VERSION 5.8 ;
BUSBITCHARS "[]" ;
DIVIDERCHAR "/" ;
UNITS
    DATABASE MICRONS 1000 ;
END UNITS

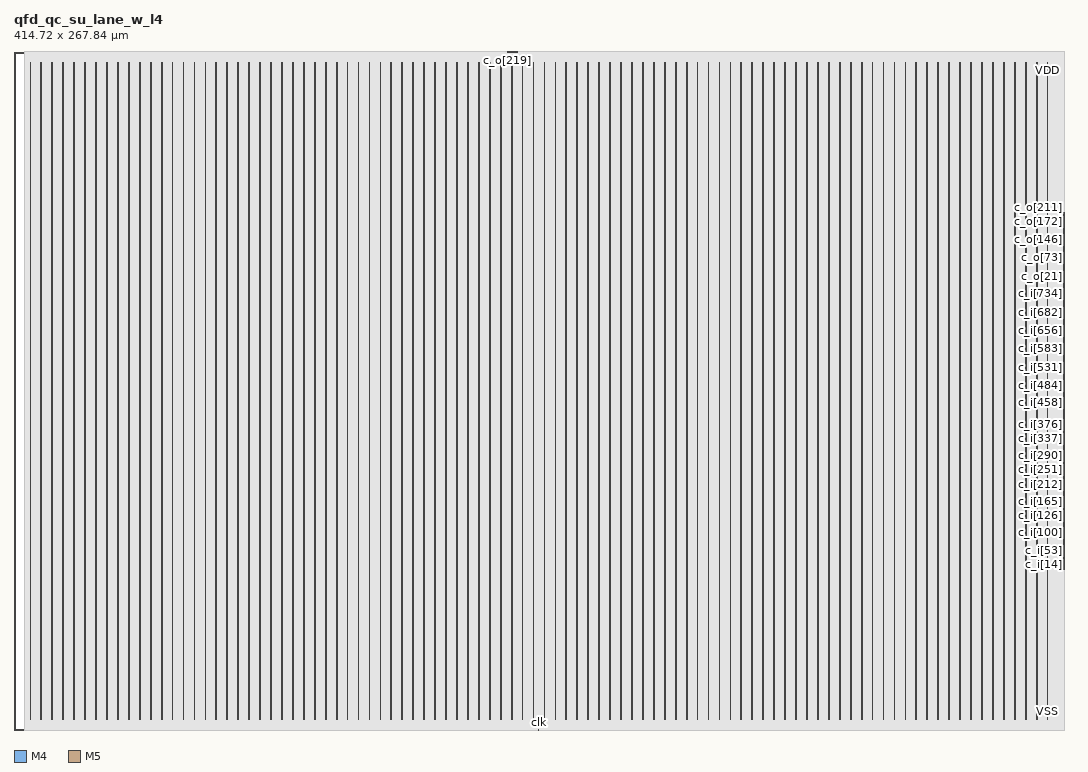
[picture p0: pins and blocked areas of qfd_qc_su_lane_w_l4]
MACRO qfd_qc_su_lane_w_l4
  FOREIGN qfd_qc_su_lane_w_l4 0 0 ;
  CLASS BLOCK ;
  SIZE 414.72 BY 267.84 ;
  PIN c_i[0]
    DIRECTION INPUT ;
    USE SIGNAL ;
    PORT
      LAYER M4 ;
        RECT  414.636 63.408 414.72 63.432 ;
    END
  END c_i[0]
  PIN c_i[100]
    DIRECTION INPUT ;
    USE SIGNAL ;
    PORT
      LAYER M4 ;
        RECT  414.636 77.808 414.72 77.832 ;
    END
  END c_i[100]
  PIN c_i[101]
    DIRECTION INPUT ;
    USE SIGNAL ;
    PORT
      LAYER M4 ;
        RECT  414.636 77.952 414.72 77.976 ;
    END
  END c_i[101]
  PIN c_i[102]
    DIRECTION INPUT ;
    USE SIGNAL ;
    PORT
      LAYER M4 ;
        RECT  414.636 78.096 414.72 78.12 ;
    END
  END c_i[102]
  PIN c_i[103]
    DIRECTION INPUT ;
    USE SIGNAL ;
    PORT
      LAYER M4 ;
        RECT  414.636 78.24 414.72 78.264 ;
    END
  END c_i[103]
  PIN c_i[104]
    DIRECTION INPUT ;
    USE SIGNAL ;
    PORT
      LAYER M4 ;
        RECT  414.636 78.384 414.72 78.408 ;
    END
  END c_i[104]
  PIN c_i[105]
    DIRECTION INPUT ;
    USE SIGNAL ;
    PORT
      LAYER M4 ;
        RECT  414.636 78.528 414.72 78.552 ;
    END
  END c_i[105]
  PIN c_i[106]
    DIRECTION INPUT ;
    USE SIGNAL ;
    PORT
      LAYER M4 ;
        RECT  414.636 78.672 414.72 78.696 ;
    END
  END c_i[106]
  PIN c_i[107]
    DIRECTION INPUT ;
    USE SIGNAL ;
    PORT
      LAYER M4 ;
        RECT  414.636 78.816 414.72 78.84 ;
    END
  END c_i[107]
  PIN c_i[108]
    DIRECTION INPUT ;
    USE SIGNAL ;
    PORT
      LAYER M4 ;
        RECT  414.636 78.96 414.72 78.984 ;
    END
  END c_i[108]
  PIN c_i[109]
    DIRECTION INPUT ;
    USE SIGNAL ;
    PORT
      LAYER M4 ;
        RECT  414.636 79.104 414.72 79.128 ;
    END
  END c_i[109]
  PIN c_i[10]
    DIRECTION INPUT ;
    USE SIGNAL ;
    PORT
      LAYER M4 ;
        RECT  414.636 64.848 414.72 64.872 ;
    END
  END c_i[10]
  PIN c_i[110]
    DIRECTION INPUT ;
    USE SIGNAL ;
    PORT
      LAYER M4 ;
        RECT  414.636 79.248 414.72 79.272 ;
    END
  END c_i[110]
  PIN c_i[111]
    DIRECTION INPUT ;
    USE SIGNAL ;
    PORT
      LAYER M4 ;
        RECT  414.636 79.392 414.72 79.416 ;
    END
  END c_i[111]
  PIN c_i[112]
    DIRECTION INPUT ;
    USE SIGNAL ;
    PORT
      LAYER M4 ;
        RECT  414.636 79.536 414.72 79.56 ;
    END
  END c_i[112]
  PIN c_i[113]
    DIRECTION INPUT ;
    USE SIGNAL ;
    PORT
      LAYER M4 ;
        RECT  414.636 79.68 414.72 79.704 ;
    END
  END c_i[113]
  PIN c_i[114]
    DIRECTION INPUT ;
    USE SIGNAL ;
    PORT
      LAYER M4 ;
        RECT  414.636 79.824 414.72 79.848 ;
    END
  END c_i[114]
  PIN c_i[115]
    DIRECTION INPUT ;
    USE SIGNAL ;
    PORT
      LAYER M4 ;
        RECT  414.636 79.968 414.72 79.992 ;
    END
  END c_i[115]
  PIN c_i[116]
    DIRECTION INPUT ;
    USE SIGNAL ;
    PORT
      LAYER M4 ;
        RECT  414.636 80.112 414.72 80.136 ;
    END
  END c_i[116]
  PIN c_i[117]
    DIRECTION INPUT ;
    USE SIGNAL ;
    PORT
      LAYER M4 ;
        RECT  414.636 80.256 414.72 80.28 ;
    END
  END c_i[117]
  PIN c_i[118]
    DIRECTION INPUT ;
    USE SIGNAL ;
    PORT
      LAYER M4 ;
        RECT  414.636 80.4 414.72 80.424 ;
    END
  END c_i[118]
  PIN c_i[119]
    DIRECTION INPUT ;
    USE SIGNAL ;
    PORT
      LAYER M4 ;
        RECT  414.636 80.544 414.72 80.568 ;
    END
  END c_i[119]
  PIN c_i[11]
    DIRECTION INPUT ;
    USE SIGNAL ;
    PORT
      LAYER M4 ;
        RECT  414.636 64.992 414.72 65.016 ;
    END
  END c_i[11]
  PIN c_i[120]
    DIRECTION INPUT ;
    USE SIGNAL ;
    PORT
      LAYER M4 ;
        RECT  414.636 80.688 414.72 80.712 ;
    END
  END c_i[120]
  PIN c_i[121]
    DIRECTION INPUT ;
    USE SIGNAL ;
    PORT
      LAYER M4 ;
        RECT  414.636 80.832 414.72 80.856 ;
    END
  END c_i[121]
  PIN c_i[122]
    DIRECTION INPUT ;
    USE SIGNAL ;
    PORT
      LAYER M4 ;
        RECT  414.636 80.976 414.72 81 ;
    END
  END c_i[122]
  PIN c_i[123]
    DIRECTION INPUT ;
    USE SIGNAL ;
    PORT
      LAYER M4 ;
        RECT  414.636 81.12 414.72 81.144 ;
    END
  END c_i[123]
  PIN c_i[124]
    DIRECTION INPUT ;
    USE SIGNAL ;
    PORT
      LAYER M4 ;
        RECT  414.636 81.264 414.72 81.288 ;
    END
  END c_i[124]
  PIN c_i[125]
    DIRECTION INPUT ;
    USE SIGNAL ;
    PORT
      LAYER M4 ;
        RECT  414.636 81.408 414.72 81.432 ;
    END
  END c_i[125]
  PIN c_i[126]
    DIRECTION INPUT ;
    USE SIGNAL ;
    PORT
      LAYER M4 ;
        RECT  414.636 81.552 414.72 81.576 ;
    END
  END c_i[126]
  PIN c_i[127]
    DIRECTION INPUT ;
    USE SIGNAL ;
    PORT
      LAYER M4 ;
        RECT  414.636 81.696 414.72 81.72 ;
    END
  END c_i[127]
  PIN c_i[128]
    DIRECTION INPUT ;
    USE SIGNAL ;
    PORT
      LAYER M4 ;
        RECT  414.636 81.84 414.72 81.864 ;
    END
  END c_i[128]
  PIN c_i[129]
    DIRECTION INPUT ;
    USE SIGNAL ;
    PORT
      LAYER M4 ;
        RECT  414.636 81.984 414.72 82.008 ;
    END
  END c_i[129]
  PIN c_i[12]
    DIRECTION INPUT ;
    USE SIGNAL ;
    PORT
      LAYER M4 ;
        RECT  414.636 65.136 414.72 65.16 ;
    END
  END c_i[12]
  PIN c_i[130]
    DIRECTION INPUT ;
    USE SIGNAL ;
    PORT
      LAYER M4 ;
        RECT  414.636 82.128 414.72 82.152 ;
    END
  END c_i[130]
  PIN c_i[131]
    DIRECTION INPUT ;
    USE SIGNAL ;
    PORT
      LAYER M4 ;
        RECT  414.636 82.272 414.72 82.296 ;
    END
  END c_i[131]
  PIN c_i[132]
    DIRECTION INPUT ;
    USE SIGNAL ;
    PORT
      LAYER M4 ;
        RECT  414.636 82.416 414.72 82.44 ;
    END
  END c_i[132]
  PIN c_i[133]
    DIRECTION INPUT ;
    USE SIGNAL ;
    PORT
      LAYER M4 ;
        RECT  414.636 82.56 414.72 82.584 ;
    END
  END c_i[133]
  PIN c_i[134]
    DIRECTION INPUT ;
    USE SIGNAL ;
    PORT
      LAYER M4 ;
        RECT  414.636 82.704 414.72 82.728 ;
    END
  END c_i[134]
  PIN c_i[135]
    DIRECTION INPUT ;
    USE SIGNAL ;
    PORT
      LAYER M4 ;
        RECT  414.636 82.848 414.72 82.872 ;
    END
  END c_i[135]
  PIN c_i[136]
    DIRECTION INPUT ;
    USE SIGNAL ;
    PORT
      LAYER M4 ;
        RECT  414.636 82.992 414.72 83.016 ;
    END
  END c_i[136]
  PIN c_i[137]
    DIRECTION INPUT ;
    USE SIGNAL ;
    PORT
      LAYER M4 ;
        RECT  414.636 83.136 414.72 83.16 ;
    END
  END c_i[137]
  PIN c_i[138]
    DIRECTION INPUT ;
    USE SIGNAL ;
    PORT
      LAYER M4 ;
        RECT  414.636 83.28 414.72 83.304 ;
    END
  END c_i[138]
  PIN c_i[139]
    DIRECTION INPUT ;
    USE SIGNAL ;
    PORT
      LAYER M4 ;
        RECT  414.636 83.424 414.72 83.448 ;
    END
  END c_i[139]
  PIN c_i[13]
    DIRECTION INPUT ;
    USE SIGNAL ;
    PORT
      LAYER M4 ;
        RECT  414.636 65.28 414.72 65.304 ;
    END
  END c_i[13]
  PIN c_i[140]
    DIRECTION INPUT ;
    USE SIGNAL ;
    PORT
      LAYER M4 ;
        RECT  414.636 83.568 414.72 83.592 ;
    END
  END c_i[140]
  PIN c_i[141]
    DIRECTION INPUT ;
    USE SIGNAL ;
    PORT
      LAYER M4 ;
        RECT  414.636 83.712 414.72 83.736 ;
    END
  END c_i[141]
  PIN c_i[142]
    DIRECTION INPUT ;
    USE SIGNAL ;
    PORT
      LAYER M4 ;
        RECT  414.636 83.856 414.72 83.88 ;
    END
  END c_i[142]
  PIN c_i[143]
    DIRECTION INPUT ;
    USE SIGNAL ;
    PORT
      LAYER M4 ;
        RECT  414.636 84 414.72 84.024 ;
    END
  END c_i[143]
  PIN c_i[144]
    DIRECTION INPUT ;
    USE SIGNAL ;
    PORT
      LAYER M4 ;
        RECT  414.636 84.144 414.72 84.168 ;
    END
  END c_i[144]
  PIN c_i[145]
    DIRECTION INPUT ;
    USE SIGNAL ;
    PORT
      LAYER M4 ;
        RECT  414.636 84.288 414.72 84.312 ;
    END
  END c_i[145]
  PIN c_i[146]
    DIRECTION INPUT ;
    USE SIGNAL ;
    PORT
      LAYER M4 ;
        RECT  414.636 84.432 414.72 84.456 ;
    END
  END c_i[146]
  PIN c_i[147]
    DIRECTION INPUT ;
    USE SIGNAL ;
    PORT
      LAYER M4 ;
        RECT  414.636 84.576 414.72 84.6 ;
    END
  END c_i[147]
  PIN c_i[148]
    DIRECTION INPUT ;
    USE SIGNAL ;
    PORT
      LAYER M4 ;
        RECT  414.636 84.72 414.72 84.744 ;
    END
  END c_i[148]
  PIN c_i[149]
    DIRECTION INPUT ;
    USE SIGNAL ;
    PORT
      LAYER M4 ;
        RECT  414.636 84.864 414.72 84.888 ;
    END
  END c_i[149]
  PIN c_i[14]
    DIRECTION INPUT ;
    USE SIGNAL ;
    PORT
      LAYER M4 ;
        RECT  414.636 65.424 414.72 65.448 ;
    END
  END c_i[14]
  PIN c_i[150]
    DIRECTION INPUT ;
    USE SIGNAL ;
    PORT
      LAYER M4 ;
        RECT  414.636 85.008 414.72 85.032 ;
    END
  END c_i[150]
  PIN c_i[151]
    DIRECTION INPUT ;
    USE SIGNAL ;
    PORT
      LAYER M4 ;
        RECT  414.636 85.152 414.72 85.176 ;
    END
  END c_i[151]
  PIN c_i[152]
    DIRECTION INPUT ;
    USE SIGNAL ;
    PORT
      LAYER M4 ;
        RECT  414.636 85.296 414.72 85.32 ;
    END
  END c_i[152]
  PIN c_i[153]
    DIRECTION INPUT ;
    USE SIGNAL ;
    PORT
      LAYER M4 ;
        RECT  414.636 85.44 414.72 85.464 ;
    END
  END c_i[153]
  PIN c_i[154]
    DIRECTION INPUT ;
    USE SIGNAL ;
    PORT
      LAYER M4 ;
        RECT  414.636 85.584 414.72 85.608 ;
    END
  END c_i[154]
  PIN c_i[155]
    DIRECTION INPUT ;
    USE SIGNAL ;
    PORT
      LAYER M4 ;
        RECT  414.636 85.728 414.72 85.752 ;
    END
  END c_i[155]
  PIN c_i[156]
    DIRECTION INPUT ;
    USE SIGNAL ;
    PORT
      LAYER M4 ;
        RECT  414.636 85.872 414.72 85.896 ;
    END
  END c_i[156]
  PIN c_i[157]
    DIRECTION INPUT ;
    USE SIGNAL ;
    PORT
      LAYER M4 ;
        RECT  414.636 86.016 414.72 86.04 ;
    END
  END c_i[157]
  PIN c_i[158]
    DIRECTION INPUT ;
    USE SIGNAL ;
    PORT
      LAYER M4 ;
        RECT  414.636 86.16 414.72 86.184 ;
    END
  END c_i[158]
  PIN c_i[159]
    DIRECTION INPUT ;
    USE SIGNAL ;
    PORT
      LAYER M4 ;
        RECT  414.636 86.304 414.72 86.328 ;
    END
  END c_i[159]
  PIN c_i[15]
    DIRECTION INPUT ;
    USE SIGNAL ;
    PORT
      LAYER M4 ;
        RECT  414.636 65.568 414.72 65.592 ;
    END
  END c_i[15]
  PIN c_i[160]
    DIRECTION INPUT ;
    USE SIGNAL ;
    PORT
      LAYER M4 ;
        RECT  414.636 86.448 414.72 86.472 ;
    END
  END c_i[160]
  PIN c_i[161]
    DIRECTION INPUT ;
    USE SIGNAL ;
    PORT
      LAYER M4 ;
        RECT  414.636 86.592 414.72 86.616 ;
    END
  END c_i[161]
  PIN c_i[162]
    DIRECTION INPUT ;
    USE SIGNAL ;
    PORT
      LAYER M4 ;
        RECT  414.636 86.736 414.72 86.76 ;
    END
  END c_i[162]
  PIN c_i[163]
    DIRECTION INPUT ;
    USE SIGNAL ;
    PORT
      LAYER M4 ;
        RECT  414.636 86.88 414.72 86.904 ;
    END
  END c_i[163]
  PIN c_i[164]
    DIRECTION INPUT ;
    USE SIGNAL ;
    PORT
      LAYER M4 ;
        RECT  414.636 87.024 414.72 87.048 ;
    END
  END c_i[164]
  PIN c_i[165]
    DIRECTION INPUT ;
    USE SIGNAL ;
    PORT
      LAYER M4 ;
        RECT  414.636 87.168 414.72 87.192 ;
    END
  END c_i[165]
  PIN c_i[166]
    DIRECTION INPUT ;
    USE SIGNAL ;
    PORT
      LAYER M4 ;
        RECT  414.636 87.312 414.72 87.336 ;
    END
  END c_i[166]
  PIN c_i[167]
    DIRECTION INPUT ;
    USE SIGNAL ;
    PORT
      LAYER M4 ;
        RECT  414.636 87.456 414.72 87.48 ;
    END
  END c_i[167]
  PIN c_i[168]
    DIRECTION INPUT ;
    USE SIGNAL ;
    PORT
      LAYER M4 ;
        RECT  414.636 87.6 414.72 87.624 ;
    END
  END c_i[168]
  PIN c_i[169]
    DIRECTION INPUT ;
    USE SIGNAL ;
    PORT
      LAYER M4 ;
        RECT  414.636 87.744 414.72 87.768 ;
    END
  END c_i[169]
  PIN c_i[16]
    DIRECTION INPUT ;
    USE SIGNAL ;
    PORT
      LAYER M4 ;
        RECT  414.636 65.712 414.72 65.736 ;
    END
  END c_i[16]
  PIN c_i[170]
    DIRECTION INPUT ;
    USE SIGNAL ;
    PORT
      LAYER M4 ;
        RECT  414.636 87.888 414.72 87.912 ;
    END
  END c_i[170]
  PIN c_i[171]
    DIRECTION INPUT ;
    USE SIGNAL ;
    PORT
      LAYER M4 ;
        RECT  414.636 88.032 414.72 88.056 ;
    END
  END c_i[171]
  PIN c_i[172]
    DIRECTION INPUT ;
    USE SIGNAL ;
    PORT
      LAYER M4 ;
        RECT  414.636 88.176 414.72 88.2 ;
    END
  END c_i[172]
  PIN c_i[173]
    DIRECTION INPUT ;
    USE SIGNAL ;
    PORT
      LAYER M4 ;
        RECT  414.636 88.32 414.72 88.344 ;
    END
  END c_i[173]
  PIN c_i[174]
    DIRECTION INPUT ;
    USE SIGNAL ;
    PORT
      LAYER M4 ;
        RECT  414.636 88.464 414.72 88.488 ;
    END
  END c_i[174]
  PIN c_i[175]
    DIRECTION INPUT ;
    USE SIGNAL ;
    PORT
      LAYER M4 ;
        RECT  414.636 88.608 414.72 88.632 ;
    END
  END c_i[175]
  PIN c_i[176]
    DIRECTION INPUT ;
    USE SIGNAL ;
    PORT
      LAYER M4 ;
        RECT  414.636 88.752 414.72 88.776 ;
    END
  END c_i[176]
  PIN c_i[177]
    DIRECTION INPUT ;
    USE SIGNAL ;
    PORT
      LAYER M4 ;
        RECT  414.636 88.896 414.72 88.92 ;
    END
  END c_i[177]
  PIN c_i[178]
    DIRECTION INPUT ;
    USE SIGNAL ;
    PORT
      LAYER M4 ;
        RECT  414.636 89.04 414.72 89.064 ;
    END
  END c_i[178]
  PIN c_i[179]
    DIRECTION INPUT ;
    USE SIGNAL ;
    PORT
      LAYER M4 ;
        RECT  414.636 89.184 414.72 89.208 ;
    END
  END c_i[179]
  PIN c_i[17]
    DIRECTION INPUT ;
    USE SIGNAL ;
    PORT
      LAYER M4 ;
        RECT  414.636 65.856 414.72 65.88 ;
    END
  END c_i[17]
  PIN c_i[180]
    DIRECTION INPUT ;
    USE SIGNAL ;
    PORT
      LAYER M4 ;
        RECT  414.636 89.328 414.72 89.352 ;
    END
  END c_i[180]
  PIN c_i[181]
    DIRECTION INPUT ;
    USE SIGNAL ;
    PORT
      LAYER M4 ;
        RECT  414.636 89.472 414.72 89.496 ;
    END
  END c_i[181]
  PIN c_i[182]
    DIRECTION INPUT ;
    USE SIGNAL ;
    PORT
      LAYER M4 ;
        RECT  414.636 89.616 414.72 89.64 ;
    END
  END c_i[182]
  PIN c_i[183]
    DIRECTION INPUT ;
    USE SIGNAL ;
    PORT
      LAYER M4 ;
        RECT  414.636 89.76 414.72 89.784 ;
    END
  END c_i[183]
  PIN c_i[184]
    DIRECTION INPUT ;
    USE SIGNAL ;
    PORT
      LAYER M4 ;
        RECT  414.636 89.904 414.72 89.928 ;
    END
  END c_i[184]
  PIN c_i[185]
    DIRECTION INPUT ;
    USE SIGNAL ;
    PORT
      LAYER M4 ;
        RECT  414.636 90.048 414.72 90.072 ;
    END
  END c_i[185]
  PIN c_i[186]
    DIRECTION INPUT ;
    USE SIGNAL ;
    PORT
      LAYER M4 ;
        RECT  414.636 90.192 414.72 90.216 ;
    END
  END c_i[186]
  PIN c_i[187]
    DIRECTION INPUT ;
    USE SIGNAL ;
    PORT
      LAYER M4 ;
        RECT  414.636 90.336 414.72 90.36 ;
    END
  END c_i[187]
  PIN c_i[188]
    DIRECTION INPUT ;
    USE SIGNAL ;
    PORT
      LAYER M4 ;
        RECT  414.636 90.48 414.72 90.504 ;
    END
  END c_i[188]
  PIN c_i[189]
    DIRECTION INPUT ;
    USE SIGNAL ;
    PORT
      LAYER M4 ;
        RECT  414.636 90.624 414.72 90.648 ;
    END
  END c_i[189]
  PIN c_i[18]
    DIRECTION INPUT ;
    USE SIGNAL ;
    PORT
      LAYER M4 ;
        RECT  414.636 66 414.72 66.024 ;
    END
  END c_i[18]
  PIN c_i[190]
    DIRECTION INPUT ;
    USE SIGNAL ;
    PORT
      LAYER M4 ;
        RECT  414.636 90.768 414.72 90.792 ;
    END
  END c_i[190]
  PIN c_i[191]
    DIRECTION INPUT ;
    USE SIGNAL ;
    PORT
      LAYER M4 ;
        RECT  414.636 90.912 414.72 90.936 ;
    END
  END c_i[191]
  PIN c_i[192]
    DIRECTION INPUT ;
    USE SIGNAL ;
    PORT
      LAYER M4 ;
        RECT  414.636 91.056 414.72 91.08 ;
    END
  END c_i[192]
  PIN c_i[193]
    DIRECTION INPUT ;
    USE SIGNAL ;
    PORT
      LAYER M4 ;
        RECT  414.636 91.2 414.72 91.224 ;
    END
  END c_i[193]
  PIN c_i[194]
    DIRECTION INPUT ;
    USE SIGNAL ;
    PORT
      LAYER M4 ;
        RECT  414.636 91.344 414.72 91.368 ;
    END
  END c_i[194]
  PIN c_i[195]
    DIRECTION INPUT ;
    USE SIGNAL ;
    PORT
      LAYER M4 ;
        RECT  414.636 91.488 414.72 91.512 ;
    END
  END c_i[195]
  PIN c_i[196]
    DIRECTION INPUT ;
    USE SIGNAL ;
    PORT
      LAYER M4 ;
        RECT  414.636 91.632 414.72 91.656 ;
    END
  END c_i[196]
  PIN c_i[197]
    DIRECTION INPUT ;
    USE SIGNAL ;
    PORT
      LAYER M4 ;
        RECT  414.636 91.776 414.72 91.8 ;
    END
  END c_i[197]
  PIN c_i[198]
    DIRECTION INPUT ;
    USE SIGNAL ;
    PORT
      LAYER M4 ;
        RECT  414.636 91.92 414.72 91.944 ;
    END
  END c_i[198]
  PIN c_i[199]
    DIRECTION INPUT ;
    USE SIGNAL ;
    PORT
      LAYER M4 ;
        RECT  414.636 92.064 414.72 92.088 ;
    END
  END c_i[199]
  PIN c_i[19]
    DIRECTION INPUT ;
    USE SIGNAL ;
    PORT
      LAYER M4 ;
        RECT  414.636 66.144 414.72 66.168 ;
    END
  END c_i[19]
  PIN c_i[1]
    DIRECTION INPUT ;
    USE SIGNAL ;
    PORT
      LAYER M4 ;
        RECT  414.636 63.552 414.72 63.576 ;
    END
  END c_i[1]
  PIN c_i[200]
    DIRECTION INPUT ;
    USE SIGNAL ;
    PORT
      LAYER M4 ;
        RECT  414.636 92.208 414.72 92.232 ;
    END
  END c_i[200]
  PIN c_i[201]
    DIRECTION INPUT ;
    USE SIGNAL ;
    PORT
      LAYER M4 ;
        RECT  414.636 92.352 414.72 92.376 ;
    END
  END c_i[201]
  PIN c_i[202]
    DIRECTION INPUT ;
    USE SIGNAL ;
    PORT
      LAYER M4 ;
        RECT  414.636 92.496 414.72 92.52 ;
    END
  END c_i[202]
  PIN c_i[203]
    DIRECTION INPUT ;
    USE SIGNAL ;
    PORT
      LAYER M4 ;
        RECT  414.636 92.64 414.72 92.664 ;
    END
  END c_i[203]
  PIN c_i[204]
    DIRECTION INPUT ;
    USE SIGNAL ;
    PORT
      LAYER M4 ;
        RECT  414.636 92.784 414.72 92.808 ;
    END
  END c_i[204]
  PIN c_i[205]
    DIRECTION INPUT ;
    USE SIGNAL ;
    PORT
      LAYER M4 ;
        RECT  414.636 92.928 414.72 92.952 ;
    END
  END c_i[205]
  PIN c_i[206]
    DIRECTION INPUT ;
    USE SIGNAL ;
    PORT
      LAYER M4 ;
        RECT  414.636 93.072 414.72 93.096 ;
    END
  END c_i[206]
  PIN c_i[207]
    DIRECTION INPUT ;
    USE SIGNAL ;
    PORT
      LAYER M4 ;
        RECT  414.636 93.216 414.72 93.24 ;
    END
  END c_i[207]
  PIN c_i[208]
    DIRECTION INPUT ;
    USE SIGNAL ;
    PORT
      LAYER M4 ;
        RECT  414.636 93.36 414.72 93.384 ;
    END
  END c_i[208]
  PIN c_i[209]
    DIRECTION INPUT ;
    USE SIGNAL ;
    PORT
      LAYER M4 ;
        RECT  414.636 93.504 414.72 93.528 ;
    END
  END c_i[209]
  PIN c_i[20]
    DIRECTION INPUT ;
    USE SIGNAL ;
    PORT
      LAYER M4 ;
        RECT  414.636 66.288 414.72 66.312 ;
    END
  END c_i[20]
  PIN c_i[210]
    DIRECTION INPUT ;
    USE SIGNAL ;
    PORT
      LAYER M4 ;
        RECT  414.636 93.648 414.72 93.672 ;
    END
  END c_i[210]
  PIN c_i[211]
    DIRECTION INPUT ;
    USE SIGNAL ;
    PORT
      LAYER M4 ;
        RECT  414.636 93.792 414.72 93.816 ;
    END
  END c_i[211]
  PIN c_i[212]
    DIRECTION INPUT ;
    USE SIGNAL ;
    PORT
      LAYER M4 ;
        RECT  414.636 93.936 414.72 93.96 ;
    END
  END c_i[212]
  PIN c_i[213]
    DIRECTION INPUT ;
    USE SIGNAL ;
    PORT
      LAYER M4 ;
        RECT  414.636 94.08 414.72 94.104 ;
    END
  END c_i[213]
  PIN c_i[214]
    DIRECTION INPUT ;
    USE SIGNAL ;
    PORT
      LAYER M4 ;
        RECT  414.636 94.224 414.72 94.248 ;
    END
  END c_i[214]
  PIN c_i[215]
    DIRECTION INPUT ;
    USE SIGNAL ;
    PORT
      LAYER M4 ;
        RECT  414.636 94.368 414.72 94.392 ;
    END
  END c_i[215]
  PIN c_i[216]
    DIRECTION INPUT ;
    USE SIGNAL ;
    PORT
      LAYER M4 ;
        RECT  414.636 94.512 414.72 94.536 ;
    END
  END c_i[216]
  PIN c_i[217]
    DIRECTION INPUT ;
    USE SIGNAL ;
    PORT
      LAYER M4 ;
        RECT  414.636 94.656 414.72 94.68 ;
    END
  END c_i[217]
  PIN c_i[218]
    DIRECTION INPUT ;
    USE SIGNAL ;
    PORT
      LAYER M4 ;
        RECT  414.636 94.8 414.72 94.824 ;
    END
  END c_i[218]
  PIN c_i[219]
    DIRECTION INPUT ;
    USE SIGNAL ;
    PORT
      LAYER M4 ;
        RECT  414.636 94.944 414.72 94.968 ;
    END
  END c_i[219]
  PIN c_i[21]
    DIRECTION INPUT ;
    USE SIGNAL ;
    PORT
      LAYER M4 ;
        RECT  414.636 66.432 414.72 66.456 ;
    END
  END c_i[21]
  PIN c_i[220]
    DIRECTION INPUT ;
    USE SIGNAL ;
    PORT
      LAYER M4 ;
        RECT  414.636 95.088 414.72 95.112 ;
    END
  END c_i[220]
  PIN c_i[221]
    DIRECTION INPUT ;
    USE SIGNAL ;
    PORT
      LAYER M4 ;
        RECT  414.636 95.232 414.72 95.256 ;
    END
  END c_i[221]
  PIN c_i[222]
    DIRECTION INPUT ;
    USE SIGNAL ;
    PORT
      LAYER M4 ;
        RECT  414.636 95.376 414.72 95.4 ;
    END
  END c_i[222]
  PIN c_i[223]
    DIRECTION INPUT ;
    USE SIGNAL ;
    PORT
      LAYER M4 ;
        RECT  414.636 95.52 414.72 95.544 ;
    END
  END c_i[223]
  PIN c_i[224]
    DIRECTION INPUT ;
    USE SIGNAL ;
    PORT
      LAYER M4 ;
        RECT  414.636 95.664 414.72 95.688 ;
    END
  END c_i[224]
  PIN c_i[225]
    DIRECTION INPUT ;
    USE SIGNAL ;
    PORT
      LAYER M4 ;
        RECT  414.636 95.808 414.72 95.832 ;
    END
  END c_i[225]
  PIN c_i[226]
    DIRECTION INPUT ;
    USE SIGNAL ;
    PORT
      LAYER M4 ;
        RECT  414.636 95.952 414.72 95.976 ;
    END
  END c_i[226]
  PIN c_i[227]
    DIRECTION INPUT ;
    USE SIGNAL ;
    PORT
      LAYER M4 ;
        RECT  414.636 96.096 414.72 96.12 ;
    END
  END c_i[227]
  PIN c_i[228]
    DIRECTION INPUT ;
    USE SIGNAL ;
    PORT
      LAYER M4 ;
        RECT  414.636 96.24 414.72 96.264 ;
    END
  END c_i[228]
  PIN c_i[229]
    DIRECTION INPUT ;
    USE SIGNAL ;
    PORT
      LAYER M4 ;
        RECT  414.636 96.384 414.72 96.408 ;
    END
  END c_i[229]
  PIN c_i[22]
    DIRECTION INPUT ;
    USE SIGNAL ;
    PORT
      LAYER M4 ;
        RECT  414.636 66.576 414.72 66.6 ;
    END
  END c_i[22]
  PIN c_i[230]
    DIRECTION INPUT ;
    USE SIGNAL ;
    PORT
      LAYER M4 ;
        RECT  414.636 96.528 414.72 96.552 ;
    END
  END c_i[230]
  PIN c_i[231]
    DIRECTION INPUT ;
    USE SIGNAL ;
    PORT
      LAYER M4 ;
        RECT  414.636 96.672 414.72 96.696 ;
    END
  END c_i[231]
  PIN c_i[232]
    DIRECTION INPUT ;
    USE SIGNAL ;
    PORT
      LAYER M4 ;
        RECT  414.636 96.816 414.72 96.84 ;
    END
  END c_i[232]
  PIN c_i[233]
    DIRECTION INPUT ;
    USE SIGNAL ;
    PORT
      LAYER M4 ;
        RECT  414.636 96.96 414.72 96.984 ;
    END
  END c_i[233]
  PIN c_i[234]
    DIRECTION INPUT ;
    USE SIGNAL ;
    PORT
      LAYER M4 ;
        RECT  414.636 97.104 414.72 97.128 ;
    END
  END c_i[234]
  PIN c_i[235]
    DIRECTION INPUT ;
    USE SIGNAL ;
    PORT
      LAYER M4 ;
        RECT  414.636 97.248 414.72 97.272 ;
    END
  END c_i[235]
  PIN c_i[236]
    DIRECTION INPUT ;
    USE SIGNAL ;
    PORT
      LAYER M4 ;
        RECT  414.636 97.392 414.72 97.416 ;
    END
  END c_i[236]
  PIN c_i[237]
    DIRECTION INPUT ;
    USE SIGNAL ;
    PORT
      LAYER M4 ;
        RECT  414.636 97.536 414.72 97.56 ;
    END
  END c_i[237]
  PIN c_i[238]
    DIRECTION INPUT ;
    USE SIGNAL ;
    PORT
      LAYER M4 ;
        RECT  414.636 97.68 414.72 97.704 ;
    END
  END c_i[238]
  PIN c_i[239]
    DIRECTION INPUT ;
    USE SIGNAL ;
    PORT
      LAYER M4 ;
        RECT  414.636 97.824 414.72 97.848 ;
    END
  END c_i[239]
  PIN c_i[23]
    DIRECTION INPUT ;
    USE SIGNAL ;
    PORT
      LAYER M4 ;
        RECT  414.636 66.72 414.72 66.744 ;
    END
  END c_i[23]
  PIN c_i[240]
    DIRECTION INPUT ;
    USE SIGNAL ;
    PORT
      LAYER M4 ;
        RECT  414.636 97.968 414.72 97.992 ;
    END
  END c_i[240]
  PIN c_i[241]
    DIRECTION INPUT ;
    USE SIGNAL ;
    PORT
      LAYER M4 ;
        RECT  414.636 98.112 414.72 98.136 ;
    END
  END c_i[241]
  PIN c_i[242]
    DIRECTION INPUT ;
    USE SIGNAL ;
    PORT
      LAYER M4 ;
        RECT  414.636 98.256 414.72 98.28 ;
    END
  END c_i[242]
  PIN c_i[243]
    DIRECTION INPUT ;
    USE SIGNAL ;
    PORT
      LAYER M4 ;
        RECT  414.636 98.4 414.72 98.424 ;
    END
  END c_i[243]
  PIN c_i[244]
    DIRECTION INPUT ;
    USE SIGNAL ;
    PORT
      LAYER M4 ;
        RECT  414.636 98.544 414.72 98.568 ;
    END
  END c_i[244]
  PIN c_i[245]
    DIRECTION INPUT ;
    USE SIGNAL ;
    PORT
      LAYER M4 ;
        RECT  414.636 98.688 414.72 98.712 ;
    END
  END c_i[245]
  PIN c_i[246]
    DIRECTION INPUT ;
    USE SIGNAL ;
    PORT
      LAYER M4 ;
        RECT  414.636 98.832 414.72 98.856 ;
    END
  END c_i[246]
  PIN c_i[247]
    DIRECTION INPUT ;
    USE SIGNAL ;
    PORT
      LAYER M4 ;
        RECT  414.636 98.976 414.72 99 ;
    END
  END c_i[247]
  PIN c_i[248]
    DIRECTION INPUT ;
    USE SIGNAL ;
    PORT
      LAYER M4 ;
        RECT  414.636 99.12 414.72 99.144 ;
    END
  END c_i[248]
  PIN c_i[249]
    DIRECTION INPUT ;
    USE SIGNAL ;
    PORT
      LAYER M4 ;
        RECT  414.636 99.264 414.72 99.288 ;
    END
  END c_i[249]
  PIN c_i[24]
    DIRECTION INPUT ;
    USE SIGNAL ;
    PORT
      LAYER M4 ;
        RECT  414.636 66.864 414.72 66.888 ;
    END
  END c_i[24]
  PIN c_i[250]
    DIRECTION INPUT ;
    USE SIGNAL ;
    PORT
      LAYER M4 ;
        RECT  414.636 99.408 414.72 99.432 ;
    END
  END c_i[250]
  PIN c_i[251]
    DIRECTION INPUT ;
    USE SIGNAL ;
    PORT
      LAYER M4 ;
        RECT  414.636 99.552 414.72 99.576 ;
    END
  END c_i[251]
  PIN c_i[252]
    DIRECTION INPUT ;
    USE SIGNAL ;
    PORT
      LAYER M4 ;
        RECT  414.636 99.696 414.72 99.72 ;
    END
  END c_i[252]
  PIN c_i[253]
    DIRECTION INPUT ;
    USE SIGNAL ;
    PORT
      LAYER M4 ;
        RECT  414.636 99.84 414.72 99.864 ;
    END
  END c_i[253]
  PIN c_i[254]
    DIRECTION INPUT ;
    USE SIGNAL ;
    PORT
      LAYER M4 ;
        RECT  414.636 99.984 414.72 100.008 ;
    END
  END c_i[254]
  PIN c_i[255]
    DIRECTION INPUT ;
    USE SIGNAL ;
    PORT
      LAYER M4 ;
        RECT  414.636 100.128 414.72 100.152 ;
    END
  END c_i[255]
  PIN c_i[256]
    DIRECTION INPUT ;
    USE SIGNAL ;
    PORT
      LAYER M4 ;
        RECT  414.636 100.272 414.72 100.296 ;
    END
  END c_i[256]
  PIN c_i[257]
    DIRECTION INPUT ;
    USE SIGNAL ;
    PORT
      LAYER M4 ;
        RECT  414.636 100.416 414.72 100.44 ;
    END
  END c_i[257]
  PIN c_i[258]
    DIRECTION INPUT ;
    USE SIGNAL ;
    PORT
      LAYER M4 ;
        RECT  414.636 100.56 414.72 100.584 ;
    END
  END c_i[258]
  PIN c_i[259]
    DIRECTION INPUT ;
    USE SIGNAL ;
    PORT
      LAYER M4 ;
        RECT  414.636 100.704 414.72 100.728 ;
    END
  END c_i[259]
  PIN c_i[25]
    DIRECTION INPUT ;
    USE SIGNAL ;
    PORT
      LAYER M4 ;
        RECT  414.636 67.008 414.72 67.032 ;
    END
  END c_i[25]
  PIN c_i[260]
    DIRECTION INPUT ;
    USE SIGNAL ;
    PORT
      LAYER M4 ;
        RECT  414.636 100.848 414.72 100.872 ;
    END
  END c_i[260]
  PIN c_i[261]
    DIRECTION INPUT ;
    USE SIGNAL ;
    PORT
      LAYER M4 ;
        RECT  414.636 100.992 414.72 101.016 ;
    END
  END c_i[261]
  PIN c_i[262]
    DIRECTION INPUT ;
    USE SIGNAL ;
    PORT
      LAYER M4 ;
        RECT  414.636 101.136 414.72 101.16 ;
    END
  END c_i[262]
  PIN c_i[263]
    DIRECTION INPUT ;
    USE SIGNAL ;
    PORT
      LAYER M4 ;
        RECT  414.636 101.28 414.72 101.304 ;
    END
  END c_i[263]
  PIN c_i[264]
    DIRECTION INPUT ;
    USE SIGNAL ;
    PORT
      LAYER M4 ;
        RECT  414.636 101.424 414.72 101.448 ;
    END
  END c_i[264]
  PIN c_i[265]
    DIRECTION INPUT ;
    USE SIGNAL ;
    PORT
      LAYER M4 ;
        RECT  414.636 101.568 414.72 101.592 ;
    END
  END c_i[265]
  PIN c_i[266]
    DIRECTION INPUT ;
    USE SIGNAL ;
    PORT
      LAYER M4 ;
        RECT  414.636 101.712 414.72 101.736 ;
    END
  END c_i[266]
  PIN c_i[267]
    DIRECTION INPUT ;
    USE SIGNAL ;
    PORT
      LAYER M4 ;
        RECT  414.636 101.856 414.72 101.88 ;
    END
  END c_i[267]
  PIN c_i[268]
    DIRECTION INPUT ;
    USE SIGNAL ;
    PORT
      LAYER M4 ;
        RECT  414.636 102 414.72 102.024 ;
    END
  END c_i[268]
  PIN c_i[269]
    DIRECTION INPUT ;
    USE SIGNAL ;
    PORT
      LAYER M4 ;
        RECT  414.636 102.144 414.72 102.168 ;
    END
  END c_i[269]
  PIN c_i[26]
    DIRECTION INPUT ;
    USE SIGNAL ;
    PORT
      LAYER M4 ;
        RECT  414.636 67.152 414.72 67.176 ;
    END
  END c_i[26]
  PIN c_i[270]
    DIRECTION INPUT ;
    USE SIGNAL ;
    PORT
      LAYER M4 ;
        RECT  414.636 102.288 414.72 102.312 ;
    END
  END c_i[270]
  PIN c_i[271]
    DIRECTION INPUT ;
    USE SIGNAL ;
    PORT
      LAYER M4 ;
        RECT  414.636 102.432 414.72 102.456 ;
    END
  END c_i[271]
  PIN c_i[272]
    DIRECTION INPUT ;
    USE SIGNAL ;
    PORT
      LAYER M4 ;
        RECT  414.636 102.576 414.72 102.6 ;
    END
  END c_i[272]
  PIN c_i[273]
    DIRECTION INPUT ;
    USE SIGNAL ;
    PORT
      LAYER M4 ;
        RECT  414.636 102.72 414.72 102.744 ;
    END
  END c_i[273]
  PIN c_i[274]
    DIRECTION INPUT ;
    USE SIGNAL ;
    PORT
      LAYER M4 ;
        RECT  414.636 102.864 414.72 102.888 ;
    END
  END c_i[274]
  PIN c_i[275]
    DIRECTION INPUT ;
    USE SIGNAL ;
    PORT
      LAYER M4 ;
        RECT  414.636 103.008 414.72 103.032 ;
    END
  END c_i[275]
  PIN c_i[276]
    DIRECTION INPUT ;
    USE SIGNAL ;
    PORT
      LAYER M4 ;
        RECT  414.636 103.152 414.72 103.176 ;
    END
  END c_i[276]
  PIN c_i[277]
    DIRECTION INPUT ;
    USE SIGNAL ;
    PORT
      LAYER M4 ;
        RECT  414.636 103.296 414.72 103.32 ;
    END
  END c_i[277]
  PIN c_i[278]
    DIRECTION INPUT ;
    USE SIGNAL ;
    PORT
      LAYER M4 ;
        RECT  414.636 103.44 414.72 103.464 ;
    END
  END c_i[278]
  PIN c_i[279]
    DIRECTION INPUT ;
    USE SIGNAL ;
    PORT
      LAYER M4 ;
        RECT  414.636 103.584 414.72 103.608 ;
    END
  END c_i[279]
  PIN c_i[27]
    DIRECTION INPUT ;
    USE SIGNAL ;
    PORT
      LAYER M4 ;
        RECT  414.636 67.296 414.72 67.32 ;
    END
  END c_i[27]
  PIN c_i[280]
    DIRECTION INPUT ;
    USE SIGNAL ;
    PORT
      LAYER M4 ;
        RECT  414.636 103.728 414.72 103.752 ;
    END
  END c_i[280]
  PIN c_i[281]
    DIRECTION INPUT ;
    USE SIGNAL ;
    PORT
      LAYER M4 ;
        RECT  414.636 103.872 414.72 103.896 ;
    END
  END c_i[281]
  PIN c_i[282]
    DIRECTION INPUT ;
    USE SIGNAL ;
    PORT
      LAYER M4 ;
        RECT  414.636 104.016 414.72 104.04 ;
    END
  END c_i[282]
  PIN c_i[283]
    DIRECTION INPUT ;
    USE SIGNAL ;
    PORT
      LAYER M4 ;
        RECT  414.636 104.16 414.72 104.184 ;
    END
  END c_i[283]
  PIN c_i[284]
    DIRECTION INPUT ;
    USE SIGNAL ;
    PORT
      LAYER M4 ;
        RECT  414.636 104.304 414.72 104.328 ;
    END
  END c_i[284]
  PIN c_i[285]
    DIRECTION INPUT ;
    USE SIGNAL ;
    PORT
      LAYER M4 ;
        RECT  414.636 104.448 414.72 104.472 ;
    END
  END c_i[285]
  PIN c_i[286]
    DIRECTION INPUT ;
    USE SIGNAL ;
    PORT
      LAYER M4 ;
        RECT  414.636 104.592 414.72 104.616 ;
    END
  END c_i[286]
  PIN c_i[287]
    DIRECTION INPUT ;
    USE SIGNAL ;
    PORT
      LAYER M4 ;
        RECT  414.636 104.736 414.72 104.76 ;
    END
  END c_i[287]
  PIN c_i[288]
    DIRECTION INPUT ;
    USE SIGNAL ;
    PORT
      LAYER M4 ;
        RECT  414.636 104.88 414.72 104.904 ;
    END
  END c_i[288]
  PIN c_i[289]
    DIRECTION INPUT ;
    USE SIGNAL ;
    PORT
      LAYER M4 ;
        RECT  414.636 105.024 414.72 105.048 ;
    END
  END c_i[289]
  PIN c_i[28]
    DIRECTION INPUT ;
    USE SIGNAL ;
    PORT
      LAYER M4 ;
        RECT  414.636 67.44 414.72 67.464 ;
    END
  END c_i[28]
  PIN c_i[290]
    DIRECTION INPUT ;
    USE SIGNAL ;
    PORT
      LAYER M4 ;
        RECT  414.636 105.168 414.72 105.192 ;
    END
  END c_i[290]
  PIN c_i[291]
    DIRECTION INPUT ;
    USE SIGNAL ;
    PORT
      LAYER M4 ;
        RECT  414.636 105.312 414.72 105.336 ;
    END
  END c_i[291]
  PIN c_i[292]
    DIRECTION INPUT ;
    USE SIGNAL ;
    PORT
      LAYER M4 ;
        RECT  414.636 105.456 414.72 105.48 ;
    END
  END c_i[292]
  PIN c_i[293]
    DIRECTION INPUT ;
    USE SIGNAL ;
    PORT
      LAYER M4 ;
        RECT  414.636 105.6 414.72 105.624 ;
    END
  END c_i[293]
  PIN c_i[294]
    DIRECTION INPUT ;
    USE SIGNAL ;
    PORT
      LAYER M4 ;
        RECT  414.636 105.744 414.72 105.768 ;
    END
  END c_i[294]
  PIN c_i[295]
    DIRECTION INPUT ;
    USE SIGNAL ;
    PORT
      LAYER M4 ;
        RECT  414.636 105.888 414.72 105.912 ;
    END
  END c_i[295]
  PIN c_i[296]
    DIRECTION INPUT ;
    USE SIGNAL ;
    PORT
      LAYER M4 ;
        RECT  414.636 106.032 414.72 106.056 ;
    END
  END c_i[296]
  PIN c_i[297]
    DIRECTION INPUT ;
    USE SIGNAL ;
    PORT
      LAYER M4 ;
        RECT  414.636 106.176 414.72 106.2 ;
    END
  END c_i[297]
  PIN c_i[298]
    DIRECTION INPUT ;
    USE SIGNAL ;
    PORT
      LAYER M4 ;
        RECT  414.636 106.32 414.72 106.344 ;
    END
  END c_i[298]
  PIN c_i[299]
    DIRECTION INPUT ;
    USE SIGNAL ;
    PORT
      LAYER M4 ;
        RECT  414.636 106.464 414.72 106.488 ;
    END
  END c_i[299]
  PIN c_i[29]
    DIRECTION INPUT ;
    USE SIGNAL ;
    PORT
      LAYER M4 ;
        RECT  414.636 67.584 414.72 67.608 ;
    END
  END c_i[29]
  PIN c_i[2]
    DIRECTION INPUT ;
    USE SIGNAL ;
    PORT
      LAYER M4 ;
        RECT  414.636 63.696 414.72 63.72 ;
    END
  END c_i[2]
  PIN c_i[300]
    DIRECTION INPUT ;
    USE SIGNAL ;
    PORT
      LAYER M4 ;
        RECT  414.636 106.608 414.72 106.632 ;
    END
  END c_i[300]
  PIN c_i[301]
    DIRECTION INPUT ;
    USE SIGNAL ;
    PORT
      LAYER M4 ;
        RECT  414.636 106.752 414.72 106.776 ;
    END
  END c_i[301]
  PIN c_i[302]
    DIRECTION INPUT ;
    USE SIGNAL ;
    PORT
      LAYER M4 ;
        RECT  414.636 106.896 414.72 106.92 ;
    END
  END c_i[302]
  PIN c_i[303]
    DIRECTION INPUT ;
    USE SIGNAL ;
    PORT
      LAYER M4 ;
        RECT  414.636 107.04 414.72 107.064 ;
    END
  END c_i[303]
  PIN c_i[304]
    DIRECTION INPUT ;
    USE SIGNAL ;
    PORT
      LAYER M4 ;
        RECT  414.636 107.184 414.72 107.208 ;
    END
  END c_i[304]
  PIN c_i[305]
    DIRECTION INPUT ;
    USE SIGNAL ;
    PORT
      LAYER M4 ;
        RECT  414.636 107.328 414.72 107.352 ;
    END
  END c_i[305]
  PIN c_i[306]
    DIRECTION INPUT ;
    USE SIGNAL ;
    PORT
      LAYER M4 ;
        RECT  414.636 107.472 414.72 107.496 ;
    END
  END c_i[306]
  PIN c_i[307]
    DIRECTION INPUT ;
    USE SIGNAL ;
    PORT
      LAYER M4 ;
        RECT  414.636 107.616 414.72 107.64 ;
    END
  END c_i[307]
  PIN c_i[308]
    DIRECTION INPUT ;
    USE SIGNAL ;
    PORT
      LAYER M4 ;
        RECT  414.636 107.76 414.72 107.784 ;
    END
  END c_i[308]
  PIN c_i[309]
    DIRECTION INPUT ;
    USE SIGNAL ;
    PORT
      LAYER M4 ;
        RECT  414.636 107.904 414.72 107.928 ;
    END
  END c_i[309]
  PIN c_i[30]
    DIRECTION INPUT ;
    USE SIGNAL ;
    PORT
      LAYER M4 ;
        RECT  414.636 67.728 414.72 67.752 ;
    END
  END c_i[30]
  PIN c_i[310]
    DIRECTION INPUT ;
    USE SIGNAL ;
    PORT
      LAYER M4 ;
        RECT  414.636 108.048 414.72 108.072 ;
    END
  END c_i[310]
  PIN c_i[311]
    DIRECTION INPUT ;
    USE SIGNAL ;
    PORT
      LAYER M4 ;
        RECT  414.636 108.192 414.72 108.216 ;
    END
  END c_i[311]
  PIN c_i[312]
    DIRECTION INPUT ;
    USE SIGNAL ;
    PORT
      LAYER M4 ;
        RECT  414.636 108.336 414.72 108.36 ;
    END
  END c_i[312]
  PIN c_i[313]
    DIRECTION INPUT ;
    USE SIGNAL ;
    PORT
      LAYER M4 ;
        RECT  414.636 108.48 414.72 108.504 ;
    END
  END c_i[313]
  PIN c_i[314]
    DIRECTION INPUT ;
    USE SIGNAL ;
    PORT
      LAYER M4 ;
        RECT  414.636 108.624 414.72 108.648 ;
    END
  END c_i[314]
  PIN c_i[315]
    DIRECTION INPUT ;
    USE SIGNAL ;
    PORT
      LAYER M4 ;
        RECT  414.636 108.768 414.72 108.792 ;
    END
  END c_i[315]
  PIN c_i[316]
    DIRECTION INPUT ;
    USE SIGNAL ;
    PORT
      LAYER M4 ;
        RECT  414.636 108.912 414.72 108.936 ;
    END
  END c_i[316]
  PIN c_i[317]
    DIRECTION INPUT ;
    USE SIGNAL ;
    PORT
      LAYER M4 ;
        RECT  414.636 109.056 414.72 109.08 ;
    END
  END c_i[317]
  PIN c_i[318]
    DIRECTION INPUT ;
    USE SIGNAL ;
    PORT
      LAYER M4 ;
        RECT  414.636 109.2 414.72 109.224 ;
    END
  END c_i[318]
  PIN c_i[319]
    DIRECTION INPUT ;
    USE SIGNAL ;
    PORT
      LAYER M4 ;
        RECT  414.636 109.344 414.72 109.368 ;
    END
  END c_i[319]
  PIN c_i[31]
    DIRECTION INPUT ;
    USE SIGNAL ;
    PORT
      LAYER M4 ;
        RECT  414.636 67.872 414.72 67.896 ;
    END
  END c_i[31]
  PIN c_i[320]
    DIRECTION INPUT ;
    USE SIGNAL ;
    PORT
      LAYER M4 ;
        RECT  414.636 109.488 414.72 109.512 ;
    END
  END c_i[320]
  PIN c_i[321]
    DIRECTION INPUT ;
    USE SIGNAL ;
    PORT
      LAYER M4 ;
        RECT  414.636 109.632 414.72 109.656 ;
    END
  END c_i[321]
  PIN c_i[322]
    DIRECTION INPUT ;
    USE SIGNAL ;
    PORT
      LAYER M4 ;
        RECT  414.636 109.776 414.72 109.8 ;
    END
  END c_i[322]
  PIN c_i[323]
    DIRECTION INPUT ;
    USE SIGNAL ;
    PORT
      LAYER M4 ;
        RECT  414.636 109.92 414.72 109.944 ;
    END
  END c_i[323]
  PIN c_i[324]
    DIRECTION INPUT ;
    USE SIGNAL ;
    PORT
      LAYER M4 ;
        RECT  414.636 110.064 414.72 110.088 ;
    END
  END c_i[324]
  PIN c_i[325]
    DIRECTION INPUT ;
    USE SIGNAL ;
    PORT
      LAYER M4 ;
        RECT  414.636 110.208 414.72 110.232 ;
    END
  END c_i[325]
  PIN c_i[326]
    DIRECTION INPUT ;
    USE SIGNAL ;
    PORT
      LAYER M4 ;
        RECT  414.636 110.352 414.72 110.376 ;
    END
  END c_i[326]
  PIN c_i[327]
    DIRECTION INPUT ;
    USE SIGNAL ;
    PORT
      LAYER M4 ;
        RECT  414.636 110.496 414.72 110.52 ;
    END
  END c_i[327]
  PIN c_i[328]
    DIRECTION INPUT ;
    USE SIGNAL ;
    PORT
      LAYER M4 ;
        RECT  414.636 110.64 414.72 110.664 ;
    END
  END c_i[328]
  PIN c_i[329]
    DIRECTION INPUT ;
    USE SIGNAL ;
    PORT
      LAYER M4 ;
        RECT  414.636 110.784 414.72 110.808 ;
    END
  END c_i[329]
  PIN c_i[32]
    DIRECTION INPUT ;
    USE SIGNAL ;
    PORT
      LAYER M4 ;
        RECT  414.636 68.016 414.72 68.04 ;
    END
  END c_i[32]
  PIN c_i[330]
    DIRECTION INPUT ;
    USE SIGNAL ;
    PORT
      LAYER M4 ;
        RECT  414.636 110.928 414.72 110.952 ;
    END
  END c_i[330]
  PIN c_i[331]
    DIRECTION INPUT ;
    USE SIGNAL ;
    PORT
      LAYER M4 ;
        RECT  414.636 111.072 414.72 111.096 ;
    END
  END c_i[331]
  PIN c_i[332]
    DIRECTION INPUT ;
    USE SIGNAL ;
    PORT
      LAYER M4 ;
        RECT  414.636 111.216 414.72 111.24 ;
    END
  END c_i[332]
  PIN c_i[333]
    DIRECTION INPUT ;
    USE SIGNAL ;
    PORT
      LAYER M4 ;
        RECT  414.636 111.36 414.72 111.384 ;
    END
  END c_i[333]
  PIN c_i[334]
    DIRECTION INPUT ;
    USE SIGNAL ;
    PORT
      LAYER M4 ;
        RECT  414.636 111.504 414.72 111.528 ;
    END
  END c_i[334]
  PIN c_i[335]
    DIRECTION INPUT ;
    USE SIGNAL ;
    PORT
      LAYER M4 ;
        RECT  414.636 111.648 414.72 111.672 ;
    END
  END c_i[335]
  PIN c_i[336]
    DIRECTION INPUT ;
    USE SIGNAL ;
    PORT
      LAYER M4 ;
        RECT  414.636 111.792 414.72 111.816 ;
    END
  END c_i[336]
  PIN c_i[337]
    DIRECTION INPUT ;
    USE SIGNAL ;
    PORT
      LAYER M4 ;
        RECT  414.636 111.936 414.72 111.96 ;
    END
  END c_i[337]
  PIN c_i[338]
    DIRECTION INPUT ;
    USE SIGNAL ;
    PORT
      LAYER M4 ;
        RECT  414.636 112.08 414.72 112.104 ;
    END
  END c_i[338]
  PIN c_i[339]
    DIRECTION INPUT ;
    USE SIGNAL ;
    PORT
      LAYER M4 ;
        RECT  414.636 112.224 414.72 112.248 ;
    END
  END c_i[339]
  PIN c_i[33]
    DIRECTION INPUT ;
    USE SIGNAL ;
    PORT
      LAYER M4 ;
        RECT  414.636 68.16 414.72 68.184 ;
    END
  END c_i[33]
  PIN c_i[340]
    DIRECTION INPUT ;
    USE SIGNAL ;
    PORT
      LAYER M4 ;
        RECT  414.636 112.368 414.72 112.392 ;
    END
  END c_i[340]
  PIN c_i[341]
    DIRECTION INPUT ;
    USE SIGNAL ;
    PORT
      LAYER M4 ;
        RECT  414.636 112.512 414.72 112.536 ;
    END
  END c_i[341]
  PIN c_i[342]
    DIRECTION INPUT ;
    USE SIGNAL ;
    PORT
      LAYER M4 ;
        RECT  414.636 112.656 414.72 112.68 ;
    END
  END c_i[342]
  PIN c_i[343]
    DIRECTION INPUT ;
    USE SIGNAL ;
    PORT
      LAYER M4 ;
        RECT  414.636 112.8 414.72 112.824 ;
    END
  END c_i[343]
  PIN c_i[344]
    DIRECTION INPUT ;
    USE SIGNAL ;
    PORT
      LAYER M4 ;
        RECT  414.636 112.944 414.72 112.968 ;
    END
  END c_i[344]
  PIN c_i[345]
    DIRECTION INPUT ;
    USE SIGNAL ;
    PORT
      LAYER M4 ;
        RECT  414.636 113.088 414.72 113.112 ;
    END
  END c_i[345]
  PIN c_i[346]
    DIRECTION INPUT ;
    USE SIGNAL ;
    PORT
      LAYER M4 ;
        RECT  414.636 113.232 414.72 113.256 ;
    END
  END c_i[346]
  PIN c_i[347]
    DIRECTION INPUT ;
    USE SIGNAL ;
    PORT
      LAYER M4 ;
        RECT  414.636 113.376 414.72 113.4 ;
    END
  END c_i[347]
  PIN c_i[348]
    DIRECTION INPUT ;
    USE SIGNAL ;
    PORT
      LAYER M4 ;
        RECT  414.636 113.52 414.72 113.544 ;
    END
  END c_i[348]
  PIN c_i[349]
    DIRECTION INPUT ;
    USE SIGNAL ;
    PORT
      LAYER M4 ;
        RECT  414.636 113.664 414.72 113.688 ;
    END
  END c_i[349]
  PIN c_i[34]
    DIRECTION INPUT ;
    USE SIGNAL ;
    PORT
      LAYER M4 ;
        RECT  414.636 68.304 414.72 68.328 ;
    END
  END c_i[34]
  PIN c_i[350]
    DIRECTION INPUT ;
    USE SIGNAL ;
    PORT
      LAYER M4 ;
        RECT  414.636 113.808 414.72 113.832 ;
    END
  END c_i[350]
  PIN c_i[351]
    DIRECTION INPUT ;
    USE SIGNAL ;
    PORT
      LAYER M4 ;
        RECT  414.636 113.952 414.72 113.976 ;
    END
  END c_i[351]
  PIN c_i[352]
    DIRECTION INPUT ;
    USE SIGNAL ;
    PORT
      LAYER M4 ;
        RECT  414.636 114.096 414.72 114.12 ;
    END
  END c_i[352]
  PIN c_i[353]
    DIRECTION INPUT ;
    USE SIGNAL ;
    PORT
      LAYER M4 ;
        RECT  414.636 114.24 414.72 114.264 ;
    END
  END c_i[353]
  PIN c_i[354]
    DIRECTION INPUT ;
    USE SIGNAL ;
    PORT
      LAYER M4 ;
        RECT  414.636 114.384 414.72 114.408 ;
    END
  END c_i[354]
  PIN c_i[355]
    DIRECTION INPUT ;
    USE SIGNAL ;
    PORT
      LAYER M4 ;
        RECT  414.636 114.528 414.72 114.552 ;
    END
  END c_i[355]
  PIN c_i[356]
    DIRECTION INPUT ;
    USE SIGNAL ;
    PORT
      LAYER M4 ;
        RECT  414.636 114.672 414.72 114.696 ;
    END
  END c_i[356]
  PIN c_i[357]
    DIRECTION INPUT ;
    USE SIGNAL ;
    PORT
      LAYER M4 ;
        RECT  414.636 114.816 414.72 114.84 ;
    END
  END c_i[357]
  PIN c_i[358]
    DIRECTION INPUT ;
    USE SIGNAL ;
    PORT
      LAYER M4 ;
        RECT  414.636 114.96 414.72 114.984 ;
    END
  END c_i[358]
  PIN c_i[359]
    DIRECTION INPUT ;
    USE SIGNAL ;
    PORT
      LAYER M4 ;
        RECT  414.636 115.104 414.72 115.128 ;
    END
  END c_i[359]
  PIN c_i[35]
    DIRECTION INPUT ;
    USE SIGNAL ;
    PORT
      LAYER M4 ;
        RECT  414.636 68.448 414.72 68.472 ;
    END
  END c_i[35]
  PIN c_i[360]
    DIRECTION INPUT ;
    USE SIGNAL ;
    PORT
      LAYER M4 ;
        RECT  414.636 115.248 414.72 115.272 ;
    END
  END c_i[360]
  PIN c_i[361]
    DIRECTION INPUT ;
    USE SIGNAL ;
    PORT
      LAYER M4 ;
        RECT  414.636 115.392 414.72 115.416 ;
    END
  END c_i[361]
  PIN c_i[362]
    DIRECTION INPUT ;
    USE SIGNAL ;
    PORT
      LAYER M4 ;
        RECT  414.636 115.536 414.72 115.56 ;
    END
  END c_i[362]
  PIN c_i[363]
    DIRECTION INPUT ;
    USE SIGNAL ;
    PORT
      LAYER M4 ;
        RECT  414.636 115.68 414.72 115.704 ;
    END
  END c_i[363]
  PIN c_i[364]
    DIRECTION INPUT ;
    USE SIGNAL ;
    PORT
      LAYER M4 ;
        RECT  414.636 115.824 414.72 115.848 ;
    END
  END c_i[364]
  PIN c_i[365]
    DIRECTION INPUT ;
    USE SIGNAL ;
    PORT
      LAYER M4 ;
        RECT  414.636 115.968 414.72 115.992 ;
    END
  END c_i[365]
  PIN c_i[366]
    DIRECTION INPUT ;
    USE SIGNAL ;
    PORT
      LAYER M4 ;
        RECT  414.636 116.112 414.72 116.136 ;
    END
  END c_i[366]
  PIN c_i[367]
    DIRECTION INPUT ;
    USE SIGNAL ;
    PORT
      LAYER M4 ;
        RECT  414.636 116.256 414.72 116.28 ;
    END
  END c_i[367]
  PIN c_i[368]
    DIRECTION INPUT ;
    USE SIGNAL ;
    PORT
      LAYER M4 ;
        RECT  414.636 116.4 414.72 116.424 ;
    END
  END c_i[368]
  PIN c_i[369]
    DIRECTION INPUT ;
    USE SIGNAL ;
    PORT
      LAYER M4 ;
        RECT  414.636 116.544 414.72 116.568 ;
    END
  END c_i[369]
  PIN c_i[36]
    DIRECTION INPUT ;
    USE SIGNAL ;
    PORT
      LAYER M4 ;
        RECT  414.636 68.592 414.72 68.616 ;
    END
  END c_i[36]
  PIN c_i[370]
    DIRECTION INPUT ;
    USE SIGNAL ;
    PORT
      LAYER M4 ;
        RECT  414.636 116.688 414.72 116.712 ;
    END
  END c_i[370]
  PIN c_i[371]
    DIRECTION INPUT ;
    USE SIGNAL ;
    PORT
      LAYER M4 ;
        RECT  414.636 116.832 414.72 116.856 ;
    END
  END c_i[371]
  PIN c_i[372]
    DIRECTION INPUT ;
    USE SIGNAL ;
    PORT
      LAYER M4 ;
        RECT  414.636 116.976 414.72 117 ;
    END
  END c_i[372]
  PIN c_i[373]
    DIRECTION INPUT ;
    USE SIGNAL ;
    PORT
      LAYER M4 ;
        RECT  414.636 117.12 414.72 117.144 ;
    END
  END c_i[373]
  PIN c_i[374]
    DIRECTION INPUT ;
    USE SIGNAL ;
    PORT
      LAYER M4 ;
        RECT  414.636 117.264 414.72 117.288 ;
    END
  END c_i[374]
  PIN c_i[375]
    DIRECTION INPUT ;
    USE SIGNAL ;
    PORT
      LAYER M4 ;
        RECT  414.636 117.408 414.72 117.432 ;
    END
  END c_i[375]
  PIN c_i[376]
    DIRECTION INPUT ;
    USE SIGNAL ;
    PORT
      LAYER M4 ;
        RECT  414.636 117.552 414.72 117.576 ;
    END
  END c_i[376]
  PIN c_i[377]
    DIRECTION INPUT ;
    USE SIGNAL ;
    PORT
      LAYER M4 ;
        RECT  414.636 117.696 414.72 117.72 ;
    END
  END c_i[377]
  PIN c_i[378]
    DIRECTION INPUT ;
    USE SIGNAL ;
    PORT
      LAYER M4 ;
        RECT  414.636 117.84 414.72 117.864 ;
    END
  END c_i[378]
  PIN c_i[379]
    DIRECTION INPUT ;
    USE SIGNAL ;
    PORT
      LAYER M4 ;
        RECT  414.636 117.984 414.72 118.008 ;
    END
  END c_i[379]
  PIN c_i[37]
    DIRECTION INPUT ;
    USE SIGNAL ;
    PORT
      LAYER M4 ;
        RECT  414.636 68.736 414.72 68.76 ;
    END
  END c_i[37]
  PIN c_i[380]
    DIRECTION INPUT ;
    USE SIGNAL ;
    PORT
      LAYER M4 ;
        RECT  414.636 118.128 414.72 118.152 ;
    END
  END c_i[380]
  PIN c_i[381]
    DIRECTION INPUT ;
    USE SIGNAL ;
    PORT
      LAYER M4 ;
        RECT  414.636 118.272 414.72 118.296 ;
    END
  END c_i[381]
  PIN c_i[382]
    DIRECTION INPUT ;
    USE SIGNAL ;
    PORT
      LAYER M4 ;
        RECT  414.636 118.416 414.72 118.44 ;
    END
  END c_i[382]
  PIN c_i[383]
    DIRECTION INPUT ;
    USE SIGNAL ;
    PORT
      LAYER M4 ;
        RECT  414.636 118.56 414.72 118.584 ;
    END
  END c_i[383]
  PIN c_i[384]
    DIRECTION INPUT ;
    USE SIGNAL ;
    PORT
      LAYER M4 ;
        RECT  414.636 118.704 414.72 118.728 ;
    END
  END c_i[384]
  PIN c_i[385]
    DIRECTION INPUT ;
    USE SIGNAL ;
    PORT
      LAYER M4 ;
        RECT  414.636 118.848 414.72 118.872 ;
    END
  END c_i[385]
  PIN c_i[386]
    DIRECTION INPUT ;
    USE SIGNAL ;
    PORT
      LAYER M4 ;
        RECT  414.636 118.992 414.72 119.016 ;
    END
  END c_i[386]
  PIN c_i[387]
    DIRECTION INPUT ;
    USE SIGNAL ;
    PORT
      LAYER M4 ;
        RECT  414.636 119.136 414.72 119.16 ;
    END
  END c_i[387]
  PIN c_i[388]
    DIRECTION INPUT ;
    USE SIGNAL ;
    PORT
      LAYER M4 ;
        RECT  414.636 119.28 414.72 119.304 ;
    END
  END c_i[388]
  PIN c_i[389]
    DIRECTION INPUT ;
    USE SIGNAL ;
    PORT
      LAYER M4 ;
        RECT  414.636 119.424 414.72 119.448 ;
    END
  END c_i[389]
  PIN c_i[38]
    DIRECTION INPUT ;
    USE SIGNAL ;
    PORT
      LAYER M4 ;
        RECT  414.636 68.88 414.72 68.904 ;
    END
  END c_i[38]
  PIN c_i[390]
    DIRECTION INPUT ;
    USE SIGNAL ;
    PORT
      LAYER M4 ;
        RECT  414.636 119.568 414.72 119.592 ;
    END
  END c_i[390]
  PIN c_i[391]
    DIRECTION INPUT ;
    USE SIGNAL ;
    PORT
      LAYER M4 ;
        RECT  414.636 119.712 414.72 119.736 ;
    END
  END c_i[391]
  PIN c_i[392]
    DIRECTION INPUT ;
    USE SIGNAL ;
    PORT
      LAYER M4 ;
        RECT  414.636 119.856 414.72 119.88 ;
    END
  END c_i[392]
  PIN c_i[393]
    DIRECTION INPUT ;
    USE SIGNAL ;
    PORT
      LAYER M4 ;
        RECT  414.636 120 414.72 120.024 ;
    END
  END c_i[393]
  PIN c_i[394]
    DIRECTION INPUT ;
    USE SIGNAL ;
    PORT
      LAYER M4 ;
        RECT  414.636 120.144 414.72 120.168 ;
    END
  END c_i[394]
  PIN c_i[395]
    DIRECTION INPUT ;
    USE SIGNAL ;
    PORT
      LAYER M4 ;
        RECT  414.636 120.288 414.72 120.312 ;
    END
  END c_i[395]
  PIN c_i[396]
    DIRECTION INPUT ;
    USE SIGNAL ;
    PORT
      LAYER M4 ;
        RECT  414.636 120.432 414.72 120.456 ;
    END
  END c_i[396]
  PIN c_i[397]
    DIRECTION INPUT ;
    USE SIGNAL ;
    PORT
      LAYER M4 ;
        RECT  414.636 120.576 414.72 120.6 ;
    END
  END c_i[397]
  PIN c_i[398]
    DIRECTION INPUT ;
    USE SIGNAL ;
    PORT
      LAYER M4 ;
        RECT  414.636 120.72 414.72 120.744 ;
    END
  END c_i[398]
  PIN c_i[399]
    DIRECTION INPUT ;
    USE SIGNAL ;
    PORT
      LAYER M4 ;
        RECT  414.636 120.864 414.72 120.888 ;
    END
  END c_i[399]
  PIN c_i[39]
    DIRECTION INPUT ;
    USE SIGNAL ;
    PORT
      LAYER M4 ;
        RECT  414.636 69.024 414.72 69.048 ;
    END
  END c_i[39]
  PIN c_i[3]
    DIRECTION INPUT ;
    USE SIGNAL ;
    PORT
      LAYER M4 ;
        RECT  414.636 63.84 414.72 63.864 ;
    END
  END c_i[3]
  PIN c_i[400]
    DIRECTION INPUT ;
    USE SIGNAL ;
    PORT
      LAYER M4 ;
        RECT  414.636 121.008 414.72 121.032 ;
    END
  END c_i[400]
  PIN c_i[401]
    DIRECTION INPUT ;
    USE SIGNAL ;
    PORT
      LAYER M4 ;
        RECT  414.636 121.152 414.72 121.176 ;
    END
  END c_i[401]
  PIN c_i[402]
    DIRECTION INPUT ;
    USE SIGNAL ;
    PORT
      LAYER M4 ;
        RECT  414.636 121.296 414.72 121.32 ;
    END
  END c_i[402]
  PIN c_i[403]
    DIRECTION INPUT ;
    USE SIGNAL ;
    PORT
      LAYER M4 ;
        RECT  414.636 121.44 414.72 121.464 ;
    END
  END c_i[403]
  PIN c_i[404]
    DIRECTION INPUT ;
    USE SIGNAL ;
    PORT
      LAYER M4 ;
        RECT  414.636 121.584 414.72 121.608 ;
    END
  END c_i[404]
  PIN c_i[405]
    DIRECTION INPUT ;
    USE SIGNAL ;
    PORT
      LAYER M4 ;
        RECT  414.636 121.728 414.72 121.752 ;
    END
  END c_i[405]
  PIN c_i[406]
    DIRECTION INPUT ;
    USE SIGNAL ;
    PORT
      LAYER M4 ;
        RECT  414.636 121.872 414.72 121.896 ;
    END
  END c_i[406]
  PIN c_i[407]
    DIRECTION INPUT ;
    USE SIGNAL ;
    PORT
      LAYER M4 ;
        RECT  414.636 122.016 414.72 122.04 ;
    END
  END c_i[407]
  PIN c_i[408]
    DIRECTION INPUT ;
    USE SIGNAL ;
    PORT
      LAYER M4 ;
        RECT  414.636 122.16 414.72 122.184 ;
    END
  END c_i[408]
  PIN c_i[409]
    DIRECTION INPUT ;
    USE SIGNAL ;
    PORT
      LAYER M4 ;
        RECT  414.636 122.304 414.72 122.328 ;
    END
  END c_i[409]
  PIN c_i[40]
    DIRECTION INPUT ;
    USE SIGNAL ;
    PORT
      LAYER M4 ;
        RECT  414.636 69.168 414.72 69.192 ;
    END
  END c_i[40]
  PIN c_i[410]
    DIRECTION INPUT ;
    USE SIGNAL ;
    PORT
      LAYER M4 ;
        RECT  414.636 122.448 414.72 122.472 ;
    END
  END c_i[410]
  PIN c_i[411]
    DIRECTION INPUT ;
    USE SIGNAL ;
    PORT
      LAYER M4 ;
        RECT  414.636 122.592 414.72 122.616 ;
    END
  END c_i[411]
  PIN c_i[412]
    DIRECTION INPUT ;
    USE SIGNAL ;
    PORT
      LAYER M4 ;
        RECT  414.636 122.736 414.72 122.76 ;
    END
  END c_i[412]
  PIN c_i[413]
    DIRECTION INPUT ;
    USE SIGNAL ;
    PORT
      LAYER M4 ;
        RECT  414.636 122.88 414.72 122.904 ;
    END
  END c_i[413]
  PIN c_i[414]
    DIRECTION INPUT ;
    USE SIGNAL ;
    PORT
      LAYER M4 ;
        RECT  414.636 123.024 414.72 123.048 ;
    END
  END c_i[414]
  PIN c_i[415]
    DIRECTION INPUT ;
    USE SIGNAL ;
    PORT
      LAYER M4 ;
        RECT  414.636 123.168 414.72 123.192 ;
    END
  END c_i[415]
  PIN c_i[416]
    DIRECTION INPUT ;
    USE SIGNAL ;
    PORT
      LAYER M4 ;
        RECT  414.636 123.312 414.72 123.336 ;
    END
  END c_i[416]
  PIN c_i[417]
    DIRECTION INPUT ;
    USE SIGNAL ;
    PORT
      LAYER M4 ;
        RECT  414.636 123.456 414.72 123.48 ;
    END
  END c_i[417]
  PIN c_i[418]
    DIRECTION INPUT ;
    USE SIGNAL ;
    PORT
      LAYER M4 ;
        RECT  414.636 123.6 414.72 123.624 ;
    END
  END c_i[418]
  PIN c_i[419]
    DIRECTION INPUT ;
    USE SIGNAL ;
    PORT
      LAYER M4 ;
        RECT  414.636 123.744 414.72 123.768 ;
    END
  END c_i[419]
  PIN c_i[41]
    DIRECTION INPUT ;
    USE SIGNAL ;
    PORT
      LAYER M4 ;
        RECT  414.636 69.312 414.72 69.336 ;
    END
  END c_i[41]
  PIN c_i[420]
    DIRECTION INPUT ;
    USE SIGNAL ;
    PORT
      LAYER M4 ;
        RECT  414.636 123.888 414.72 123.912 ;
    END
  END c_i[420]
  PIN c_i[421]
    DIRECTION INPUT ;
    USE SIGNAL ;
    PORT
      LAYER M4 ;
        RECT  414.636 124.032 414.72 124.056 ;
    END
  END c_i[421]
  PIN c_i[422]
    DIRECTION INPUT ;
    USE SIGNAL ;
    PORT
      LAYER M4 ;
        RECT  414.636 124.176 414.72 124.2 ;
    END
  END c_i[422]
  PIN c_i[423]
    DIRECTION INPUT ;
    USE SIGNAL ;
    PORT
      LAYER M4 ;
        RECT  414.636 124.32 414.72 124.344 ;
    END
  END c_i[423]
  PIN c_i[424]
    DIRECTION INPUT ;
    USE SIGNAL ;
    PORT
      LAYER M4 ;
        RECT  414.636 124.464 414.72 124.488 ;
    END
  END c_i[424]
  PIN c_i[425]
    DIRECTION INPUT ;
    USE SIGNAL ;
    PORT
      LAYER M4 ;
        RECT  414.636 124.608 414.72 124.632 ;
    END
  END c_i[425]
  PIN c_i[426]
    DIRECTION INPUT ;
    USE SIGNAL ;
    PORT
      LAYER M4 ;
        RECT  414.636 124.752 414.72 124.776 ;
    END
  END c_i[426]
  PIN c_i[427]
    DIRECTION INPUT ;
    USE SIGNAL ;
    PORT
      LAYER M4 ;
        RECT  414.636 124.896 414.72 124.92 ;
    END
  END c_i[427]
  PIN c_i[428]
    DIRECTION INPUT ;
    USE SIGNAL ;
    PORT
      LAYER M4 ;
        RECT  414.636 125.04 414.72 125.064 ;
    END
  END c_i[428]
  PIN c_i[429]
    DIRECTION INPUT ;
    USE SIGNAL ;
    PORT
      LAYER M4 ;
        RECT  414.636 125.184 414.72 125.208 ;
    END
  END c_i[429]
  PIN c_i[42]
    DIRECTION INPUT ;
    USE SIGNAL ;
    PORT
      LAYER M4 ;
        RECT  414.636 69.456 414.72 69.48 ;
    END
  END c_i[42]
  PIN c_i[430]
    DIRECTION INPUT ;
    USE SIGNAL ;
    PORT
      LAYER M4 ;
        RECT  414.636 125.328 414.72 125.352 ;
    END
  END c_i[430]
  PIN c_i[431]
    DIRECTION INPUT ;
    USE SIGNAL ;
    PORT
      LAYER M4 ;
        RECT  414.636 125.472 414.72 125.496 ;
    END
  END c_i[431]
  PIN c_i[432]
    DIRECTION INPUT ;
    USE SIGNAL ;
    PORT
      LAYER M4 ;
        RECT  414.636 125.616 414.72 125.64 ;
    END
  END c_i[432]
  PIN c_i[433]
    DIRECTION INPUT ;
    USE SIGNAL ;
    PORT
      LAYER M4 ;
        RECT  414.636 125.76 414.72 125.784 ;
    END
  END c_i[433]
  PIN c_i[434]
    DIRECTION INPUT ;
    USE SIGNAL ;
    PORT
      LAYER M4 ;
        RECT  414.636 125.904 414.72 125.928 ;
    END
  END c_i[434]
  PIN c_i[435]
    DIRECTION INPUT ;
    USE SIGNAL ;
    PORT
      LAYER M4 ;
        RECT  414.636 126.048 414.72 126.072 ;
    END
  END c_i[435]
  PIN c_i[436]
    DIRECTION INPUT ;
    USE SIGNAL ;
    PORT
      LAYER M4 ;
        RECT  414.636 126.192 414.72 126.216 ;
    END
  END c_i[436]
  PIN c_i[437]
    DIRECTION INPUT ;
    USE SIGNAL ;
    PORT
      LAYER M4 ;
        RECT  414.636 126.336 414.72 126.36 ;
    END
  END c_i[437]
  PIN c_i[438]
    DIRECTION INPUT ;
    USE SIGNAL ;
    PORT
      LAYER M4 ;
        RECT  414.636 126.48 414.72 126.504 ;
    END
  END c_i[438]
  PIN c_i[439]
    DIRECTION INPUT ;
    USE SIGNAL ;
    PORT
      LAYER M4 ;
        RECT  414.636 126.624 414.72 126.648 ;
    END
  END c_i[439]
  PIN c_i[43]
    DIRECTION INPUT ;
    USE SIGNAL ;
    PORT
      LAYER M4 ;
        RECT  414.636 69.6 414.72 69.624 ;
    END
  END c_i[43]
  PIN c_i[440]
    DIRECTION INPUT ;
    USE SIGNAL ;
    PORT
      LAYER M4 ;
        RECT  414.636 126.768 414.72 126.792 ;
    END
  END c_i[440]
  PIN c_i[441]
    DIRECTION INPUT ;
    USE SIGNAL ;
    PORT
      LAYER M4 ;
        RECT  414.636 126.912 414.72 126.936 ;
    END
  END c_i[441]
  PIN c_i[442]
    DIRECTION INPUT ;
    USE SIGNAL ;
    PORT
      LAYER M4 ;
        RECT  414.636 127.056 414.72 127.08 ;
    END
  END c_i[442]
  PIN c_i[443]
    DIRECTION INPUT ;
    USE SIGNAL ;
    PORT
      LAYER M4 ;
        RECT  414.636 127.2 414.72 127.224 ;
    END
  END c_i[443]
  PIN c_i[444]
    DIRECTION INPUT ;
    USE SIGNAL ;
    PORT
      LAYER M4 ;
        RECT  414.636 127.344 414.72 127.368 ;
    END
  END c_i[444]
  PIN c_i[445]
    DIRECTION INPUT ;
    USE SIGNAL ;
    PORT
      LAYER M4 ;
        RECT  414.636 127.488 414.72 127.512 ;
    END
  END c_i[445]
  PIN c_i[446]
    DIRECTION INPUT ;
    USE SIGNAL ;
    PORT
      LAYER M4 ;
        RECT  414.636 127.632 414.72 127.656 ;
    END
  END c_i[446]
  PIN c_i[447]
    DIRECTION INPUT ;
    USE SIGNAL ;
    PORT
      LAYER M4 ;
        RECT  414.636 127.776 414.72 127.8 ;
    END
  END c_i[447]
  PIN c_i[448]
    DIRECTION INPUT ;
    USE SIGNAL ;
    PORT
      LAYER M4 ;
        RECT  414.636 127.92 414.72 127.944 ;
    END
  END c_i[448]
  PIN c_i[449]
    DIRECTION INPUT ;
    USE SIGNAL ;
    PORT
      LAYER M4 ;
        RECT  414.636 128.064 414.72 128.088 ;
    END
  END c_i[449]
  PIN c_i[44]
    DIRECTION INPUT ;
    USE SIGNAL ;
    PORT
      LAYER M4 ;
        RECT  414.636 69.744 414.72 69.768 ;
    END
  END c_i[44]
  PIN c_i[450]
    DIRECTION INPUT ;
    USE SIGNAL ;
    PORT
      LAYER M4 ;
        RECT  414.636 128.208 414.72 128.232 ;
    END
  END c_i[450]
  PIN c_i[451]
    DIRECTION INPUT ;
    USE SIGNAL ;
    PORT
      LAYER M4 ;
        RECT  414.636 128.352 414.72 128.376 ;
    END
  END c_i[451]
  PIN c_i[452]
    DIRECTION INPUT ;
    USE SIGNAL ;
    PORT
      LAYER M4 ;
        RECT  414.636 128.496 414.72 128.52 ;
    END
  END c_i[452]
  PIN c_i[453]
    DIRECTION INPUT ;
    USE SIGNAL ;
    PORT
      LAYER M4 ;
        RECT  414.636 128.64 414.72 128.664 ;
    END
  END c_i[453]
  PIN c_i[454]
    DIRECTION INPUT ;
    USE SIGNAL ;
    PORT
      LAYER M4 ;
        RECT  414.636 128.784 414.72 128.808 ;
    END
  END c_i[454]
  PIN c_i[455]
    DIRECTION INPUT ;
    USE SIGNAL ;
    PORT
      LAYER M4 ;
        RECT  414.636 128.928 414.72 128.952 ;
    END
  END c_i[455]
  PIN c_i[456]
    DIRECTION INPUT ;
    USE SIGNAL ;
    PORT
      LAYER M4 ;
        RECT  414.636 129.072 414.72 129.096 ;
    END
  END c_i[456]
  PIN c_i[457]
    DIRECTION INPUT ;
    USE SIGNAL ;
    PORT
      LAYER M4 ;
        RECT  414.636 129.216 414.72 129.24 ;
    END
  END c_i[457]
  PIN c_i[458]
    DIRECTION INPUT ;
    USE SIGNAL ;
    PORT
      LAYER M4 ;
        RECT  414.636 129.36 414.72 129.384 ;
    END
  END c_i[458]
  PIN c_i[459]
    DIRECTION INPUT ;
    USE SIGNAL ;
    PORT
      LAYER M4 ;
        RECT  414.636 129.504 414.72 129.528 ;
    END
  END c_i[459]
  PIN c_i[45]
    DIRECTION INPUT ;
    USE SIGNAL ;
    PORT
      LAYER M4 ;
        RECT  414.636 69.888 414.72 69.912 ;
    END
  END c_i[45]
  PIN c_i[460]
    DIRECTION INPUT ;
    USE SIGNAL ;
    PORT
      LAYER M4 ;
        RECT  414.636 129.648 414.72 129.672 ;
    END
  END c_i[460]
  PIN c_i[461]
    DIRECTION INPUT ;
    USE SIGNAL ;
    PORT
      LAYER M4 ;
        RECT  414.636 129.792 414.72 129.816 ;
    END
  END c_i[461]
  PIN c_i[462]
    DIRECTION INPUT ;
    USE SIGNAL ;
    PORT
      LAYER M4 ;
        RECT  414.636 129.936 414.72 129.96 ;
    END
  END c_i[462]
  PIN c_i[463]
    DIRECTION INPUT ;
    USE SIGNAL ;
    PORT
      LAYER M4 ;
        RECT  414.636 130.08 414.72 130.104 ;
    END
  END c_i[463]
  PIN c_i[464]
    DIRECTION INPUT ;
    USE SIGNAL ;
    PORT
      LAYER M4 ;
        RECT  414.636 130.224 414.72 130.248 ;
    END
  END c_i[464]
  PIN c_i[465]
    DIRECTION INPUT ;
    USE SIGNAL ;
    PORT
      LAYER M4 ;
        RECT  414.636 130.368 414.72 130.392 ;
    END
  END c_i[465]
  PIN c_i[466]
    DIRECTION INPUT ;
    USE SIGNAL ;
    PORT
      LAYER M4 ;
        RECT  414.636 130.512 414.72 130.536 ;
    END
  END c_i[466]
  PIN c_i[467]
    DIRECTION INPUT ;
    USE SIGNAL ;
    PORT
      LAYER M4 ;
        RECT  414.636 130.656 414.72 130.68 ;
    END
  END c_i[467]
  PIN c_i[468]
    DIRECTION INPUT ;
    USE SIGNAL ;
    PORT
      LAYER M4 ;
        RECT  414.636 130.8 414.72 130.824 ;
    END
  END c_i[468]
  PIN c_i[469]
    DIRECTION INPUT ;
    USE SIGNAL ;
    PORT
      LAYER M4 ;
        RECT  414.636 130.944 414.72 130.968 ;
    END
  END c_i[469]
  PIN c_i[46]
    DIRECTION INPUT ;
    USE SIGNAL ;
    PORT
      LAYER M4 ;
        RECT  414.636 70.032 414.72 70.056 ;
    END
  END c_i[46]
  PIN c_i[470]
    DIRECTION INPUT ;
    USE SIGNAL ;
    PORT
      LAYER M4 ;
        RECT  414.636 131.088 414.72 131.112 ;
    END
  END c_i[470]
  PIN c_i[471]
    DIRECTION INPUT ;
    USE SIGNAL ;
    PORT
      LAYER M4 ;
        RECT  414.636 131.232 414.72 131.256 ;
    END
  END c_i[471]
  PIN c_i[472]
    DIRECTION INPUT ;
    USE SIGNAL ;
    PORT
      LAYER M4 ;
        RECT  414.636 131.376 414.72 131.4 ;
    END
  END c_i[472]
  PIN c_i[473]
    DIRECTION INPUT ;
    USE SIGNAL ;
    PORT
      LAYER M4 ;
        RECT  414.636 131.52 414.72 131.544 ;
    END
  END c_i[473]
  PIN c_i[474]
    DIRECTION INPUT ;
    USE SIGNAL ;
    PORT
      LAYER M4 ;
        RECT  414.636 131.664 414.72 131.688 ;
    END
  END c_i[474]
  PIN c_i[475]
    DIRECTION INPUT ;
    USE SIGNAL ;
    PORT
      LAYER M4 ;
        RECT  414.636 131.808 414.72 131.832 ;
    END
  END c_i[475]
  PIN c_i[476]
    DIRECTION INPUT ;
    USE SIGNAL ;
    PORT
      LAYER M4 ;
        RECT  414.636 131.952 414.72 131.976 ;
    END
  END c_i[476]
  PIN c_i[477]
    DIRECTION INPUT ;
    USE SIGNAL ;
    PORT
      LAYER M4 ;
        RECT  414.636 132.096 414.72 132.12 ;
    END
  END c_i[477]
  PIN c_i[478]
    DIRECTION INPUT ;
    USE SIGNAL ;
    PORT
      LAYER M4 ;
        RECT  414.636 132.24 414.72 132.264 ;
    END
  END c_i[478]
  PIN c_i[479]
    DIRECTION INPUT ;
    USE SIGNAL ;
    PORT
      LAYER M4 ;
        RECT  414.636 132.384 414.72 132.408 ;
    END
  END c_i[479]
  PIN c_i[47]
    DIRECTION INPUT ;
    USE SIGNAL ;
    PORT
      LAYER M4 ;
        RECT  414.636 70.176 414.72 70.2 ;
    END
  END c_i[47]
  PIN c_i[480]
    DIRECTION INPUT ;
    USE SIGNAL ;
    PORT
      LAYER M4 ;
        RECT  414.636 132.528 414.72 132.552 ;
    END
  END c_i[480]
  PIN c_i[481]
    DIRECTION INPUT ;
    USE SIGNAL ;
    PORT
      LAYER M4 ;
        RECT  414.636 132.672 414.72 132.696 ;
    END
  END c_i[481]
  PIN c_i[482]
    DIRECTION INPUT ;
    USE SIGNAL ;
    PORT
      LAYER M4 ;
        RECT  414.636 132.816 414.72 132.84 ;
    END
  END c_i[482]
  PIN c_i[483]
    DIRECTION INPUT ;
    USE SIGNAL ;
    PORT
      LAYER M4 ;
        RECT  414.636 132.96 414.72 132.984 ;
    END
  END c_i[483]
  PIN c_i[484]
    DIRECTION INPUT ;
    USE SIGNAL ;
    PORT
      LAYER M4 ;
        RECT  414.636 133.104 414.72 133.128 ;
    END
  END c_i[484]
  PIN c_i[485]
    DIRECTION INPUT ;
    USE SIGNAL ;
    PORT
      LAYER M4 ;
        RECT  414.636 133.248 414.72 133.272 ;
    END
  END c_i[485]
  PIN c_i[486]
    DIRECTION INPUT ;
    USE SIGNAL ;
    PORT
      LAYER M4 ;
        RECT  414.636 133.392 414.72 133.416 ;
    END
  END c_i[486]
  PIN c_i[487]
    DIRECTION INPUT ;
    USE SIGNAL ;
    PORT
      LAYER M4 ;
        RECT  414.636 133.536 414.72 133.56 ;
    END
  END c_i[487]
  PIN c_i[488]
    DIRECTION INPUT ;
    USE SIGNAL ;
    PORT
      LAYER M4 ;
        RECT  414.636 133.68 414.72 133.704 ;
    END
  END c_i[488]
  PIN c_i[489]
    DIRECTION INPUT ;
    USE SIGNAL ;
    PORT
      LAYER M4 ;
        RECT  414.636 133.824 414.72 133.848 ;
    END
  END c_i[489]
  PIN c_i[48]
    DIRECTION INPUT ;
    USE SIGNAL ;
    PORT
      LAYER M4 ;
        RECT  414.636 70.32 414.72 70.344 ;
    END
  END c_i[48]
  PIN c_i[490]
    DIRECTION INPUT ;
    USE SIGNAL ;
    PORT
      LAYER M4 ;
        RECT  414.636 133.968 414.72 133.992 ;
    END
  END c_i[490]
  PIN c_i[491]
    DIRECTION INPUT ;
    USE SIGNAL ;
    PORT
      LAYER M4 ;
        RECT  414.636 134.112 414.72 134.136 ;
    END
  END c_i[491]
  PIN c_i[492]
    DIRECTION INPUT ;
    USE SIGNAL ;
    PORT
      LAYER M4 ;
        RECT  414.636 134.256 414.72 134.28 ;
    END
  END c_i[492]
  PIN c_i[493]
    DIRECTION INPUT ;
    USE SIGNAL ;
    PORT
      LAYER M4 ;
        RECT  414.636 134.4 414.72 134.424 ;
    END
  END c_i[493]
  PIN c_i[494]
    DIRECTION INPUT ;
    USE SIGNAL ;
    PORT
      LAYER M4 ;
        RECT  414.636 134.544 414.72 134.568 ;
    END
  END c_i[494]
  PIN c_i[495]
    DIRECTION INPUT ;
    USE SIGNAL ;
    PORT
      LAYER M4 ;
        RECT  414.636 134.688 414.72 134.712 ;
    END
  END c_i[495]
  PIN c_i[496]
    DIRECTION INPUT ;
    USE SIGNAL ;
    PORT
      LAYER M4 ;
        RECT  414.636 134.832 414.72 134.856 ;
    END
  END c_i[496]
  PIN c_i[497]
    DIRECTION INPUT ;
    USE SIGNAL ;
    PORT
      LAYER M4 ;
        RECT  414.636 134.976 414.72 135 ;
    END
  END c_i[497]
  PIN c_i[498]
    DIRECTION INPUT ;
    USE SIGNAL ;
    PORT
      LAYER M4 ;
        RECT  414.636 135.12 414.72 135.144 ;
    END
  END c_i[498]
  PIN c_i[499]
    DIRECTION INPUT ;
    USE SIGNAL ;
    PORT
      LAYER M4 ;
        RECT  414.636 135.264 414.72 135.288 ;
    END
  END c_i[499]
  PIN c_i[49]
    DIRECTION INPUT ;
    USE SIGNAL ;
    PORT
      LAYER M4 ;
        RECT  414.636 70.464 414.72 70.488 ;
    END
  END c_i[49]
  PIN c_i[4]
    DIRECTION INPUT ;
    USE SIGNAL ;
    PORT
      LAYER M4 ;
        RECT  414.636 63.984 414.72 64.008 ;
    END
  END c_i[4]
  PIN c_i[500]
    DIRECTION INPUT ;
    USE SIGNAL ;
    PORT
      LAYER M4 ;
        RECT  414.636 135.408 414.72 135.432 ;
    END
  END c_i[500]
  PIN c_i[501]
    DIRECTION INPUT ;
    USE SIGNAL ;
    PORT
      LAYER M4 ;
        RECT  414.636 135.552 414.72 135.576 ;
    END
  END c_i[501]
  PIN c_i[502]
    DIRECTION INPUT ;
    USE SIGNAL ;
    PORT
      LAYER M4 ;
        RECT  414.636 135.696 414.72 135.72 ;
    END
  END c_i[502]
  PIN c_i[503]
    DIRECTION INPUT ;
    USE SIGNAL ;
    PORT
      LAYER M4 ;
        RECT  414.636 135.84 414.72 135.864 ;
    END
  END c_i[503]
  PIN c_i[504]
    DIRECTION INPUT ;
    USE SIGNAL ;
    PORT
      LAYER M4 ;
        RECT  414.636 135.984 414.72 136.008 ;
    END
  END c_i[504]
  PIN c_i[505]
    DIRECTION INPUT ;
    USE SIGNAL ;
    PORT
      LAYER M4 ;
        RECT  414.636 136.128 414.72 136.152 ;
    END
  END c_i[505]
  PIN c_i[506]
    DIRECTION INPUT ;
    USE SIGNAL ;
    PORT
      LAYER M4 ;
        RECT  414.636 136.272 414.72 136.296 ;
    END
  END c_i[506]
  PIN c_i[507]
    DIRECTION INPUT ;
    USE SIGNAL ;
    PORT
      LAYER M4 ;
        RECT  414.636 136.416 414.72 136.44 ;
    END
  END c_i[507]
  PIN c_i[508]
    DIRECTION INPUT ;
    USE SIGNAL ;
    PORT
      LAYER M4 ;
        RECT  414.636 136.56 414.72 136.584 ;
    END
  END c_i[508]
  PIN c_i[509]
    DIRECTION INPUT ;
    USE SIGNAL ;
    PORT
      LAYER M4 ;
        RECT  414.636 136.704 414.72 136.728 ;
    END
  END c_i[509]
  PIN c_i[50]
    DIRECTION INPUT ;
    USE SIGNAL ;
    PORT
      LAYER M4 ;
        RECT  414.636 70.608 414.72 70.632 ;
    END
  END c_i[50]
  PIN c_i[510]
    DIRECTION INPUT ;
    USE SIGNAL ;
    PORT
      LAYER M4 ;
        RECT  414.636 136.848 414.72 136.872 ;
    END
  END c_i[510]
  PIN c_i[511]
    DIRECTION INPUT ;
    USE SIGNAL ;
    PORT
      LAYER M4 ;
        RECT  414.636 136.992 414.72 137.016 ;
    END
  END c_i[511]
  PIN c_i[512]
    DIRECTION INPUT ;
    USE SIGNAL ;
    PORT
      LAYER M4 ;
        RECT  414.636 137.136 414.72 137.16 ;
    END
  END c_i[512]
  PIN c_i[513]
    DIRECTION INPUT ;
    USE SIGNAL ;
    PORT
      LAYER M4 ;
        RECT  414.636 137.28 414.72 137.304 ;
    END
  END c_i[513]
  PIN c_i[514]
    DIRECTION INPUT ;
    USE SIGNAL ;
    PORT
      LAYER M4 ;
        RECT  414.636 137.424 414.72 137.448 ;
    END
  END c_i[514]
  PIN c_i[515]
    DIRECTION INPUT ;
    USE SIGNAL ;
    PORT
      LAYER M4 ;
        RECT  414.636 137.568 414.72 137.592 ;
    END
  END c_i[515]
  PIN c_i[516]
    DIRECTION INPUT ;
    USE SIGNAL ;
    PORT
      LAYER M4 ;
        RECT  414.636 137.712 414.72 137.736 ;
    END
  END c_i[516]
  PIN c_i[517]
    DIRECTION INPUT ;
    USE SIGNAL ;
    PORT
      LAYER M4 ;
        RECT  414.636 137.856 414.72 137.88 ;
    END
  END c_i[517]
  PIN c_i[518]
    DIRECTION INPUT ;
    USE SIGNAL ;
    PORT
      LAYER M4 ;
        RECT  414.636 138 414.72 138.024 ;
    END
  END c_i[518]
  PIN c_i[519]
    DIRECTION INPUT ;
    USE SIGNAL ;
    PORT
      LAYER M4 ;
        RECT  414.636 138.144 414.72 138.168 ;
    END
  END c_i[519]
  PIN c_i[51]
    DIRECTION INPUT ;
    USE SIGNAL ;
    PORT
      LAYER M4 ;
        RECT  414.636 70.752 414.72 70.776 ;
    END
  END c_i[51]
  PIN c_i[520]
    DIRECTION INPUT ;
    USE SIGNAL ;
    PORT
      LAYER M4 ;
        RECT  414.636 138.288 414.72 138.312 ;
    END
  END c_i[520]
  PIN c_i[521]
    DIRECTION INPUT ;
    USE SIGNAL ;
    PORT
      LAYER M4 ;
        RECT  414.636 138.432 414.72 138.456 ;
    END
  END c_i[521]
  PIN c_i[522]
    DIRECTION INPUT ;
    USE SIGNAL ;
    PORT
      LAYER M4 ;
        RECT  414.636 138.576 414.72 138.6 ;
    END
  END c_i[522]
  PIN c_i[523]
    DIRECTION INPUT ;
    USE SIGNAL ;
    PORT
      LAYER M4 ;
        RECT  414.636 138.72 414.72 138.744 ;
    END
  END c_i[523]
  PIN c_i[524]
    DIRECTION INPUT ;
    USE SIGNAL ;
    PORT
      LAYER M4 ;
        RECT  414.636 138.864 414.72 138.888 ;
    END
  END c_i[524]
  PIN c_i[525]
    DIRECTION INPUT ;
    USE SIGNAL ;
    PORT
      LAYER M4 ;
        RECT  414.636 139.008 414.72 139.032 ;
    END
  END c_i[525]
  PIN c_i[526]
    DIRECTION INPUT ;
    USE SIGNAL ;
    PORT
      LAYER M4 ;
        RECT  414.636 139.152 414.72 139.176 ;
    END
  END c_i[526]
  PIN c_i[527]
    DIRECTION INPUT ;
    USE SIGNAL ;
    PORT
      LAYER M4 ;
        RECT  414.636 139.296 414.72 139.32 ;
    END
  END c_i[527]
  PIN c_i[528]
    DIRECTION INPUT ;
    USE SIGNAL ;
    PORT
      LAYER M4 ;
        RECT  414.636 139.44 414.72 139.464 ;
    END
  END c_i[528]
  PIN c_i[529]
    DIRECTION INPUT ;
    USE SIGNAL ;
    PORT
      LAYER M4 ;
        RECT  414.636 139.584 414.72 139.608 ;
    END
  END c_i[529]
  PIN c_i[52]
    DIRECTION INPUT ;
    USE SIGNAL ;
    PORT
      LAYER M4 ;
        RECT  414.636 70.896 414.72 70.92 ;
    END
  END c_i[52]
  PIN c_i[530]
    DIRECTION INPUT ;
    USE SIGNAL ;
    PORT
      LAYER M4 ;
        RECT  414.636 139.728 414.72 139.752 ;
    END
  END c_i[530]
  PIN c_i[531]
    DIRECTION INPUT ;
    USE SIGNAL ;
    PORT
      LAYER M4 ;
        RECT  414.636 139.872 414.72 139.896 ;
    END
  END c_i[531]
  PIN c_i[532]
    DIRECTION INPUT ;
    USE SIGNAL ;
    PORT
      LAYER M4 ;
        RECT  414.636 140.016 414.72 140.04 ;
    END
  END c_i[532]
  PIN c_i[533]
    DIRECTION INPUT ;
    USE SIGNAL ;
    PORT
      LAYER M4 ;
        RECT  414.636 140.16 414.72 140.184 ;
    END
  END c_i[533]
  PIN c_i[534]
    DIRECTION INPUT ;
    USE SIGNAL ;
    PORT
      LAYER M4 ;
        RECT  414.636 140.304 414.72 140.328 ;
    END
  END c_i[534]
  PIN c_i[535]
    DIRECTION INPUT ;
    USE SIGNAL ;
    PORT
      LAYER M4 ;
        RECT  414.636 140.448 414.72 140.472 ;
    END
  END c_i[535]
  PIN c_i[536]
    DIRECTION INPUT ;
    USE SIGNAL ;
    PORT
      LAYER M4 ;
        RECT  414.636 140.592 414.72 140.616 ;
    END
  END c_i[536]
  PIN c_i[537]
    DIRECTION INPUT ;
    USE SIGNAL ;
    PORT
      LAYER M4 ;
        RECT  414.636 140.736 414.72 140.76 ;
    END
  END c_i[537]
  PIN c_i[538]
    DIRECTION INPUT ;
    USE SIGNAL ;
    PORT
      LAYER M4 ;
        RECT  414.636 140.88 414.72 140.904 ;
    END
  END c_i[538]
  PIN c_i[539]
    DIRECTION INPUT ;
    USE SIGNAL ;
    PORT
      LAYER M4 ;
        RECT  414.636 141.024 414.72 141.048 ;
    END
  END c_i[539]
  PIN c_i[53]
    DIRECTION INPUT ;
    USE SIGNAL ;
    PORT
      LAYER M4 ;
        RECT  414.636 71.04 414.72 71.064 ;
    END
  END c_i[53]
  PIN c_i[540]
    DIRECTION INPUT ;
    USE SIGNAL ;
    PORT
      LAYER M4 ;
        RECT  414.636 141.168 414.72 141.192 ;
    END
  END c_i[540]
  PIN c_i[541]
    DIRECTION INPUT ;
    USE SIGNAL ;
    PORT
      LAYER M4 ;
        RECT  414.636 141.312 414.72 141.336 ;
    END
  END c_i[541]
  PIN c_i[542]
    DIRECTION INPUT ;
    USE SIGNAL ;
    PORT
      LAYER M4 ;
        RECT  414.636 141.456 414.72 141.48 ;
    END
  END c_i[542]
  PIN c_i[543]
    DIRECTION INPUT ;
    USE SIGNAL ;
    PORT
      LAYER M4 ;
        RECT  414.636 141.6 414.72 141.624 ;
    END
  END c_i[543]
  PIN c_i[544]
    DIRECTION INPUT ;
    USE SIGNAL ;
    PORT
      LAYER M4 ;
        RECT  414.636 141.744 414.72 141.768 ;
    END
  END c_i[544]
  PIN c_i[545]
    DIRECTION INPUT ;
    USE SIGNAL ;
    PORT
      LAYER M4 ;
        RECT  414.636 141.888 414.72 141.912 ;
    END
  END c_i[545]
  PIN c_i[546]
    DIRECTION INPUT ;
    USE SIGNAL ;
    PORT
      LAYER M4 ;
        RECT  414.636 142.032 414.72 142.056 ;
    END
  END c_i[546]
  PIN c_i[547]
    DIRECTION INPUT ;
    USE SIGNAL ;
    PORT
      LAYER M4 ;
        RECT  414.636 142.176 414.72 142.2 ;
    END
  END c_i[547]
  PIN c_i[548]
    DIRECTION INPUT ;
    USE SIGNAL ;
    PORT
      LAYER M4 ;
        RECT  414.636 142.32 414.72 142.344 ;
    END
  END c_i[548]
  PIN c_i[549]
    DIRECTION INPUT ;
    USE SIGNAL ;
    PORT
      LAYER M4 ;
        RECT  414.636 142.464 414.72 142.488 ;
    END
  END c_i[549]
  PIN c_i[54]
    DIRECTION INPUT ;
    USE SIGNAL ;
    PORT
      LAYER M4 ;
        RECT  414.636 71.184 414.72 71.208 ;
    END
  END c_i[54]
  PIN c_i[550]
    DIRECTION INPUT ;
    USE SIGNAL ;
    PORT
      LAYER M4 ;
        RECT  414.636 142.608 414.72 142.632 ;
    END
  END c_i[550]
  PIN c_i[551]
    DIRECTION INPUT ;
    USE SIGNAL ;
    PORT
      LAYER M4 ;
        RECT  414.636 142.752 414.72 142.776 ;
    END
  END c_i[551]
  PIN c_i[552]
    DIRECTION INPUT ;
    USE SIGNAL ;
    PORT
      LAYER M4 ;
        RECT  414.636 142.896 414.72 142.92 ;
    END
  END c_i[552]
  PIN c_i[553]
    DIRECTION INPUT ;
    USE SIGNAL ;
    PORT
      LAYER M4 ;
        RECT  414.636 143.04 414.72 143.064 ;
    END
  END c_i[553]
  PIN c_i[554]
    DIRECTION INPUT ;
    USE SIGNAL ;
    PORT
      LAYER M4 ;
        RECT  414.636 143.184 414.72 143.208 ;
    END
  END c_i[554]
  PIN c_i[555]
    DIRECTION INPUT ;
    USE SIGNAL ;
    PORT
      LAYER M4 ;
        RECT  414.636 143.328 414.72 143.352 ;
    END
  END c_i[555]
  PIN c_i[556]
    DIRECTION INPUT ;
    USE SIGNAL ;
    PORT
      LAYER M4 ;
        RECT  414.636 143.472 414.72 143.496 ;
    END
  END c_i[556]
  PIN c_i[557]
    DIRECTION INPUT ;
    USE SIGNAL ;
    PORT
      LAYER M4 ;
        RECT  414.636 143.616 414.72 143.64 ;
    END
  END c_i[557]
  PIN c_i[558]
    DIRECTION INPUT ;
    USE SIGNAL ;
    PORT
      LAYER M4 ;
        RECT  414.636 143.76 414.72 143.784 ;
    END
  END c_i[558]
  PIN c_i[559]
    DIRECTION INPUT ;
    USE SIGNAL ;
    PORT
      LAYER M4 ;
        RECT  414.636 143.904 414.72 143.928 ;
    END
  END c_i[559]
  PIN c_i[55]
    DIRECTION INPUT ;
    USE SIGNAL ;
    PORT
      LAYER M4 ;
        RECT  414.636 71.328 414.72 71.352 ;
    END
  END c_i[55]
  PIN c_i[560]
    DIRECTION INPUT ;
    USE SIGNAL ;
    PORT
      LAYER M4 ;
        RECT  414.636 144.048 414.72 144.072 ;
    END
  END c_i[560]
  PIN c_i[561]
    DIRECTION INPUT ;
    USE SIGNAL ;
    PORT
      LAYER M4 ;
        RECT  414.636 144.192 414.72 144.216 ;
    END
  END c_i[561]
  PIN c_i[562]
    DIRECTION INPUT ;
    USE SIGNAL ;
    PORT
      LAYER M4 ;
        RECT  414.636 144.336 414.72 144.36 ;
    END
  END c_i[562]
  PIN c_i[563]
    DIRECTION INPUT ;
    USE SIGNAL ;
    PORT
      LAYER M4 ;
        RECT  414.636 144.48 414.72 144.504 ;
    END
  END c_i[563]
  PIN c_i[564]
    DIRECTION INPUT ;
    USE SIGNAL ;
    PORT
      LAYER M4 ;
        RECT  414.636 144.624 414.72 144.648 ;
    END
  END c_i[564]
  PIN c_i[565]
    DIRECTION INPUT ;
    USE SIGNAL ;
    PORT
      LAYER M4 ;
        RECT  414.636 144.768 414.72 144.792 ;
    END
  END c_i[565]
  PIN c_i[566]
    DIRECTION INPUT ;
    USE SIGNAL ;
    PORT
      LAYER M4 ;
        RECT  414.636 144.912 414.72 144.936 ;
    END
  END c_i[566]
  PIN c_i[567]
    DIRECTION INPUT ;
    USE SIGNAL ;
    PORT
      LAYER M4 ;
        RECT  414.636 145.056 414.72 145.08 ;
    END
  END c_i[567]
  PIN c_i[568]
    DIRECTION INPUT ;
    USE SIGNAL ;
    PORT
      LAYER M4 ;
        RECT  414.636 145.2 414.72 145.224 ;
    END
  END c_i[568]
  PIN c_i[569]
    DIRECTION INPUT ;
    USE SIGNAL ;
    PORT
      LAYER M4 ;
        RECT  414.636 145.344 414.72 145.368 ;
    END
  END c_i[569]
  PIN c_i[56]
    DIRECTION INPUT ;
    USE SIGNAL ;
    PORT
      LAYER M4 ;
        RECT  414.636 71.472 414.72 71.496 ;
    END
  END c_i[56]
  PIN c_i[570]
    DIRECTION INPUT ;
    USE SIGNAL ;
    PORT
      LAYER M4 ;
        RECT  414.636 145.488 414.72 145.512 ;
    END
  END c_i[570]
  PIN c_i[571]
    DIRECTION INPUT ;
    USE SIGNAL ;
    PORT
      LAYER M4 ;
        RECT  414.636 145.632 414.72 145.656 ;
    END
  END c_i[571]
  PIN c_i[572]
    DIRECTION INPUT ;
    USE SIGNAL ;
    PORT
      LAYER M4 ;
        RECT  414.636 145.776 414.72 145.8 ;
    END
  END c_i[572]
  PIN c_i[573]
    DIRECTION INPUT ;
    USE SIGNAL ;
    PORT
      LAYER M4 ;
        RECT  414.636 145.92 414.72 145.944 ;
    END
  END c_i[573]
  PIN c_i[574]
    DIRECTION INPUT ;
    USE SIGNAL ;
    PORT
      LAYER M4 ;
        RECT  414.636 146.064 414.72 146.088 ;
    END
  END c_i[574]
  PIN c_i[575]
    DIRECTION INPUT ;
    USE SIGNAL ;
    PORT
      LAYER M4 ;
        RECT  414.636 146.208 414.72 146.232 ;
    END
  END c_i[575]
  PIN c_i[576]
    DIRECTION INPUT ;
    USE SIGNAL ;
    PORT
      LAYER M4 ;
        RECT  414.636 146.352 414.72 146.376 ;
    END
  END c_i[576]
  PIN c_i[577]
    DIRECTION INPUT ;
    USE SIGNAL ;
    PORT
      LAYER M4 ;
        RECT  414.636 146.496 414.72 146.52 ;
    END
  END c_i[577]
  PIN c_i[578]
    DIRECTION INPUT ;
    USE SIGNAL ;
    PORT
      LAYER M4 ;
        RECT  414.636 146.64 414.72 146.664 ;
    END
  END c_i[578]
  PIN c_i[579]
    DIRECTION INPUT ;
    USE SIGNAL ;
    PORT
      LAYER M4 ;
        RECT  414.636 146.784 414.72 146.808 ;
    END
  END c_i[579]
  PIN c_i[57]
    DIRECTION INPUT ;
    USE SIGNAL ;
    PORT
      LAYER M4 ;
        RECT  414.636 71.616 414.72 71.64 ;
    END
  END c_i[57]
  PIN c_i[580]
    DIRECTION INPUT ;
    USE SIGNAL ;
    PORT
      LAYER M4 ;
        RECT  414.636 146.928 414.72 146.952 ;
    END
  END c_i[580]
  PIN c_i[581]
    DIRECTION INPUT ;
    USE SIGNAL ;
    PORT
      LAYER M4 ;
        RECT  414.636 147.072 414.72 147.096 ;
    END
  END c_i[581]
  PIN c_i[582]
    DIRECTION INPUT ;
    USE SIGNAL ;
    PORT
      LAYER M4 ;
        RECT  414.636 147.216 414.72 147.24 ;
    END
  END c_i[582]
  PIN c_i[583]
    DIRECTION INPUT ;
    USE SIGNAL ;
    PORT
      LAYER M4 ;
        RECT  414.636 147.36 414.72 147.384 ;
    END
  END c_i[583]
  PIN c_i[584]
    DIRECTION INPUT ;
    USE SIGNAL ;
    PORT
      LAYER M4 ;
        RECT  414.636 147.504 414.72 147.528 ;
    END
  END c_i[584]
  PIN c_i[585]
    DIRECTION INPUT ;
    USE SIGNAL ;
    PORT
      LAYER M4 ;
        RECT  414.636 147.648 414.72 147.672 ;
    END
  END c_i[585]
  PIN c_i[586]
    DIRECTION INPUT ;
    USE SIGNAL ;
    PORT
      LAYER M4 ;
        RECT  414.636 147.792 414.72 147.816 ;
    END
  END c_i[586]
  PIN c_i[587]
    DIRECTION INPUT ;
    USE SIGNAL ;
    PORT
      LAYER M4 ;
        RECT  414.636 147.936 414.72 147.96 ;
    END
  END c_i[587]
  PIN c_i[588]
    DIRECTION INPUT ;
    USE SIGNAL ;
    PORT
      LAYER M4 ;
        RECT  414.636 148.08 414.72 148.104 ;
    END
  END c_i[588]
  PIN c_i[589]
    DIRECTION INPUT ;
    USE SIGNAL ;
    PORT
      LAYER M4 ;
        RECT  414.636 148.224 414.72 148.248 ;
    END
  END c_i[589]
  PIN c_i[58]
    DIRECTION INPUT ;
    USE SIGNAL ;
    PORT
      LAYER M4 ;
        RECT  414.636 71.76 414.72 71.784 ;
    END
  END c_i[58]
  PIN c_i[590]
    DIRECTION INPUT ;
    USE SIGNAL ;
    PORT
      LAYER M4 ;
        RECT  414.636 148.368 414.72 148.392 ;
    END
  END c_i[590]
  PIN c_i[591]
    DIRECTION INPUT ;
    USE SIGNAL ;
    PORT
      LAYER M4 ;
        RECT  414.636 148.512 414.72 148.536 ;
    END
  END c_i[591]
  PIN c_i[592]
    DIRECTION INPUT ;
    USE SIGNAL ;
    PORT
      LAYER M4 ;
        RECT  414.636 148.656 414.72 148.68 ;
    END
  END c_i[592]
  PIN c_i[593]
    DIRECTION INPUT ;
    USE SIGNAL ;
    PORT
      LAYER M4 ;
        RECT  414.636 148.8 414.72 148.824 ;
    END
  END c_i[593]
  PIN c_i[594]
    DIRECTION INPUT ;
    USE SIGNAL ;
    PORT
      LAYER M4 ;
        RECT  414.636 148.944 414.72 148.968 ;
    END
  END c_i[594]
  PIN c_i[595]
    DIRECTION INPUT ;
    USE SIGNAL ;
    PORT
      LAYER M4 ;
        RECT  414.636 149.088 414.72 149.112 ;
    END
  END c_i[595]
  PIN c_i[596]
    DIRECTION INPUT ;
    USE SIGNAL ;
    PORT
      LAYER M4 ;
        RECT  414.636 149.232 414.72 149.256 ;
    END
  END c_i[596]
  PIN c_i[597]
    DIRECTION INPUT ;
    USE SIGNAL ;
    PORT
      LAYER M4 ;
        RECT  414.636 149.376 414.72 149.4 ;
    END
  END c_i[597]
  PIN c_i[598]
    DIRECTION INPUT ;
    USE SIGNAL ;
    PORT
      LAYER M4 ;
        RECT  414.636 149.52 414.72 149.544 ;
    END
  END c_i[598]
  PIN c_i[599]
    DIRECTION INPUT ;
    USE SIGNAL ;
    PORT
      LAYER M4 ;
        RECT  414.636 149.664 414.72 149.688 ;
    END
  END c_i[599]
  PIN c_i[59]
    DIRECTION INPUT ;
    USE SIGNAL ;
    PORT
      LAYER M4 ;
        RECT  414.636 71.904 414.72 71.928 ;
    END
  END c_i[59]
  PIN c_i[5]
    DIRECTION INPUT ;
    USE SIGNAL ;
    PORT
      LAYER M4 ;
        RECT  414.636 64.128 414.72 64.152 ;
    END
  END c_i[5]
  PIN c_i[600]
    DIRECTION INPUT ;
    USE SIGNAL ;
    PORT
      LAYER M4 ;
        RECT  414.636 149.808 414.72 149.832 ;
    END
  END c_i[600]
  PIN c_i[601]
    DIRECTION INPUT ;
    USE SIGNAL ;
    PORT
      LAYER M4 ;
        RECT  414.636 149.952 414.72 149.976 ;
    END
  END c_i[601]
  PIN c_i[602]
    DIRECTION INPUT ;
    USE SIGNAL ;
    PORT
      LAYER M4 ;
        RECT  414.636 150.096 414.72 150.12 ;
    END
  END c_i[602]
  PIN c_i[603]
    DIRECTION INPUT ;
    USE SIGNAL ;
    PORT
      LAYER M4 ;
        RECT  414.636 150.24 414.72 150.264 ;
    END
  END c_i[603]
  PIN c_i[604]
    DIRECTION INPUT ;
    USE SIGNAL ;
    PORT
      LAYER M4 ;
        RECT  414.636 150.384 414.72 150.408 ;
    END
  END c_i[604]
  PIN c_i[605]
    DIRECTION INPUT ;
    USE SIGNAL ;
    PORT
      LAYER M4 ;
        RECT  414.636 150.528 414.72 150.552 ;
    END
  END c_i[605]
  PIN c_i[606]
    DIRECTION INPUT ;
    USE SIGNAL ;
    PORT
      LAYER M4 ;
        RECT  414.636 150.672 414.72 150.696 ;
    END
  END c_i[606]
  PIN c_i[607]
    DIRECTION INPUT ;
    USE SIGNAL ;
    PORT
      LAYER M4 ;
        RECT  414.636 150.816 414.72 150.84 ;
    END
  END c_i[607]
  PIN c_i[608]
    DIRECTION INPUT ;
    USE SIGNAL ;
    PORT
      LAYER M4 ;
        RECT  414.636 150.96 414.72 150.984 ;
    END
  END c_i[608]
  PIN c_i[609]
    DIRECTION INPUT ;
    USE SIGNAL ;
    PORT
      LAYER M4 ;
        RECT  414.636 151.104 414.72 151.128 ;
    END
  END c_i[609]
  PIN c_i[60]
    DIRECTION INPUT ;
    USE SIGNAL ;
    PORT
      LAYER M4 ;
        RECT  414.636 72.048 414.72 72.072 ;
    END
  END c_i[60]
  PIN c_i[610]
    DIRECTION INPUT ;
    USE SIGNAL ;
    PORT
      LAYER M4 ;
        RECT  414.636 151.248 414.72 151.272 ;
    END
  END c_i[610]
  PIN c_i[611]
    DIRECTION INPUT ;
    USE SIGNAL ;
    PORT
      LAYER M4 ;
        RECT  414.636 151.392 414.72 151.416 ;
    END
  END c_i[611]
  PIN c_i[612]
    DIRECTION INPUT ;
    USE SIGNAL ;
    PORT
      LAYER M4 ;
        RECT  414.636 151.536 414.72 151.56 ;
    END
  END c_i[612]
  PIN c_i[613]
    DIRECTION INPUT ;
    USE SIGNAL ;
    PORT
      LAYER M4 ;
        RECT  414.636 151.68 414.72 151.704 ;
    END
  END c_i[613]
  PIN c_i[614]
    DIRECTION INPUT ;
    USE SIGNAL ;
    PORT
      LAYER M4 ;
        RECT  414.636 151.824 414.72 151.848 ;
    END
  END c_i[614]
  PIN c_i[615]
    DIRECTION INPUT ;
    USE SIGNAL ;
    PORT
      LAYER M4 ;
        RECT  414.636 151.968 414.72 151.992 ;
    END
  END c_i[615]
  PIN c_i[616]
    DIRECTION INPUT ;
    USE SIGNAL ;
    PORT
      LAYER M4 ;
        RECT  414.636 152.112 414.72 152.136 ;
    END
  END c_i[616]
  PIN c_i[617]
    DIRECTION INPUT ;
    USE SIGNAL ;
    PORT
      LAYER M4 ;
        RECT  414.636 152.256 414.72 152.28 ;
    END
  END c_i[617]
  PIN c_i[618]
    DIRECTION INPUT ;
    USE SIGNAL ;
    PORT
      LAYER M4 ;
        RECT  414.636 152.4 414.72 152.424 ;
    END
  END c_i[618]
  PIN c_i[619]
    DIRECTION INPUT ;
    USE SIGNAL ;
    PORT
      LAYER M4 ;
        RECT  414.636 152.544 414.72 152.568 ;
    END
  END c_i[619]
  PIN c_i[61]
    DIRECTION INPUT ;
    USE SIGNAL ;
    PORT
      LAYER M4 ;
        RECT  414.636 72.192 414.72 72.216 ;
    END
  END c_i[61]
  PIN c_i[620]
    DIRECTION INPUT ;
    USE SIGNAL ;
    PORT
      LAYER M4 ;
        RECT  414.636 152.688 414.72 152.712 ;
    END
  END c_i[620]
  PIN c_i[621]
    DIRECTION INPUT ;
    USE SIGNAL ;
    PORT
      LAYER M4 ;
        RECT  414.636 152.832 414.72 152.856 ;
    END
  END c_i[621]
  PIN c_i[622]
    DIRECTION INPUT ;
    USE SIGNAL ;
    PORT
      LAYER M4 ;
        RECT  414.636 152.976 414.72 153 ;
    END
  END c_i[622]
  PIN c_i[623]
    DIRECTION INPUT ;
    USE SIGNAL ;
    PORT
      LAYER M4 ;
        RECT  414.636 153.12 414.72 153.144 ;
    END
  END c_i[623]
  PIN c_i[624]
    DIRECTION INPUT ;
    USE SIGNAL ;
    PORT
      LAYER M4 ;
        RECT  414.636 153.264 414.72 153.288 ;
    END
  END c_i[624]
  PIN c_i[625]
    DIRECTION INPUT ;
    USE SIGNAL ;
    PORT
      LAYER M4 ;
        RECT  414.636 153.408 414.72 153.432 ;
    END
  END c_i[625]
  PIN c_i[626]
    DIRECTION INPUT ;
    USE SIGNAL ;
    PORT
      LAYER M4 ;
        RECT  414.636 153.552 414.72 153.576 ;
    END
  END c_i[626]
  PIN c_i[627]
    DIRECTION INPUT ;
    USE SIGNAL ;
    PORT
      LAYER M4 ;
        RECT  414.636 153.696 414.72 153.72 ;
    END
  END c_i[627]
  PIN c_i[628]
    DIRECTION INPUT ;
    USE SIGNAL ;
    PORT
      LAYER M4 ;
        RECT  414.636 153.84 414.72 153.864 ;
    END
  END c_i[628]
  PIN c_i[629]
    DIRECTION INPUT ;
    USE SIGNAL ;
    PORT
      LAYER M4 ;
        RECT  414.636 153.984 414.72 154.008 ;
    END
  END c_i[629]
  PIN c_i[62]
    DIRECTION INPUT ;
    USE SIGNAL ;
    PORT
      LAYER M4 ;
        RECT  414.636 72.336 414.72 72.36 ;
    END
  END c_i[62]
  PIN c_i[630]
    DIRECTION INPUT ;
    USE SIGNAL ;
    PORT
      LAYER M4 ;
        RECT  414.636 154.128 414.72 154.152 ;
    END
  END c_i[630]
  PIN c_i[631]
    DIRECTION INPUT ;
    USE SIGNAL ;
    PORT
      LAYER M4 ;
        RECT  414.636 154.272 414.72 154.296 ;
    END
  END c_i[631]
  PIN c_i[632]
    DIRECTION INPUT ;
    USE SIGNAL ;
    PORT
      LAYER M4 ;
        RECT  414.636 154.416 414.72 154.44 ;
    END
  END c_i[632]
  PIN c_i[633]
    DIRECTION INPUT ;
    USE SIGNAL ;
    PORT
      LAYER M4 ;
        RECT  414.636 154.56 414.72 154.584 ;
    END
  END c_i[633]
  PIN c_i[634]
    DIRECTION INPUT ;
    USE SIGNAL ;
    PORT
      LAYER M4 ;
        RECT  414.636 154.704 414.72 154.728 ;
    END
  END c_i[634]
  PIN c_i[635]
    DIRECTION INPUT ;
    USE SIGNAL ;
    PORT
      LAYER M4 ;
        RECT  414.636 154.848 414.72 154.872 ;
    END
  END c_i[635]
  PIN c_i[636]
    DIRECTION INPUT ;
    USE SIGNAL ;
    PORT
      LAYER M4 ;
        RECT  414.636 154.992 414.72 155.016 ;
    END
  END c_i[636]
  PIN c_i[637]
    DIRECTION INPUT ;
    USE SIGNAL ;
    PORT
      LAYER M4 ;
        RECT  414.636 155.136 414.72 155.16 ;
    END
  END c_i[637]
  PIN c_i[638]
    DIRECTION INPUT ;
    USE SIGNAL ;
    PORT
      LAYER M4 ;
        RECT  414.636 155.28 414.72 155.304 ;
    END
  END c_i[638]
  PIN c_i[639]
    DIRECTION INPUT ;
    USE SIGNAL ;
    PORT
      LAYER M4 ;
        RECT  414.636 155.424 414.72 155.448 ;
    END
  END c_i[639]
  PIN c_i[63]
    DIRECTION INPUT ;
    USE SIGNAL ;
    PORT
      LAYER M4 ;
        RECT  414.636 72.48 414.72 72.504 ;
    END
  END c_i[63]
  PIN c_i[640]
    DIRECTION INPUT ;
    USE SIGNAL ;
    PORT
      LAYER M4 ;
        RECT  414.636 155.568 414.72 155.592 ;
    END
  END c_i[640]
  PIN c_i[641]
    DIRECTION INPUT ;
    USE SIGNAL ;
    PORT
      LAYER M4 ;
        RECT  414.636 155.712 414.72 155.736 ;
    END
  END c_i[641]
  PIN c_i[642]
    DIRECTION INPUT ;
    USE SIGNAL ;
    PORT
      LAYER M4 ;
        RECT  414.636 155.856 414.72 155.88 ;
    END
  END c_i[642]
  PIN c_i[643]
    DIRECTION INPUT ;
    USE SIGNAL ;
    PORT
      LAYER M4 ;
        RECT  414.636 156 414.72 156.024 ;
    END
  END c_i[643]
  PIN c_i[644]
    DIRECTION INPUT ;
    USE SIGNAL ;
    PORT
      LAYER M4 ;
        RECT  414.636 156.144 414.72 156.168 ;
    END
  END c_i[644]
  PIN c_i[645]
    DIRECTION INPUT ;
    USE SIGNAL ;
    PORT
      LAYER M4 ;
        RECT  414.636 156.288 414.72 156.312 ;
    END
  END c_i[645]
  PIN c_i[646]
    DIRECTION INPUT ;
    USE SIGNAL ;
    PORT
      LAYER M4 ;
        RECT  414.636 156.432 414.72 156.456 ;
    END
  END c_i[646]
  PIN c_i[647]
    DIRECTION INPUT ;
    USE SIGNAL ;
    PORT
      LAYER M4 ;
        RECT  414.636 156.576 414.72 156.6 ;
    END
  END c_i[647]
  PIN c_i[648]
    DIRECTION INPUT ;
    USE SIGNAL ;
    PORT
      LAYER M4 ;
        RECT  414.636 156.72 414.72 156.744 ;
    END
  END c_i[648]
  PIN c_i[649]
    DIRECTION INPUT ;
    USE SIGNAL ;
    PORT
      LAYER M4 ;
        RECT  414.636 156.864 414.72 156.888 ;
    END
  END c_i[649]
  PIN c_i[64]
    DIRECTION INPUT ;
    USE SIGNAL ;
    PORT
      LAYER M4 ;
        RECT  414.636 72.624 414.72 72.648 ;
    END
  END c_i[64]
  PIN c_i[650]
    DIRECTION INPUT ;
    USE SIGNAL ;
    PORT
      LAYER M4 ;
        RECT  414.636 157.008 414.72 157.032 ;
    END
  END c_i[650]
  PIN c_i[651]
    DIRECTION INPUT ;
    USE SIGNAL ;
    PORT
      LAYER M4 ;
        RECT  414.636 157.152 414.72 157.176 ;
    END
  END c_i[651]
  PIN c_i[652]
    DIRECTION INPUT ;
    USE SIGNAL ;
    PORT
      LAYER M4 ;
        RECT  414.636 157.296 414.72 157.32 ;
    END
  END c_i[652]
  PIN c_i[653]
    DIRECTION INPUT ;
    USE SIGNAL ;
    PORT
      LAYER M4 ;
        RECT  414.636 157.44 414.72 157.464 ;
    END
  END c_i[653]
  PIN c_i[654]
    DIRECTION INPUT ;
    USE SIGNAL ;
    PORT
      LAYER M4 ;
        RECT  414.636 157.584 414.72 157.608 ;
    END
  END c_i[654]
  PIN c_i[655]
    DIRECTION INPUT ;
    USE SIGNAL ;
    PORT
      LAYER M4 ;
        RECT  414.636 157.728 414.72 157.752 ;
    END
  END c_i[655]
  PIN c_i[656]
    DIRECTION INPUT ;
    USE SIGNAL ;
    PORT
      LAYER M4 ;
        RECT  414.636 157.872 414.72 157.896 ;
    END
  END c_i[656]
  PIN c_i[657]
    DIRECTION INPUT ;
    USE SIGNAL ;
    PORT
      LAYER M4 ;
        RECT  414.636 158.016 414.72 158.04 ;
    END
  END c_i[657]
  PIN c_i[658]
    DIRECTION INPUT ;
    USE SIGNAL ;
    PORT
      LAYER M4 ;
        RECT  414.636 158.16 414.72 158.184 ;
    END
  END c_i[658]
  PIN c_i[659]
    DIRECTION INPUT ;
    USE SIGNAL ;
    PORT
      LAYER M4 ;
        RECT  414.636 158.304 414.72 158.328 ;
    END
  END c_i[659]
  PIN c_i[65]
    DIRECTION INPUT ;
    USE SIGNAL ;
    PORT
      LAYER M4 ;
        RECT  414.636 72.768 414.72 72.792 ;
    END
  END c_i[65]
  PIN c_i[660]
    DIRECTION INPUT ;
    USE SIGNAL ;
    PORT
      LAYER M4 ;
        RECT  414.636 158.448 414.72 158.472 ;
    END
  END c_i[660]
  PIN c_i[661]
    DIRECTION INPUT ;
    USE SIGNAL ;
    PORT
      LAYER M4 ;
        RECT  414.636 158.592 414.72 158.616 ;
    END
  END c_i[661]
  PIN c_i[662]
    DIRECTION INPUT ;
    USE SIGNAL ;
    PORT
      LAYER M4 ;
        RECT  414.636 158.736 414.72 158.76 ;
    END
  END c_i[662]
  PIN c_i[663]
    DIRECTION INPUT ;
    USE SIGNAL ;
    PORT
      LAYER M4 ;
        RECT  414.636 158.88 414.72 158.904 ;
    END
  END c_i[663]
  PIN c_i[664]
    DIRECTION INPUT ;
    USE SIGNAL ;
    PORT
      LAYER M4 ;
        RECT  414.636 159.024 414.72 159.048 ;
    END
  END c_i[664]
  PIN c_i[665]
    DIRECTION INPUT ;
    USE SIGNAL ;
    PORT
      LAYER M4 ;
        RECT  414.636 159.168 414.72 159.192 ;
    END
  END c_i[665]
  PIN c_i[666]
    DIRECTION INPUT ;
    USE SIGNAL ;
    PORT
      LAYER M4 ;
        RECT  414.636 159.312 414.72 159.336 ;
    END
  END c_i[666]
  PIN c_i[667]
    DIRECTION INPUT ;
    USE SIGNAL ;
    PORT
      LAYER M4 ;
        RECT  414.636 159.456 414.72 159.48 ;
    END
  END c_i[667]
  PIN c_i[668]
    DIRECTION INPUT ;
    USE SIGNAL ;
    PORT
      LAYER M4 ;
        RECT  414.636 159.6 414.72 159.624 ;
    END
  END c_i[668]
  PIN c_i[669]
    DIRECTION INPUT ;
    USE SIGNAL ;
    PORT
      LAYER M4 ;
        RECT  414.636 159.744 414.72 159.768 ;
    END
  END c_i[669]
  PIN c_i[66]
    DIRECTION INPUT ;
    USE SIGNAL ;
    PORT
      LAYER M4 ;
        RECT  414.636 72.912 414.72 72.936 ;
    END
  END c_i[66]
  PIN c_i[670]
    DIRECTION INPUT ;
    USE SIGNAL ;
    PORT
      LAYER M4 ;
        RECT  414.636 159.888 414.72 159.912 ;
    END
  END c_i[670]
  PIN c_i[671]
    DIRECTION INPUT ;
    USE SIGNAL ;
    PORT
      LAYER M4 ;
        RECT  414.636 160.032 414.72 160.056 ;
    END
  END c_i[671]
  PIN c_i[672]
    DIRECTION INPUT ;
    USE SIGNAL ;
    PORT
      LAYER M4 ;
        RECT  414.636 160.176 414.72 160.2 ;
    END
  END c_i[672]
  PIN c_i[673]
    DIRECTION INPUT ;
    USE SIGNAL ;
    PORT
      LAYER M4 ;
        RECT  414.636 160.32 414.72 160.344 ;
    END
  END c_i[673]
  PIN c_i[674]
    DIRECTION INPUT ;
    USE SIGNAL ;
    PORT
      LAYER M4 ;
        RECT  414.636 160.464 414.72 160.488 ;
    END
  END c_i[674]
  PIN c_i[675]
    DIRECTION INPUT ;
    USE SIGNAL ;
    PORT
      LAYER M4 ;
        RECT  414.636 160.608 414.72 160.632 ;
    END
  END c_i[675]
  PIN c_i[676]
    DIRECTION INPUT ;
    USE SIGNAL ;
    PORT
      LAYER M4 ;
        RECT  414.636 160.752 414.72 160.776 ;
    END
  END c_i[676]
  PIN c_i[677]
    DIRECTION INPUT ;
    USE SIGNAL ;
    PORT
      LAYER M4 ;
        RECT  414.636 160.896 414.72 160.92 ;
    END
  END c_i[677]
  PIN c_i[678]
    DIRECTION INPUT ;
    USE SIGNAL ;
    PORT
      LAYER M4 ;
        RECT  414.636 161.04 414.72 161.064 ;
    END
  END c_i[678]
  PIN c_i[679]
    DIRECTION INPUT ;
    USE SIGNAL ;
    PORT
      LAYER M4 ;
        RECT  414.636 161.184 414.72 161.208 ;
    END
  END c_i[679]
  PIN c_i[67]
    DIRECTION INPUT ;
    USE SIGNAL ;
    PORT
      LAYER M4 ;
        RECT  414.636 73.056 414.72 73.08 ;
    END
  END c_i[67]
  PIN c_i[680]
    DIRECTION INPUT ;
    USE SIGNAL ;
    PORT
      LAYER M4 ;
        RECT  414.636 161.328 414.72 161.352 ;
    END
  END c_i[680]
  PIN c_i[681]
    DIRECTION INPUT ;
    USE SIGNAL ;
    PORT
      LAYER M4 ;
        RECT  414.636 161.472 414.72 161.496 ;
    END
  END c_i[681]
  PIN c_i[682]
    DIRECTION INPUT ;
    USE SIGNAL ;
    PORT
      LAYER M4 ;
        RECT  414.636 161.616 414.72 161.64 ;
    END
  END c_i[682]
  PIN c_i[683]
    DIRECTION INPUT ;
    USE SIGNAL ;
    PORT
      LAYER M4 ;
        RECT  414.636 161.76 414.72 161.784 ;
    END
  END c_i[683]
  PIN c_i[684]
    DIRECTION INPUT ;
    USE SIGNAL ;
    PORT
      LAYER M4 ;
        RECT  414.636 161.904 414.72 161.928 ;
    END
  END c_i[684]
  PIN c_i[685]
    DIRECTION INPUT ;
    USE SIGNAL ;
    PORT
      LAYER M4 ;
        RECT  414.636 162.048 414.72 162.072 ;
    END
  END c_i[685]
  PIN c_i[686]
    DIRECTION INPUT ;
    USE SIGNAL ;
    PORT
      LAYER M4 ;
        RECT  414.636 162.192 414.72 162.216 ;
    END
  END c_i[686]
  PIN c_i[687]
    DIRECTION INPUT ;
    USE SIGNAL ;
    PORT
      LAYER M4 ;
        RECT  414.636 162.336 414.72 162.36 ;
    END
  END c_i[687]
  PIN c_i[688]
    DIRECTION INPUT ;
    USE SIGNAL ;
    PORT
      LAYER M4 ;
        RECT  414.636 162.48 414.72 162.504 ;
    END
  END c_i[688]
  PIN c_i[689]
    DIRECTION INPUT ;
    USE SIGNAL ;
    PORT
      LAYER M4 ;
        RECT  414.636 162.624 414.72 162.648 ;
    END
  END c_i[689]
  PIN c_i[68]
    DIRECTION INPUT ;
    USE SIGNAL ;
    PORT
      LAYER M4 ;
        RECT  414.636 73.2 414.72 73.224 ;
    END
  END c_i[68]
  PIN c_i[690]
    DIRECTION INPUT ;
    USE SIGNAL ;
    PORT
      LAYER M4 ;
        RECT  414.636 162.768 414.72 162.792 ;
    END
  END c_i[690]
  PIN c_i[691]
    DIRECTION INPUT ;
    USE SIGNAL ;
    PORT
      LAYER M4 ;
        RECT  414.636 162.912 414.72 162.936 ;
    END
  END c_i[691]
  PIN c_i[692]
    DIRECTION INPUT ;
    USE SIGNAL ;
    PORT
      LAYER M4 ;
        RECT  414.636 163.056 414.72 163.08 ;
    END
  END c_i[692]
  PIN c_i[693]
    DIRECTION INPUT ;
    USE SIGNAL ;
    PORT
      LAYER M4 ;
        RECT  414.636 163.2 414.72 163.224 ;
    END
  END c_i[693]
  PIN c_i[694]
    DIRECTION INPUT ;
    USE SIGNAL ;
    PORT
      LAYER M4 ;
        RECT  414.636 163.344 414.72 163.368 ;
    END
  END c_i[694]
  PIN c_i[695]
    DIRECTION INPUT ;
    USE SIGNAL ;
    PORT
      LAYER M4 ;
        RECT  414.636 163.488 414.72 163.512 ;
    END
  END c_i[695]
  PIN c_i[696]
    DIRECTION INPUT ;
    USE SIGNAL ;
    PORT
      LAYER M4 ;
        RECT  414.636 163.632 414.72 163.656 ;
    END
  END c_i[696]
  PIN c_i[697]
    DIRECTION INPUT ;
    USE SIGNAL ;
    PORT
      LAYER M4 ;
        RECT  414.636 163.776 414.72 163.8 ;
    END
  END c_i[697]
  PIN c_i[698]
    DIRECTION INPUT ;
    USE SIGNAL ;
    PORT
      LAYER M4 ;
        RECT  414.636 163.92 414.72 163.944 ;
    END
  END c_i[698]
  PIN c_i[699]
    DIRECTION INPUT ;
    USE SIGNAL ;
    PORT
      LAYER M4 ;
        RECT  414.636 164.064 414.72 164.088 ;
    END
  END c_i[699]
  PIN c_i[69]
    DIRECTION INPUT ;
    USE SIGNAL ;
    PORT
      LAYER M4 ;
        RECT  414.636 73.344 414.72 73.368 ;
    END
  END c_i[69]
  PIN c_i[6]
    DIRECTION INPUT ;
    USE SIGNAL ;
    PORT
      LAYER M4 ;
        RECT  414.636 64.272 414.72 64.296 ;
    END
  END c_i[6]
  PIN c_i[700]
    DIRECTION INPUT ;
    USE SIGNAL ;
    PORT
      LAYER M4 ;
        RECT  414.636 164.208 414.72 164.232 ;
    END
  END c_i[700]
  PIN c_i[701]
    DIRECTION INPUT ;
    USE SIGNAL ;
    PORT
      LAYER M4 ;
        RECT  414.636 164.352 414.72 164.376 ;
    END
  END c_i[701]
  PIN c_i[702]
    DIRECTION INPUT ;
    USE SIGNAL ;
    PORT
      LAYER M4 ;
        RECT  414.636 164.496 414.72 164.52 ;
    END
  END c_i[702]
  PIN c_i[703]
    DIRECTION INPUT ;
    USE SIGNAL ;
    PORT
      LAYER M4 ;
        RECT  414.636 164.64 414.72 164.664 ;
    END
  END c_i[703]
  PIN c_i[704]
    DIRECTION INPUT ;
    USE SIGNAL ;
    PORT
      LAYER M4 ;
        RECT  414.636 164.784 414.72 164.808 ;
    END
  END c_i[704]
  PIN c_i[705]
    DIRECTION INPUT ;
    USE SIGNAL ;
    PORT
      LAYER M4 ;
        RECT  414.636 164.928 414.72 164.952 ;
    END
  END c_i[705]
  PIN c_i[706]
    DIRECTION INPUT ;
    USE SIGNAL ;
    PORT
      LAYER M4 ;
        RECT  414.636 165.072 414.72 165.096 ;
    END
  END c_i[706]
  PIN c_i[707]
    DIRECTION INPUT ;
    USE SIGNAL ;
    PORT
      LAYER M4 ;
        RECT  414.636 165.216 414.72 165.24 ;
    END
  END c_i[707]
  PIN c_i[708]
    DIRECTION INPUT ;
    USE SIGNAL ;
    PORT
      LAYER M4 ;
        RECT  414.636 165.36 414.72 165.384 ;
    END
  END c_i[708]
  PIN c_i[709]
    DIRECTION INPUT ;
    USE SIGNAL ;
    PORT
      LAYER M4 ;
        RECT  414.636 165.504 414.72 165.528 ;
    END
  END c_i[709]
  PIN c_i[70]
    DIRECTION INPUT ;
    USE SIGNAL ;
    PORT
      LAYER M4 ;
        RECT  414.636 73.488 414.72 73.512 ;
    END
  END c_i[70]
  PIN c_i[710]
    DIRECTION INPUT ;
    USE SIGNAL ;
    PORT
      LAYER M4 ;
        RECT  414.636 165.648 414.72 165.672 ;
    END
  END c_i[710]
  PIN c_i[711]
    DIRECTION INPUT ;
    USE SIGNAL ;
    PORT
      LAYER M4 ;
        RECT  414.636 165.792 414.72 165.816 ;
    END
  END c_i[711]
  PIN c_i[712]
    DIRECTION INPUT ;
    USE SIGNAL ;
    PORT
      LAYER M4 ;
        RECT  414.636 165.936 414.72 165.96 ;
    END
  END c_i[712]
  PIN c_i[713]
    DIRECTION INPUT ;
    USE SIGNAL ;
    PORT
      LAYER M4 ;
        RECT  414.636 166.08 414.72 166.104 ;
    END
  END c_i[713]
  PIN c_i[714]
    DIRECTION INPUT ;
    USE SIGNAL ;
    PORT
      LAYER M4 ;
        RECT  414.636 166.224 414.72 166.248 ;
    END
  END c_i[714]
  PIN c_i[715]
    DIRECTION INPUT ;
    USE SIGNAL ;
    PORT
      LAYER M4 ;
        RECT  414.636 166.368 414.72 166.392 ;
    END
  END c_i[715]
  PIN c_i[716]
    DIRECTION INPUT ;
    USE SIGNAL ;
    PORT
      LAYER M4 ;
        RECT  414.636 166.512 414.72 166.536 ;
    END
  END c_i[716]
  PIN c_i[717]
    DIRECTION INPUT ;
    USE SIGNAL ;
    PORT
      LAYER M4 ;
        RECT  414.636 166.656 414.72 166.68 ;
    END
  END c_i[717]
  PIN c_i[718]
    DIRECTION INPUT ;
    USE SIGNAL ;
    PORT
      LAYER M4 ;
        RECT  414.636 166.8 414.72 166.824 ;
    END
  END c_i[718]
  PIN c_i[719]
    DIRECTION INPUT ;
    USE SIGNAL ;
    PORT
      LAYER M4 ;
        RECT  414.636 166.944 414.72 166.968 ;
    END
  END c_i[719]
  PIN c_i[71]
    DIRECTION INPUT ;
    USE SIGNAL ;
    PORT
      LAYER M4 ;
        RECT  414.636 73.632 414.72 73.656 ;
    END
  END c_i[71]
  PIN c_i[720]
    DIRECTION INPUT ;
    USE SIGNAL ;
    PORT
      LAYER M4 ;
        RECT  414.636 167.088 414.72 167.112 ;
    END
  END c_i[720]
  PIN c_i[721]
    DIRECTION INPUT ;
    USE SIGNAL ;
    PORT
      LAYER M4 ;
        RECT  414.636 167.232 414.72 167.256 ;
    END
  END c_i[721]
  PIN c_i[722]
    DIRECTION INPUT ;
    USE SIGNAL ;
    PORT
      LAYER M4 ;
        RECT  414.636 167.376 414.72 167.4 ;
    END
  END c_i[722]
  PIN c_i[723]
    DIRECTION INPUT ;
    USE SIGNAL ;
    PORT
      LAYER M4 ;
        RECT  414.636 167.52 414.72 167.544 ;
    END
  END c_i[723]
  PIN c_i[724]
    DIRECTION INPUT ;
    USE SIGNAL ;
    PORT
      LAYER M4 ;
        RECT  414.636 167.664 414.72 167.688 ;
    END
  END c_i[724]
  PIN c_i[725]
    DIRECTION INPUT ;
    USE SIGNAL ;
    PORT
      LAYER M4 ;
        RECT  414.636 167.808 414.72 167.832 ;
    END
  END c_i[725]
  PIN c_i[726]
    DIRECTION INPUT ;
    USE SIGNAL ;
    PORT
      LAYER M4 ;
        RECT  414.636 167.952 414.72 167.976 ;
    END
  END c_i[726]
  PIN c_i[727]
    DIRECTION INPUT ;
    USE SIGNAL ;
    PORT
      LAYER M4 ;
        RECT  414.636 168.096 414.72 168.12 ;
    END
  END c_i[727]
  PIN c_i[728]
    DIRECTION INPUT ;
    USE SIGNAL ;
    PORT
      LAYER M4 ;
        RECT  414.636 168.24 414.72 168.264 ;
    END
  END c_i[728]
  PIN c_i[729]
    DIRECTION INPUT ;
    USE SIGNAL ;
    PORT
      LAYER M4 ;
        RECT  414.636 168.384 414.72 168.408 ;
    END
  END c_i[729]
  PIN c_i[72]
    DIRECTION INPUT ;
    USE SIGNAL ;
    PORT
      LAYER M4 ;
        RECT  414.636 73.776 414.72 73.8 ;
    END
  END c_i[72]
  PIN c_i[730]
    DIRECTION INPUT ;
    USE SIGNAL ;
    PORT
      LAYER M4 ;
        RECT  414.636 168.528 414.72 168.552 ;
    END
  END c_i[730]
  PIN c_i[731]
    DIRECTION INPUT ;
    USE SIGNAL ;
    PORT
      LAYER M4 ;
        RECT  414.636 168.672 414.72 168.696 ;
    END
  END c_i[731]
  PIN c_i[732]
    DIRECTION INPUT ;
    USE SIGNAL ;
    PORT
      LAYER M4 ;
        RECT  414.636 168.816 414.72 168.84 ;
    END
  END c_i[732]
  PIN c_i[733]
    DIRECTION INPUT ;
    USE SIGNAL ;
    PORT
      LAYER M4 ;
        RECT  414.636 168.96 414.72 168.984 ;
    END
  END c_i[733]
  PIN c_i[734]
    DIRECTION INPUT ;
    USE SIGNAL ;
    PORT
      LAYER M4 ;
        RECT  414.636 169.104 414.72 169.128 ;
    END
  END c_i[734]
  PIN c_i[735]
    DIRECTION INPUT ;
    USE SIGNAL ;
    PORT
      LAYER M4 ;
        RECT  414.636 169.248 414.72 169.272 ;
    END
  END c_i[735]
  PIN c_i[736]
    DIRECTION INPUT ;
    USE SIGNAL ;
    PORT
      LAYER M4 ;
        RECT  414.636 169.392 414.72 169.416 ;
    END
  END c_i[736]
  PIN c_i[737]
    DIRECTION INPUT ;
    USE SIGNAL ;
    PORT
      LAYER M4 ;
        RECT  414.636 169.536 414.72 169.56 ;
    END
  END c_i[737]
  PIN c_i[738]
    DIRECTION INPUT ;
    USE SIGNAL ;
    PORT
      LAYER M4 ;
        RECT  414.636 169.68 414.72 169.704 ;
    END
  END c_i[738]
  PIN c_i[739]
    DIRECTION INPUT ;
    USE SIGNAL ;
    PORT
      LAYER M4 ;
        RECT  414.636 169.824 414.72 169.848 ;
    END
  END c_i[739]
  PIN c_i[73]
    DIRECTION INPUT ;
    USE SIGNAL ;
    PORT
      LAYER M4 ;
        RECT  414.636 73.92 414.72 73.944 ;
    END
  END c_i[73]
  PIN c_i[740]
    DIRECTION INPUT ;
    USE SIGNAL ;
    PORT
      LAYER M4 ;
        RECT  414.636 169.968 414.72 169.992 ;
    END
  END c_i[740]
  PIN c_i[741]
    DIRECTION INPUT ;
    USE SIGNAL ;
    PORT
      LAYER M4 ;
        RECT  414.636 170.112 414.72 170.136 ;
    END
  END c_i[741]
  PIN c_i[742]
    DIRECTION INPUT ;
    USE SIGNAL ;
    PORT
      LAYER M4 ;
        RECT  414.636 170.256 414.72 170.28 ;
    END
  END c_i[742]
  PIN c_i[743]
    DIRECTION INPUT ;
    USE SIGNAL ;
    PORT
      LAYER M4 ;
        RECT  414.636 170.4 414.72 170.424 ;
    END
  END c_i[743]
  PIN c_i[744]
    DIRECTION INPUT ;
    USE SIGNAL ;
    PORT
      LAYER M4 ;
        RECT  414.636 170.544 414.72 170.568 ;
    END
  END c_i[744]
  PIN c_i[745]
    DIRECTION INPUT ;
    USE SIGNAL ;
    PORT
      LAYER M4 ;
        RECT  414.636 170.688 414.72 170.712 ;
    END
  END c_i[745]
  PIN c_i[746]
    DIRECTION INPUT ;
    USE SIGNAL ;
    PORT
      LAYER M4 ;
        RECT  414.636 170.832 414.72 170.856 ;
    END
  END c_i[746]
  PIN c_i[747]
    DIRECTION INPUT ;
    USE SIGNAL ;
    PORT
      LAYER M4 ;
        RECT  414.636 170.976 414.72 171 ;
    END
  END c_i[747]
  PIN c_i[748]
    DIRECTION INPUT ;
    USE SIGNAL ;
    PORT
      LAYER M4 ;
        RECT  414.636 171.12 414.72 171.144 ;
    END
  END c_i[748]
  PIN c_i[749]
    DIRECTION INPUT ;
    USE SIGNAL ;
    PORT
      LAYER M4 ;
        RECT  414.636 171.264 414.72 171.288 ;
    END
  END c_i[749]
  PIN c_i[74]
    DIRECTION INPUT ;
    USE SIGNAL ;
    PORT
      LAYER M4 ;
        RECT  414.636 74.064 414.72 74.088 ;
    END
  END c_i[74]
  PIN c_i[750]
    DIRECTION INPUT ;
    USE SIGNAL ;
    PORT
      LAYER M4 ;
        RECT  414.636 171.408 414.72 171.432 ;
    END
  END c_i[750]
  PIN c_i[751]
    DIRECTION INPUT ;
    USE SIGNAL ;
    PORT
      LAYER M4 ;
        RECT  414.636 171.552 414.72 171.576 ;
    END
  END c_i[751]
  PIN c_i[752]
    DIRECTION INPUT ;
    USE SIGNAL ;
    PORT
      LAYER M4 ;
        RECT  414.636 171.696 414.72 171.72 ;
    END
  END c_i[752]
  PIN c_i[753]
    DIRECTION INPUT ;
    USE SIGNAL ;
    PORT
      LAYER M4 ;
        RECT  414.636 171.84 414.72 171.864 ;
    END
  END c_i[753]
  PIN c_i[754]
    DIRECTION INPUT ;
    USE SIGNAL ;
    PORT
      LAYER M4 ;
        RECT  414.636 171.984 414.72 172.008 ;
    END
  END c_i[754]
  PIN c_i[755]
    DIRECTION INPUT ;
    USE SIGNAL ;
    PORT
      LAYER M4 ;
        RECT  414.636 172.128 414.72 172.152 ;
    END
  END c_i[755]
  PIN c_i[756]
    DIRECTION INPUT ;
    USE SIGNAL ;
    PORT
      LAYER M4 ;
        RECT  414.636 172.272 414.72 172.296 ;
    END
  END c_i[756]
  PIN c_i[757]
    DIRECTION INPUT ;
    USE SIGNAL ;
    PORT
      LAYER M4 ;
        RECT  414.636 172.416 414.72 172.44 ;
    END
  END c_i[757]
  PIN c_i[758]
    DIRECTION INPUT ;
    USE SIGNAL ;
    PORT
      LAYER M4 ;
        RECT  414.636 172.56 414.72 172.584 ;
    END
  END c_i[758]
  PIN c_i[759]
    DIRECTION INPUT ;
    USE SIGNAL ;
    PORT
      LAYER M4 ;
        RECT  414.636 172.704 414.72 172.728 ;
    END
  END c_i[759]
  PIN c_i[75]
    DIRECTION INPUT ;
    USE SIGNAL ;
    PORT
      LAYER M4 ;
        RECT  414.636 74.208 414.72 74.232 ;
    END
  END c_i[75]
  PIN c_i[76]
    DIRECTION INPUT ;
    USE SIGNAL ;
    PORT
      LAYER M4 ;
        RECT  414.636 74.352 414.72 74.376 ;
    END
  END c_i[76]
  PIN c_i[77]
    DIRECTION INPUT ;
    USE SIGNAL ;
    PORT
      LAYER M4 ;
        RECT  414.636 74.496 414.72 74.52 ;
    END
  END c_i[77]
  PIN c_i[78]
    DIRECTION INPUT ;
    USE SIGNAL ;
    PORT
      LAYER M4 ;
        RECT  414.636 74.64 414.72 74.664 ;
    END
  END c_i[78]
  PIN c_i[79]
    DIRECTION INPUT ;
    USE SIGNAL ;
    PORT
      LAYER M4 ;
        RECT  414.636 74.784 414.72 74.808 ;
    END
  END c_i[79]
  PIN c_i[7]
    DIRECTION INPUT ;
    USE SIGNAL ;
    PORT
      LAYER M4 ;
        RECT  414.636 64.416 414.72 64.44 ;
    END
  END c_i[7]
  PIN c_i[80]
    DIRECTION INPUT ;
    USE SIGNAL ;
    PORT
      LAYER M4 ;
        RECT  414.636 74.928 414.72 74.952 ;
    END
  END c_i[80]
  PIN c_i[81]
    DIRECTION INPUT ;
    USE SIGNAL ;
    PORT
      LAYER M4 ;
        RECT  414.636 75.072 414.72 75.096 ;
    END
  END c_i[81]
  PIN c_i[82]
    DIRECTION INPUT ;
    USE SIGNAL ;
    PORT
      LAYER M4 ;
        RECT  414.636 75.216 414.72 75.24 ;
    END
  END c_i[82]
  PIN c_i[83]
    DIRECTION INPUT ;
    USE SIGNAL ;
    PORT
      LAYER M4 ;
        RECT  414.636 75.36 414.72 75.384 ;
    END
  END c_i[83]
  PIN c_i[84]
    DIRECTION INPUT ;
    USE SIGNAL ;
    PORT
      LAYER M4 ;
        RECT  414.636 75.504 414.72 75.528 ;
    END
  END c_i[84]
  PIN c_i[85]
    DIRECTION INPUT ;
    USE SIGNAL ;
    PORT
      LAYER M4 ;
        RECT  414.636 75.648 414.72 75.672 ;
    END
  END c_i[85]
  PIN c_i[86]
    DIRECTION INPUT ;
    USE SIGNAL ;
    PORT
      LAYER M4 ;
        RECT  414.636 75.792 414.72 75.816 ;
    END
  END c_i[86]
  PIN c_i[87]
    DIRECTION INPUT ;
    USE SIGNAL ;
    PORT
      LAYER M4 ;
        RECT  414.636 75.936 414.72 75.96 ;
    END
  END c_i[87]
  PIN c_i[88]
    DIRECTION INPUT ;
    USE SIGNAL ;
    PORT
      LAYER M4 ;
        RECT  414.636 76.08 414.72 76.104 ;
    END
  END c_i[88]
  PIN c_i[89]
    DIRECTION INPUT ;
    USE SIGNAL ;
    PORT
      LAYER M4 ;
        RECT  414.636 76.224 414.72 76.248 ;
    END
  END c_i[89]
  PIN c_i[8]
    DIRECTION INPUT ;
    USE SIGNAL ;
    PORT
      LAYER M4 ;
        RECT  414.636 64.56 414.72 64.584 ;
    END
  END c_i[8]
  PIN c_i[90]
    DIRECTION INPUT ;
    USE SIGNAL ;
    PORT
      LAYER M4 ;
        RECT  414.636 76.368 414.72 76.392 ;
    END
  END c_i[90]
  PIN c_i[91]
    DIRECTION INPUT ;
    USE SIGNAL ;
    PORT
      LAYER M4 ;
        RECT  414.636 76.512 414.72 76.536 ;
    END
  END c_i[91]
  PIN c_i[92]
    DIRECTION INPUT ;
    USE SIGNAL ;
    PORT
      LAYER M4 ;
        RECT  414.636 76.656 414.72 76.68 ;
    END
  END c_i[92]
  PIN c_i[93]
    DIRECTION INPUT ;
    USE SIGNAL ;
    PORT
      LAYER M4 ;
        RECT  414.636 76.8 414.72 76.824 ;
    END
  END c_i[93]
  PIN c_i[94]
    DIRECTION INPUT ;
    USE SIGNAL ;
    PORT
      LAYER M4 ;
        RECT  414.636 76.944 414.72 76.968 ;
    END
  END c_i[94]
  PIN c_i[95]
    DIRECTION INPUT ;
    USE SIGNAL ;
    PORT
      LAYER M4 ;
        RECT  414.636 77.088 414.72 77.112 ;
    END
  END c_i[95]
  PIN c_i[96]
    DIRECTION INPUT ;
    USE SIGNAL ;
    PORT
      LAYER M4 ;
        RECT  414.636 77.232 414.72 77.256 ;
    END
  END c_i[96]
  PIN c_i[97]
    DIRECTION INPUT ;
    USE SIGNAL ;
    PORT
      LAYER M4 ;
        RECT  414.636 77.376 414.72 77.4 ;
    END
  END c_i[97]
  PIN c_i[98]
    DIRECTION INPUT ;
    USE SIGNAL ;
    PORT
      LAYER M4 ;
        RECT  414.636 77.52 414.72 77.544 ;
    END
  END c_i[98]
  PIN c_i[99]
    DIRECTION INPUT ;
    USE SIGNAL ;
    PORT
      LAYER M4 ;
        RECT  414.636 77.664 414.72 77.688 ;
    END
  END c_i[99]
  PIN c_i[9]
    DIRECTION INPUT ;
    USE SIGNAL ;
    PORT
      LAYER M4 ;
        RECT  414.636 64.704 414.72 64.728 ;
    END
  END c_i[9]
  PIN c_o[0]
    DIRECTION OUTPUT ;
    USE SIGNAL ;
    PORT
      LAYER M4 ;
        RECT  414.636 172.848 414.72 172.872 ;
    END
  END c_o[0]
  PIN c_o[100]
    DIRECTION OUTPUT ;
    USE SIGNAL ;
    PORT
      LAYER M4 ;
        RECT  414.636 187.248 414.72 187.272 ;
    END
  END c_o[100]
  PIN c_o[101]
    DIRECTION OUTPUT ;
    USE SIGNAL ;
    PORT
      LAYER M4 ;
        RECT  414.636 187.392 414.72 187.416 ;
    END
  END c_o[101]
  PIN c_o[102]
    DIRECTION OUTPUT ;
    USE SIGNAL ;
    PORT
      LAYER M4 ;
        RECT  414.636 187.536 414.72 187.56 ;
    END
  END c_o[102]
  PIN c_o[103]
    DIRECTION OUTPUT ;
    USE SIGNAL ;
    PORT
      LAYER M4 ;
        RECT  414.636 187.68 414.72 187.704 ;
    END
  END c_o[103]
  PIN c_o[104]
    DIRECTION OUTPUT ;
    USE SIGNAL ;
    PORT
      LAYER M4 ;
        RECT  414.636 187.824 414.72 187.848 ;
    END
  END c_o[104]
  PIN c_o[105]
    DIRECTION OUTPUT ;
    USE SIGNAL ;
    PORT
      LAYER M4 ;
        RECT  414.636 187.968 414.72 187.992 ;
    END
  END c_o[105]
  PIN c_o[106]
    DIRECTION OUTPUT ;
    USE SIGNAL ;
    PORT
      LAYER M4 ;
        RECT  414.636 188.112 414.72 188.136 ;
    END
  END c_o[106]
  PIN c_o[107]
    DIRECTION OUTPUT ;
    USE SIGNAL ;
    PORT
      LAYER M4 ;
        RECT  414.636 188.256 414.72 188.28 ;
    END
  END c_o[107]
  PIN c_o[108]
    DIRECTION OUTPUT ;
    USE SIGNAL ;
    PORT
      LAYER M4 ;
        RECT  414.636 188.4 414.72 188.424 ;
    END
  END c_o[108]
  PIN c_o[109]
    DIRECTION OUTPUT ;
    USE SIGNAL ;
    PORT
      LAYER M4 ;
        RECT  414.636 188.544 414.72 188.568 ;
    END
  END c_o[109]
  PIN c_o[10]
    DIRECTION OUTPUT ;
    USE SIGNAL ;
    PORT
      LAYER M4 ;
        RECT  414.636 174.288 414.72 174.312 ;
    END
  END c_o[10]
  PIN c_o[110]
    DIRECTION OUTPUT ;
    USE SIGNAL ;
    PORT
      LAYER M4 ;
        RECT  414.636 188.688 414.72 188.712 ;
    END
  END c_o[110]
  PIN c_o[111]
    DIRECTION OUTPUT ;
    USE SIGNAL ;
    PORT
      LAYER M4 ;
        RECT  414.636 188.832 414.72 188.856 ;
    END
  END c_o[111]
  PIN c_o[112]
    DIRECTION OUTPUT ;
    USE SIGNAL ;
    PORT
      LAYER M4 ;
        RECT  414.636 188.976 414.72 189 ;
    END
  END c_o[112]
  PIN c_o[113]
    DIRECTION OUTPUT ;
    USE SIGNAL ;
    PORT
      LAYER M4 ;
        RECT  414.636 189.12 414.72 189.144 ;
    END
  END c_o[113]
  PIN c_o[114]
    DIRECTION OUTPUT ;
    USE SIGNAL ;
    PORT
      LAYER M4 ;
        RECT  414.636 189.264 414.72 189.288 ;
    END
  END c_o[114]
  PIN c_o[115]
    DIRECTION OUTPUT ;
    USE SIGNAL ;
    PORT
      LAYER M4 ;
        RECT  414.636 189.408 414.72 189.432 ;
    END
  END c_o[115]
  PIN c_o[116]
    DIRECTION OUTPUT ;
    USE SIGNAL ;
    PORT
      LAYER M4 ;
        RECT  414.636 189.552 414.72 189.576 ;
    END
  END c_o[116]
  PIN c_o[117]
    DIRECTION OUTPUT ;
    USE SIGNAL ;
    PORT
      LAYER M4 ;
        RECT  414.636 189.696 414.72 189.72 ;
    END
  END c_o[117]
  PIN c_o[118]
    DIRECTION OUTPUT ;
    USE SIGNAL ;
    PORT
      LAYER M4 ;
        RECT  414.636 189.84 414.72 189.864 ;
    END
  END c_o[118]
  PIN c_o[119]
    DIRECTION OUTPUT ;
    USE SIGNAL ;
    PORT
      LAYER M4 ;
        RECT  414.636 189.984 414.72 190.008 ;
    END
  END c_o[119]
  PIN c_o[11]
    DIRECTION OUTPUT ;
    USE SIGNAL ;
    PORT
      LAYER M4 ;
        RECT  414.636 174.432 414.72 174.456 ;
    END
  END c_o[11]
  PIN c_o[120]
    DIRECTION OUTPUT ;
    USE SIGNAL ;
    PORT
      LAYER M4 ;
        RECT  414.636 190.128 414.72 190.152 ;
    END
  END c_o[120]
  PIN c_o[121]
    DIRECTION OUTPUT ;
    USE SIGNAL ;
    PORT
      LAYER M4 ;
        RECT  414.636 190.272 414.72 190.296 ;
    END
  END c_o[121]
  PIN c_o[122]
    DIRECTION OUTPUT ;
    USE SIGNAL ;
    PORT
      LAYER M4 ;
        RECT  414.636 190.416 414.72 190.44 ;
    END
  END c_o[122]
  PIN c_o[123]
    DIRECTION OUTPUT ;
    USE SIGNAL ;
    PORT
      LAYER M4 ;
        RECT  414.636 190.56 414.72 190.584 ;
    END
  END c_o[123]
  PIN c_o[124]
    DIRECTION OUTPUT ;
    USE SIGNAL ;
    PORT
      LAYER M4 ;
        RECT  414.636 190.704 414.72 190.728 ;
    END
  END c_o[124]
  PIN c_o[125]
    DIRECTION OUTPUT ;
    USE SIGNAL ;
    PORT
      LAYER M4 ;
        RECT  414.636 190.848 414.72 190.872 ;
    END
  END c_o[125]
  PIN c_o[126]
    DIRECTION OUTPUT ;
    USE SIGNAL ;
    PORT
      LAYER M4 ;
        RECT  414.636 190.992 414.72 191.016 ;
    END
  END c_o[126]
  PIN c_o[127]
    DIRECTION OUTPUT ;
    USE SIGNAL ;
    PORT
      LAYER M4 ;
        RECT  414.636 191.136 414.72 191.16 ;
    END
  END c_o[127]
  PIN c_o[128]
    DIRECTION OUTPUT ;
    USE SIGNAL ;
    PORT
      LAYER M4 ;
        RECT  414.636 191.28 414.72 191.304 ;
    END
  END c_o[128]
  PIN c_o[129]
    DIRECTION OUTPUT ;
    USE SIGNAL ;
    PORT
      LAYER M4 ;
        RECT  414.636 191.424 414.72 191.448 ;
    END
  END c_o[129]
  PIN c_o[12]
    DIRECTION OUTPUT ;
    USE SIGNAL ;
    PORT
      LAYER M4 ;
        RECT  414.636 174.576 414.72 174.6 ;
    END
  END c_o[12]
  PIN c_o[130]
    DIRECTION OUTPUT ;
    USE SIGNAL ;
    PORT
      LAYER M4 ;
        RECT  414.636 191.568 414.72 191.592 ;
    END
  END c_o[130]
  PIN c_o[131]
    DIRECTION OUTPUT ;
    USE SIGNAL ;
    PORT
      LAYER M4 ;
        RECT  414.636 191.712 414.72 191.736 ;
    END
  END c_o[131]
  PIN c_o[132]
    DIRECTION OUTPUT ;
    USE SIGNAL ;
    PORT
      LAYER M4 ;
        RECT  414.636 191.856 414.72 191.88 ;
    END
  END c_o[132]
  PIN c_o[133]
    DIRECTION OUTPUT ;
    USE SIGNAL ;
    PORT
      LAYER M4 ;
        RECT  414.636 192 414.72 192.024 ;
    END
  END c_o[133]
  PIN c_o[134]
    DIRECTION OUTPUT ;
    USE SIGNAL ;
    PORT
      LAYER M4 ;
        RECT  414.636 192.144 414.72 192.168 ;
    END
  END c_o[134]
  PIN c_o[135]
    DIRECTION OUTPUT ;
    USE SIGNAL ;
    PORT
      LAYER M4 ;
        RECT  414.636 192.288 414.72 192.312 ;
    END
  END c_o[135]
  PIN c_o[136]
    DIRECTION OUTPUT ;
    USE SIGNAL ;
    PORT
      LAYER M4 ;
        RECT  414.636 192.432 414.72 192.456 ;
    END
  END c_o[136]
  PIN c_o[137]
    DIRECTION OUTPUT ;
    USE SIGNAL ;
    PORT
      LAYER M4 ;
        RECT  414.636 192.576 414.72 192.6 ;
    END
  END c_o[137]
  PIN c_o[138]
    DIRECTION OUTPUT ;
    USE SIGNAL ;
    PORT
      LAYER M4 ;
        RECT  414.636 192.72 414.72 192.744 ;
    END
  END c_o[138]
  PIN c_o[139]
    DIRECTION OUTPUT ;
    USE SIGNAL ;
    PORT
      LAYER M4 ;
        RECT  414.636 192.864 414.72 192.888 ;
    END
  END c_o[139]
  PIN c_o[13]
    DIRECTION OUTPUT ;
    USE SIGNAL ;
    PORT
      LAYER M4 ;
        RECT  414.636 174.72 414.72 174.744 ;
    END
  END c_o[13]
  PIN c_o[140]
    DIRECTION OUTPUT ;
    USE SIGNAL ;
    PORT
      LAYER M4 ;
        RECT  414.636 193.008 414.72 193.032 ;
    END
  END c_o[140]
  PIN c_o[141]
    DIRECTION OUTPUT ;
    USE SIGNAL ;
    PORT
      LAYER M4 ;
        RECT  414.636 193.152 414.72 193.176 ;
    END
  END c_o[141]
  PIN c_o[142]
    DIRECTION OUTPUT ;
    USE SIGNAL ;
    PORT
      LAYER M4 ;
        RECT  414.636 193.296 414.72 193.32 ;
    END
  END c_o[142]
  PIN c_o[143]
    DIRECTION OUTPUT ;
    USE SIGNAL ;
    PORT
      LAYER M4 ;
        RECT  414.636 193.44 414.72 193.464 ;
    END
  END c_o[143]
  PIN c_o[144]
    DIRECTION OUTPUT ;
    USE SIGNAL ;
    PORT
      LAYER M4 ;
        RECT  414.636 193.584 414.72 193.608 ;
    END
  END c_o[144]
  PIN c_o[145]
    DIRECTION OUTPUT ;
    USE SIGNAL ;
    PORT
      LAYER M4 ;
        RECT  414.636 193.728 414.72 193.752 ;
    END
  END c_o[145]
  PIN c_o[146]
    DIRECTION OUTPUT ;
    USE SIGNAL ;
    PORT
      LAYER M4 ;
        RECT  414.636 193.872 414.72 193.896 ;
    END
  END c_o[146]
  PIN c_o[147]
    DIRECTION OUTPUT ;
    USE SIGNAL ;
    PORT
      LAYER M4 ;
        RECT  414.636 194.016 414.72 194.04 ;
    END
  END c_o[147]
  PIN c_o[148]
    DIRECTION OUTPUT ;
    USE SIGNAL ;
    PORT
      LAYER M4 ;
        RECT  414.636 194.16 414.72 194.184 ;
    END
  END c_o[148]
  PIN c_o[149]
    DIRECTION OUTPUT ;
    USE SIGNAL ;
    PORT
      LAYER M4 ;
        RECT  414.636 194.304 414.72 194.328 ;
    END
  END c_o[149]
  PIN c_o[14]
    DIRECTION OUTPUT ;
    USE SIGNAL ;
    PORT
      LAYER M4 ;
        RECT  414.636 174.864 414.72 174.888 ;
    END
  END c_o[14]
  PIN c_o[150]
    DIRECTION OUTPUT ;
    USE SIGNAL ;
    PORT
      LAYER M4 ;
        RECT  414.636 194.448 414.72 194.472 ;
    END
  END c_o[150]
  PIN c_o[151]
    DIRECTION OUTPUT ;
    USE SIGNAL ;
    PORT
      LAYER M4 ;
        RECT  414.636 194.592 414.72 194.616 ;
    END
  END c_o[151]
  PIN c_o[152]
    DIRECTION OUTPUT ;
    USE SIGNAL ;
    PORT
      LAYER M4 ;
        RECT  414.636 194.736 414.72 194.76 ;
    END
  END c_o[152]
  PIN c_o[153]
    DIRECTION OUTPUT ;
    USE SIGNAL ;
    PORT
      LAYER M4 ;
        RECT  414.636 194.88 414.72 194.904 ;
    END
  END c_o[153]
  PIN c_o[154]
    DIRECTION OUTPUT ;
    USE SIGNAL ;
    PORT
      LAYER M4 ;
        RECT  414.636 195.024 414.72 195.048 ;
    END
  END c_o[154]
  PIN c_o[155]
    DIRECTION OUTPUT ;
    USE SIGNAL ;
    PORT
      LAYER M4 ;
        RECT  414.636 195.168 414.72 195.192 ;
    END
  END c_o[155]
  PIN c_o[156]
    DIRECTION OUTPUT ;
    USE SIGNAL ;
    PORT
      LAYER M4 ;
        RECT  414.636 195.312 414.72 195.336 ;
    END
  END c_o[156]
  PIN c_o[157]
    DIRECTION OUTPUT ;
    USE SIGNAL ;
    PORT
      LAYER M4 ;
        RECT  414.636 195.456 414.72 195.48 ;
    END
  END c_o[157]
  PIN c_o[158]
    DIRECTION OUTPUT ;
    USE SIGNAL ;
    PORT
      LAYER M4 ;
        RECT  414.636 195.6 414.72 195.624 ;
    END
  END c_o[158]
  PIN c_o[159]
    DIRECTION OUTPUT ;
    USE SIGNAL ;
    PORT
      LAYER M4 ;
        RECT  414.636 195.744 414.72 195.768 ;
    END
  END c_o[159]
  PIN c_o[15]
    DIRECTION OUTPUT ;
    USE SIGNAL ;
    PORT
      LAYER M4 ;
        RECT  414.636 175.008 414.72 175.032 ;
    END
  END c_o[15]
  PIN c_o[160]
    DIRECTION OUTPUT ;
    USE SIGNAL ;
    PORT
      LAYER M4 ;
        RECT  414.636 195.888 414.72 195.912 ;
    END
  END c_o[160]
  PIN c_o[161]
    DIRECTION OUTPUT ;
    USE SIGNAL ;
    PORT
      LAYER M4 ;
        RECT  414.636 196.032 414.72 196.056 ;
    END
  END c_o[161]
  PIN c_o[162]
    DIRECTION OUTPUT ;
    USE SIGNAL ;
    PORT
      LAYER M4 ;
        RECT  414.636 196.176 414.72 196.2 ;
    END
  END c_o[162]
  PIN c_o[163]
    DIRECTION OUTPUT ;
    USE SIGNAL ;
    PORT
      LAYER M4 ;
        RECT  414.636 196.32 414.72 196.344 ;
    END
  END c_o[163]
  PIN c_o[164]
    DIRECTION OUTPUT ;
    USE SIGNAL ;
    PORT
      LAYER M4 ;
        RECT  414.636 196.464 414.72 196.488 ;
    END
  END c_o[164]
  PIN c_o[165]
    DIRECTION OUTPUT ;
    USE SIGNAL ;
    PORT
      LAYER M4 ;
        RECT  414.636 196.608 414.72 196.632 ;
    END
  END c_o[165]
  PIN c_o[166]
    DIRECTION OUTPUT ;
    USE SIGNAL ;
    PORT
      LAYER M4 ;
        RECT  414.636 196.752 414.72 196.776 ;
    END
  END c_o[166]
  PIN c_o[167]
    DIRECTION OUTPUT ;
    USE SIGNAL ;
    PORT
      LAYER M4 ;
        RECT  414.636 196.896 414.72 196.92 ;
    END
  END c_o[167]
  PIN c_o[168]
    DIRECTION OUTPUT ;
    USE SIGNAL ;
    PORT
      LAYER M4 ;
        RECT  414.636 197.04 414.72 197.064 ;
    END
  END c_o[168]
  PIN c_o[169]
    DIRECTION OUTPUT ;
    USE SIGNAL ;
    PORT
      LAYER M4 ;
        RECT  414.636 197.184 414.72 197.208 ;
    END
  END c_o[169]
  PIN c_o[16]
    DIRECTION OUTPUT ;
    USE SIGNAL ;
    PORT
      LAYER M4 ;
        RECT  414.636 175.152 414.72 175.176 ;
    END
  END c_o[16]
  PIN c_o[170]
    DIRECTION OUTPUT ;
    USE SIGNAL ;
    PORT
      LAYER M4 ;
        RECT  414.636 197.328 414.72 197.352 ;
    END
  END c_o[170]
  PIN c_o[171]
    DIRECTION OUTPUT ;
    USE SIGNAL ;
    PORT
      LAYER M4 ;
        RECT  414.636 197.472 414.72 197.496 ;
    END
  END c_o[171]
  PIN c_o[172]
    DIRECTION OUTPUT ;
    USE SIGNAL ;
    PORT
      LAYER M4 ;
        RECT  414.636 197.616 414.72 197.64 ;
    END
  END c_o[172]
  PIN c_o[173]
    DIRECTION OUTPUT ;
    USE SIGNAL ;
    PORT
      LAYER M4 ;
        RECT  414.636 197.76 414.72 197.784 ;
    END
  END c_o[173]
  PIN c_o[174]
    DIRECTION OUTPUT ;
    USE SIGNAL ;
    PORT
      LAYER M4 ;
        RECT  414.636 197.904 414.72 197.928 ;
    END
  END c_o[174]
  PIN c_o[175]
    DIRECTION OUTPUT ;
    USE SIGNAL ;
    PORT
      LAYER M4 ;
        RECT  414.636 198.048 414.72 198.072 ;
    END
  END c_o[175]
  PIN c_o[176]
    DIRECTION OUTPUT ;
    USE SIGNAL ;
    PORT
      LAYER M4 ;
        RECT  414.636 198.192 414.72 198.216 ;
    END
  END c_o[176]
  PIN c_o[177]
    DIRECTION OUTPUT ;
    USE SIGNAL ;
    PORT
      LAYER M4 ;
        RECT  414.636 198.336 414.72 198.36 ;
    END
  END c_o[177]
  PIN c_o[178]
    DIRECTION OUTPUT ;
    USE SIGNAL ;
    PORT
      LAYER M4 ;
        RECT  414.636 198.48 414.72 198.504 ;
    END
  END c_o[178]
  PIN c_o[179]
    DIRECTION OUTPUT ;
    USE SIGNAL ;
    PORT
      LAYER M4 ;
        RECT  414.636 198.624 414.72 198.648 ;
    END
  END c_o[179]
  PIN c_o[17]
    DIRECTION OUTPUT ;
    USE SIGNAL ;
    PORT
      LAYER M4 ;
        RECT  414.636 175.296 414.72 175.32 ;
    END
  END c_o[17]
  PIN c_o[180]
    DIRECTION OUTPUT ;
    USE SIGNAL ;
    PORT
      LAYER M4 ;
        RECT  414.636 198.768 414.72 198.792 ;
    END
  END c_o[180]
  PIN c_o[181]
    DIRECTION OUTPUT ;
    USE SIGNAL ;
    PORT
      LAYER M4 ;
        RECT  414.636 198.912 414.72 198.936 ;
    END
  END c_o[181]
  PIN c_o[182]
    DIRECTION OUTPUT ;
    USE SIGNAL ;
    PORT
      LAYER M4 ;
        RECT  414.636 199.056 414.72 199.08 ;
    END
  END c_o[182]
  PIN c_o[183]
    DIRECTION OUTPUT ;
    USE SIGNAL ;
    PORT
      LAYER M4 ;
        RECT  414.636 199.2 414.72 199.224 ;
    END
  END c_o[183]
  PIN c_o[184]
    DIRECTION OUTPUT ;
    USE SIGNAL ;
    PORT
      LAYER M4 ;
        RECT  414.636 199.344 414.72 199.368 ;
    END
  END c_o[184]
  PIN c_o[185]
    DIRECTION OUTPUT ;
    USE SIGNAL ;
    PORT
      LAYER M4 ;
        RECT  414.636 199.488 414.72 199.512 ;
    END
  END c_o[185]
  PIN c_o[186]
    DIRECTION OUTPUT ;
    USE SIGNAL ;
    PORT
      LAYER M4 ;
        RECT  414.636 199.632 414.72 199.656 ;
    END
  END c_o[186]
  PIN c_o[187]
    DIRECTION OUTPUT ;
    USE SIGNAL ;
    PORT
      LAYER M4 ;
        RECT  414.636 199.776 414.72 199.8 ;
    END
  END c_o[187]
  PIN c_o[188]
    DIRECTION OUTPUT ;
    USE SIGNAL ;
    PORT
      LAYER M4 ;
        RECT  414.636 199.92 414.72 199.944 ;
    END
  END c_o[188]
  PIN c_o[189]
    DIRECTION OUTPUT ;
    USE SIGNAL ;
    PORT
      LAYER M4 ;
        RECT  414.636 200.064 414.72 200.088 ;
    END
  END c_o[189]
  PIN c_o[18]
    DIRECTION OUTPUT ;
    USE SIGNAL ;
    PORT
      LAYER M4 ;
        RECT  414.636 175.44 414.72 175.464 ;
    END
  END c_o[18]
  PIN c_o[190]
    DIRECTION OUTPUT ;
    USE SIGNAL ;
    PORT
      LAYER M4 ;
        RECT  414.636 200.208 414.72 200.232 ;
    END
  END c_o[190]
  PIN c_o[191]
    DIRECTION OUTPUT ;
    USE SIGNAL ;
    PORT
      LAYER M4 ;
        RECT  414.636 200.352 414.72 200.376 ;
    END
  END c_o[191]
  PIN c_o[192]
    DIRECTION OUTPUT ;
    USE SIGNAL ;
    PORT
      LAYER M4 ;
        RECT  414.636 200.496 414.72 200.52 ;
    END
  END c_o[192]
  PIN c_o[193]
    DIRECTION OUTPUT ;
    USE SIGNAL ;
    PORT
      LAYER M4 ;
        RECT  414.636 200.64 414.72 200.664 ;
    END
  END c_o[193]
  PIN c_o[194]
    DIRECTION OUTPUT ;
    USE SIGNAL ;
    PORT
      LAYER M4 ;
        RECT  414.636 200.784 414.72 200.808 ;
    END
  END c_o[194]
  PIN c_o[195]
    DIRECTION OUTPUT ;
    USE SIGNAL ;
    PORT
      LAYER M4 ;
        RECT  414.636 200.928 414.72 200.952 ;
    END
  END c_o[195]
  PIN c_o[196]
    DIRECTION OUTPUT ;
    USE SIGNAL ;
    PORT
      LAYER M4 ;
        RECT  414.636 201.072 414.72 201.096 ;
    END
  END c_o[196]
  PIN c_o[197]
    DIRECTION OUTPUT ;
    USE SIGNAL ;
    PORT
      LAYER M4 ;
        RECT  414.636 201.216 414.72 201.24 ;
    END
  END c_o[197]
  PIN c_o[198]
    DIRECTION OUTPUT ;
    USE SIGNAL ;
    PORT
      LAYER M4 ;
        RECT  414.636 201.36 414.72 201.384 ;
    END
  END c_o[198]
  PIN c_o[199]
    DIRECTION OUTPUT ;
    USE SIGNAL ;
    PORT
      LAYER M4 ;
        RECT  414.636 201.504 414.72 201.528 ;
    END
  END c_o[199]
  PIN c_o[19]
    DIRECTION OUTPUT ;
    USE SIGNAL ;
    PORT
      LAYER M4 ;
        RECT  414.636 175.584 414.72 175.608 ;
    END
  END c_o[19]
  PIN c_o[1]
    DIRECTION OUTPUT ;
    USE SIGNAL ;
    PORT
      LAYER M4 ;
        RECT  414.636 172.992 414.72 173.016 ;
    END
  END c_o[1]
  PIN c_o[200]
    DIRECTION OUTPUT ;
    USE SIGNAL ;
    PORT
      LAYER M4 ;
        RECT  414.636 201.648 414.72 201.672 ;
    END
  END c_o[200]
  PIN c_o[201]
    DIRECTION OUTPUT ;
    USE SIGNAL ;
    PORT
      LAYER M4 ;
        RECT  414.636 201.792 414.72 201.816 ;
    END
  END c_o[201]
  PIN c_o[202]
    DIRECTION OUTPUT ;
    USE SIGNAL ;
    PORT
      LAYER M4 ;
        RECT  414.636 201.936 414.72 201.96 ;
    END
  END c_o[202]
  PIN c_o[203]
    DIRECTION OUTPUT ;
    USE SIGNAL ;
    PORT
      LAYER M4 ;
        RECT  414.636 202.08 414.72 202.104 ;
    END
  END c_o[203]
  PIN c_o[204]
    DIRECTION OUTPUT ;
    USE SIGNAL ;
    PORT
      LAYER M4 ;
        RECT  414.636 202.224 414.72 202.248 ;
    END
  END c_o[204]
  PIN c_o[205]
    DIRECTION OUTPUT ;
    USE SIGNAL ;
    PORT
      LAYER M4 ;
        RECT  414.636 202.368 414.72 202.392 ;
    END
  END c_o[205]
  PIN c_o[206]
    DIRECTION OUTPUT ;
    USE SIGNAL ;
    PORT
      LAYER M4 ;
        RECT  414.636 202.512 414.72 202.536 ;
    END
  END c_o[206]
  PIN c_o[207]
    DIRECTION OUTPUT ;
    USE SIGNAL ;
    PORT
      LAYER M4 ;
        RECT  414.636 202.656 414.72 202.68 ;
    END
  END c_o[207]
  PIN c_o[208]
    DIRECTION OUTPUT ;
    USE SIGNAL ;
    PORT
      LAYER M4 ;
        RECT  414.636 202.8 414.72 202.824 ;
    END
  END c_o[208]
  PIN c_o[209]
    DIRECTION OUTPUT ;
    USE SIGNAL ;
    PORT
      LAYER M4 ;
        RECT  414.636 202.944 414.72 202.968 ;
    END
  END c_o[209]
  PIN c_o[20]
    DIRECTION OUTPUT ;
    USE SIGNAL ;
    PORT
      LAYER M4 ;
        RECT  414.636 175.728 414.72 175.752 ;
    END
  END c_o[20]
  PIN c_o[210]
    DIRECTION OUTPUT ;
    USE SIGNAL ;
    PORT
      LAYER M4 ;
        RECT  414.636 203.088 414.72 203.112 ;
    END
  END c_o[210]
  PIN c_o[211]
    DIRECTION OUTPUT ;
    USE SIGNAL ;
    PORT
      LAYER M4 ;
        RECT  414.636 203.232 414.72 203.256 ;
    END
  END c_o[211]
  PIN c_o[212]
    DIRECTION OUTPUT ;
    USE SIGNAL ;
    PORT
      LAYER M4 ;
        RECT  414.636 203.376 414.72 203.4 ;
    END
  END c_o[212]
  PIN c_o[213]
    DIRECTION OUTPUT ;
    USE SIGNAL ;
    PORT
      LAYER M4 ;
        RECT  414.636 203.52 414.72 203.544 ;
    END
  END c_o[213]
  PIN c_o[214]
    DIRECTION OUTPUT ;
    USE SIGNAL ;
    PORT
      LAYER M4 ;
        RECT  414.636 203.664 414.72 203.688 ;
    END
  END c_o[214]
  PIN c_o[215]
    DIRECTION OUTPUT ;
    USE SIGNAL ;
    PORT
      LAYER M4 ;
        RECT  414.636 203.808 414.72 203.832 ;
    END
  END c_o[215]
  PIN c_o[216]
    DIRECTION OUTPUT ;
    USE SIGNAL ;
    PORT
      LAYER M4 ;
        RECT  414.636 203.952 414.72 203.976 ;
    END
  END c_o[216]
  PIN c_o[217]
    DIRECTION OUTPUT ;
    USE SIGNAL ;
    PORT
      LAYER M4 ;
        RECT  414.636 204.096 414.72 204.12 ;
    END
  END c_o[217]
  PIN c_o[218]
    DIRECTION OUTPUT ;
    USE SIGNAL ;
    PORT
      LAYER M4 ;
        RECT  414.636 204.24 414.72 204.264 ;
    END
  END c_o[218]
  PIN c_o[219]
    DIRECTION OUTPUT ;
    USE SIGNAL ;
    PORT
      LAYER M5 ;
        RECT  194.976 267.756 195 267.84 ;
    END
  END c_o[219]
  PIN c_o[21]
    DIRECTION OUTPUT ;
    USE SIGNAL ;
    PORT
      LAYER M4 ;
        RECT  414.636 175.872 414.72 175.896 ;
    END
  END c_o[21]
  PIN c_o[220]
    DIRECTION OUTPUT ;
    USE SIGNAL ;
    PORT
      LAYER M5 ;
        RECT  195.12 267.756 195.144 267.84 ;
    END
  END c_o[220]
  PIN c_o[221]
    DIRECTION OUTPUT ;
    USE SIGNAL ;
    PORT
      LAYER M5 ;
        RECT  195.264 267.756 195.288 267.84 ;
    END
  END c_o[221]
  PIN c_o[222]
    DIRECTION OUTPUT ;
    USE SIGNAL ;
    PORT
      LAYER M5 ;
        RECT  195.408 267.756 195.432 267.84 ;
    END
  END c_o[222]
  PIN c_o[223]
    DIRECTION OUTPUT ;
    USE SIGNAL ;
    PORT
      LAYER M5 ;
        RECT  195.552 267.756 195.576 267.84 ;
    END
  END c_o[223]
  PIN c_o[224]
    DIRECTION OUTPUT ;
    USE SIGNAL ;
    PORT
      LAYER M5 ;
        RECT  195.696 267.756 195.72 267.84 ;
    END
  END c_o[224]
  PIN c_o[225]
    DIRECTION OUTPUT ;
    USE SIGNAL ;
    PORT
      LAYER M5 ;
        RECT  195.84 267.756 195.864 267.84 ;
    END
  END c_o[225]
  PIN c_o[226]
    DIRECTION OUTPUT ;
    USE SIGNAL ;
    PORT
      LAYER M5 ;
        RECT  195.984 267.756 196.008 267.84 ;
    END
  END c_o[226]
  PIN c_o[227]
    DIRECTION OUTPUT ;
    USE SIGNAL ;
    PORT
      LAYER M5 ;
        RECT  196.128 267.756 196.152 267.84 ;
    END
  END c_o[227]
  PIN c_o[228]
    DIRECTION OUTPUT ;
    USE SIGNAL ;
    PORT
      LAYER M5 ;
        RECT  196.272 267.756 196.296 267.84 ;
    END
  END c_o[228]
  PIN c_o[229]
    DIRECTION OUTPUT ;
    USE SIGNAL ;
    PORT
      LAYER M5 ;
        RECT  196.416 267.756 196.44 267.84 ;
    END
  END c_o[229]
  PIN c_o[22]
    DIRECTION OUTPUT ;
    USE SIGNAL ;
    PORT
      LAYER M4 ;
        RECT  414.636 176.016 414.72 176.04 ;
    END
  END c_o[22]
  PIN c_o[230]
    DIRECTION OUTPUT ;
    USE SIGNAL ;
    PORT
      LAYER M5 ;
        RECT  196.56 267.756 196.584 267.84 ;
    END
  END c_o[230]
  PIN c_o[231]
    DIRECTION OUTPUT ;
    USE SIGNAL ;
    PORT
      LAYER M5 ;
        RECT  196.704 267.756 196.728 267.84 ;
    END
  END c_o[231]
  PIN c_o[232]
    DIRECTION OUTPUT ;
    USE SIGNAL ;
    PORT
      LAYER M5 ;
        RECT  196.848 267.756 196.872 267.84 ;
    END
  END c_o[232]
  PIN c_o[233]
    DIRECTION OUTPUT ;
    USE SIGNAL ;
    PORT
      LAYER M5 ;
        RECT  196.992 267.756 197.016 267.84 ;
    END
  END c_o[233]
  PIN c_o[234]
    DIRECTION OUTPUT ;
    USE SIGNAL ;
    PORT
      LAYER M5 ;
        RECT  197.136 267.756 197.16 267.84 ;
    END
  END c_o[234]
  PIN c_o[235]
    DIRECTION OUTPUT ;
    USE SIGNAL ;
    PORT
      LAYER M5 ;
        RECT  197.28 267.756 197.304 267.84 ;
    END
  END c_o[235]
  PIN c_o[236]
    DIRECTION OUTPUT ;
    USE SIGNAL ;
    PORT
      LAYER M5 ;
        RECT  197.424 267.756 197.448 267.84 ;
    END
  END c_o[236]
  PIN c_o[237]
    DIRECTION OUTPUT ;
    USE SIGNAL ;
    PORT
      LAYER M5 ;
        RECT  197.568 267.756 197.592 267.84 ;
    END
  END c_o[237]
  PIN c_o[238]
    DIRECTION OUTPUT ;
    USE SIGNAL ;
    PORT
      LAYER M5 ;
        RECT  197.712 267.756 197.736 267.84 ;
    END
  END c_o[238]
  PIN c_o[239]
    DIRECTION OUTPUT ;
    USE SIGNAL ;
    PORT
      LAYER M5 ;
        RECT  197.856 267.756 197.88 267.84 ;
    END
  END c_o[239]
  PIN c_o[23]
    DIRECTION OUTPUT ;
    USE SIGNAL ;
    PORT
      LAYER M4 ;
        RECT  414.636 176.16 414.72 176.184 ;
    END
  END c_o[23]
  PIN c_o[240]
    DIRECTION OUTPUT ;
    USE SIGNAL ;
    PORT
      LAYER M5 ;
        RECT  198 267.756 198.024 267.84 ;
    END
  END c_o[240]
  PIN c_o[241]
    DIRECTION OUTPUT ;
    USE SIGNAL ;
    PORT
      LAYER M5 ;
        RECT  198.144 267.756 198.168 267.84 ;
    END
  END c_o[241]
  PIN c_o[242]
    DIRECTION OUTPUT ;
    USE SIGNAL ;
    PORT
      LAYER M5 ;
        RECT  198.288 267.756 198.312 267.84 ;
    END
  END c_o[242]
  PIN c_o[243]
    DIRECTION OUTPUT ;
    USE SIGNAL ;
    PORT
      LAYER M5 ;
        RECT  198.432 267.756 198.456 267.84 ;
    END
  END c_o[243]
  PIN c_o[244]
    DIRECTION OUTPUT ;
    USE SIGNAL ;
    PORT
      LAYER M5 ;
        RECT  198.576 267.756 198.6 267.84 ;
    END
  END c_o[244]
  PIN c_o[245]
    DIRECTION OUTPUT ;
    USE SIGNAL ;
    PORT
      LAYER M5 ;
        RECT  198.72 267.756 198.744 267.84 ;
    END
  END c_o[245]
  PIN c_o[246]
    DIRECTION OUTPUT ;
    USE SIGNAL ;
    PORT
      LAYER M5 ;
        RECT  198.864 267.756 198.888 267.84 ;
    END
  END c_o[246]
  PIN c_o[247]
    DIRECTION OUTPUT ;
    USE SIGNAL ;
    PORT
      LAYER M5 ;
        RECT  199.008 267.756 199.032 267.84 ;
    END
  END c_o[247]
  PIN c_o[24]
    DIRECTION OUTPUT ;
    USE SIGNAL ;
    PORT
      LAYER M4 ;
        RECT  414.636 176.304 414.72 176.328 ;
    END
  END c_o[24]
  PIN c_o[25]
    DIRECTION OUTPUT ;
    USE SIGNAL ;
    PORT
      LAYER M4 ;
        RECT  414.636 176.448 414.72 176.472 ;
    END
  END c_o[25]
  PIN c_o[26]
    DIRECTION OUTPUT ;
    USE SIGNAL ;
    PORT
      LAYER M4 ;
        RECT  414.636 176.592 414.72 176.616 ;
    END
  END c_o[26]
  PIN c_o[27]
    DIRECTION OUTPUT ;
    USE SIGNAL ;
    PORT
      LAYER M4 ;
        RECT  414.636 176.736 414.72 176.76 ;
    END
  END c_o[27]
  PIN c_o[28]
    DIRECTION OUTPUT ;
    USE SIGNAL ;
    PORT
      LAYER M4 ;
        RECT  414.636 176.88 414.72 176.904 ;
    END
  END c_o[28]
  PIN c_o[29]
    DIRECTION OUTPUT ;
    USE SIGNAL ;
    PORT
      LAYER M4 ;
        RECT  414.636 177.024 414.72 177.048 ;
    END
  END c_o[29]
  PIN c_o[2]
    DIRECTION OUTPUT ;
    USE SIGNAL ;
    PORT
      LAYER M4 ;
        RECT  414.636 173.136 414.72 173.16 ;
    END
  END c_o[2]
  PIN c_o[30]
    DIRECTION OUTPUT ;
    USE SIGNAL ;
    PORT
      LAYER M4 ;
        RECT  414.636 177.168 414.72 177.192 ;
    END
  END c_o[30]
  PIN c_o[31]
    DIRECTION OUTPUT ;
    USE SIGNAL ;
    PORT
      LAYER M4 ;
        RECT  414.636 177.312 414.72 177.336 ;
    END
  END c_o[31]
  PIN c_o[32]
    DIRECTION OUTPUT ;
    USE SIGNAL ;
    PORT
      LAYER M4 ;
        RECT  414.636 177.456 414.72 177.48 ;
    END
  END c_o[32]
  PIN c_o[33]
    DIRECTION OUTPUT ;
    USE SIGNAL ;
    PORT
      LAYER M4 ;
        RECT  414.636 177.6 414.72 177.624 ;
    END
  END c_o[33]
  PIN c_o[34]
    DIRECTION OUTPUT ;
    USE SIGNAL ;
    PORT
      LAYER M4 ;
        RECT  414.636 177.744 414.72 177.768 ;
    END
  END c_o[34]
  PIN c_o[35]
    DIRECTION OUTPUT ;
    USE SIGNAL ;
    PORT
      LAYER M4 ;
        RECT  414.636 177.888 414.72 177.912 ;
    END
  END c_o[35]
  PIN c_o[36]
    DIRECTION OUTPUT ;
    USE SIGNAL ;
    PORT
      LAYER M4 ;
        RECT  414.636 178.032 414.72 178.056 ;
    END
  END c_o[36]
  PIN c_o[37]
    DIRECTION OUTPUT ;
    USE SIGNAL ;
    PORT
      LAYER M4 ;
        RECT  414.636 178.176 414.72 178.2 ;
    END
  END c_o[37]
  PIN c_o[38]
    DIRECTION OUTPUT ;
    USE SIGNAL ;
    PORT
      LAYER M4 ;
        RECT  414.636 178.32 414.72 178.344 ;
    END
  END c_o[38]
  PIN c_o[39]
    DIRECTION OUTPUT ;
    USE SIGNAL ;
    PORT
      LAYER M4 ;
        RECT  414.636 178.464 414.72 178.488 ;
    END
  END c_o[39]
  PIN c_o[3]
    DIRECTION OUTPUT ;
    USE SIGNAL ;
    PORT
      LAYER M4 ;
        RECT  414.636 173.28 414.72 173.304 ;
    END
  END c_o[3]
  PIN c_o[40]
    DIRECTION OUTPUT ;
    USE SIGNAL ;
    PORT
      LAYER M4 ;
        RECT  414.636 178.608 414.72 178.632 ;
    END
  END c_o[40]
  PIN c_o[41]
    DIRECTION OUTPUT ;
    USE SIGNAL ;
    PORT
      LAYER M4 ;
        RECT  414.636 178.752 414.72 178.776 ;
    END
  END c_o[41]
  PIN c_o[42]
    DIRECTION OUTPUT ;
    USE SIGNAL ;
    PORT
      LAYER M4 ;
        RECT  414.636 178.896 414.72 178.92 ;
    END
  END c_o[42]
  PIN c_o[43]
    DIRECTION OUTPUT ;
    USE SIGNAL ;
    PORT
      LAYER M4 ;
        RECT  414.636 179.04 414.72 179.064 ;
    END
  END c_o[43]
  PIN c_o[44]
    DIRECTION OUTPUT ;
    USE SIGNAL ;
    PORT
      LAYER M4 ;
        RECT  414.636 179.184 414.72 179.208 ;
    END
  END c_o[44]
  PIN c_o[45]
    DIRECTION OUTPUT ;
    USE SIGNAL ;
    PORT
      LAYER M4 ;
        RECT  414.636 179.328 414.72 179.352 ;
    END
  END c_o[45]
  PIN c_o[46]
    DIRECTION OUTPUT ;
    USE SIGNAL ;
    PORT
      LAYER M4 ;
        RECT  414.636 179.472 414.72 179.496 ;
    END
  END c_o[46]
  PIN c_o[47]
    DIRECTION OUTPUT ;
    USE SIGNAL ;
    PORT
      LAYER M4 ;
        RECT  414.636 179.616 414.72 179.64 ;
    END
  END c_o[47]
  PIN c_o[48]
    DIRECTION OUTPUT ;
    USE SIGNAL ;
    PORT
      LAYER M4 ;
        RECT  414.636 179.76 414.72 179.784 ;
    END
  END c_o[48]
  PIN c_o[49]
    DIRECTION OUTPUT ;
    USE SIGNAL ;
    PORT
      LAYER M4 ;
        RECT  414.636 179.904 414.72 179.928 ;
    END
  END c_o[49]
  PIN c_o[4]
    DIRECTION OUTPUT ;
    USE SIGNAL ;
    PORT
      LAYER M4 ;
        RECT  414.636 173.424 414.72 173.448 ;
    END
  END c_o[4]
  PIN c_o[50]
    DIRECTION OUTPUT ;
    USE SIGNAL ;
    PORT
      LAYER M4 ;
        RECT  414.636 180.048 414.72 180.072 ;
    END
  END c_o[50]
  PIN c_o[51]
    DIRECTION OUTPUT ;
    USE SIGNAL ;
    PORT
      LAYER M4 ;
        RECT  414.636 180.192 414.72 180.216 ;
    END
  END c_o[51]
  PIN c_o[52]
    DIRECTION OUTPUT ;
    USE SIGNAL ;
    PORT
      LAYER M4 ;
        RECT  414.636 180.336 414.72 180.36 ;
    END
  END c_o[52]
  PIN c_o[53]
    DIRECTION OUTPUT ;
    USE SIGNAL ;
    PORT
      LAYER M4 ;
        RECT  414.636 180.48 414.72 180.504 ;
    END
  END c_o[53]
  PIN c_o[54]
    DIRECTION OUTPUT ;
    USE SIGNAL ;
    PORT
      LAYER M4 ;
        RECT  414.636 180.624 414.72 180.648 ;
    END
  END c_o[54]
  PIN c_o[55]
    DIRECTION OUTPUT ;
    USE SIGNAL ;
    PORT
      LAYER M4 ;
        RECT  414.636 180.768 414.72 180.792 ;
    END
  END c_o[55]
  PIN c_o[56]
    DIRECTION OUTPUT ;
    USE SIGNAL ;
    PORT
      LAYER M4 ;
        RECT  414.636 180.912 414.72 180.936 ;
    END
  END c_o[56]
  PIN c_o[57]
    DIRECTION OUTPUT ;
    USE SIGNAL ;
    PORT
      LAYER M4 ;
        RECT  414.636 181.056 414.72 181.08 ;
    END
  END c_o[57]
  PIN c_o[58]
    DIRECTION OUTPUT ;
    USE SIGNAL ;
    PORT
      LAYER M4 ;
        RECT  414.636 181.2 414.72 181.224 ;
    END
  END c_o[58]
  PIN c_o[59]
    DIRECTION OUTPUT ;
    USE SIGNAL ;
    PORT
      LAYER M4 ;
        RECT  414.636 181.344 414.72 181.368 ;
    END
  END c_o[59]
  PIN c_o[5]
    DIRECTION OUTPUT ;
    USE SIGNAL ;
    PORT
      LAYER M4 ;
        RECT  414.636 173.568 414.72 173.592 ;
    END
  END c_o[5]
  PIN c_o[60]
    DIRECTION OUTPUT ;
    USE SIGNAL ;
    PORT
      LAYER M4 ;
        RECT  414.636 181.488 414.72 181.512 ;
    END
  END c_o[60]
  PIN c_o[61]
    DIRECTION OUTPUT ;
    USE SIGNAL ;
    PORT
      LAYER M4 ;
        RECT  414.636 181.632 414.72 181.656 ;
    END
  END c_o[61]
  PIN c_o[62]
    DIRECTION OUTPUT ;
    USE SIGNAL ;
    PORT
      LAYER M4 ;
        RECT  414.636 181.776 414.72 181.8 ;
    END
  END c_o[62]
  PIN c_o[63]
    DIRECTION OUTPUT ;
    USE SIGNAL ;
    PORT
      LAYER M4 ;
        RECT  414.636 181.92 414.72 181.944 ;
    END
  END c_o[63]
  PIN c_o[64]
    DIRECTION OUTPUT ;
    USE SIGNAL ;
    PORT
      LAYER M4 ;
        RECT  414.636 182.064 414.72 182.088 ;
    END
  END c_o[64]
  PIN c_o[65]
    DIRECTION OUTPUT ;
    USE SIGNAL ;
    PORT
      LAYER M4 ;
        RECT  414.636 182.208 414.72 182.232 ;
    END
  END c_o[65]
  PIN c_o[66]
    DIRECTION OUTPUT ;
    USE SIGNAL ;
    PORT
      LAYER M4 ;
        RECT  414.636 182.352 414.72 182.376 ;
    END
  END c_o[66]
  PIN c_o[67]
    DIRECTION OUTPUT ;
    USE SIGNAL ;
    PORT
      LAYER M4 ;
        RECT  414.636 182.496 414.72 182.52 ;
    END
  END c_o[67]
  PIN c_o[68]
    DIRECTION OUTPUT ;
    USE SIGNAL ;
    PORT
      LAYER M4 ;
        RECT  414.636 182.64 414.72 182.664 ;
    END
  END c_o[68]
  PIN c_o[69]
    DIRECTION OUTPUT ;
    USE SIGNAL ;
    PORT
      LAYER M4 ;
        RECT  414.636 182.784 414.72 182.808 ;
    END
  END c_o[69]
  PIN c_o[6]
    DIRECTION OUTPUT ;
    USE SIGNAL ;
    PORT
      LAYER M4 ;
        RECT  414.636 173.712 414.72 173.736 ;
    END
  END c_o[6]
  PIN c_o[70]
    DIRECTION OUTPUT ;
    USE SIGNAL ;
    PORT
      LAYER M4 ;
        RECT  414.636 182.928 414.72 182.952 ;
    END
  END c_o[70]
  PIN c_o[71]
    DIRECTION OUTPUT ;
    USE SIGNAL ;
    PORT
      LAYER M4 ;
        RECT  414.636 183.072 414.72 183.096 ;
    END
  END c_o[71]
  PIN c_o[72]
    DIRECTION OUTPUT ;
    USE SIGNAL ;
    PORT
      LAYER M4 ;
        RECT  414.636 183.216 414.72 183.24 ;
    END
  END c_o[72]
  PIN c_o[73]
    DIRECTION OUTPUT ;
    USE SIGNAL ;
    PORT
      LAYER M4 ;
        RECT  414.636 183.36 414.72 183.384 ;
    END
  END c_o[73]
  PIN c_o[74]
    DIRECTION OUTPUT ;
    USE SIGNAL ;
    PORT
      LAYER M4 ;
        RECT  414.636 183.504 414.72 183.528 ;
    END
  END c_o[74]
  PIN c_o[75]
    DIRECTION OUTPUT ;
    USE SIGNAL ;
    PORT
      LAYER M4 ;
        RECT  414.636 183.648 414.72 183.672 ;
    END
  END c_o[75]
  PIN c_o[76]
    DIRECTION OUTPUT ;
    USE SIGNAL ;
    PORT
      LAYER M4 ;
        RECT  414.636 183.792 414.72 183.816 ;
    END
  END c_o[76]
  PIN c_o[77]
    DIRECTION OUTPUT ;
    USE SIGNAL ;
    PORT
      LAYER M4 ;
        RECT  414.636 183.936 414.72 183.96 ;
    END
  END c_o[77]
  PIN c_o[78]
    DIRECTION OUTPUT ;
    USE SIGNAL ;
    PORT
      LAYER M4 ;
        RECT  414.636 184.08 414.72 184.104 ;
    END
  END c_o[78]
  PIN c_o[79]
    DIRECTION OUTPUT ;
    USE SIGNAL ;
    PORT
      LAYER M4 ;
        RECT  414.636 184.224 414.72 184.248 ;
    END
  END c_o[79]
  PIN c_o[7]
    DIRECTION OUTPUT ;
    USE SIGNAL ;
    PORT
      LAYER M4 ;
        RECT  414.636 173.856 414.72 173.88 ;
    END
  END c_o[7]
  PIN c_o[80]
    DIRECTION OUTPUT ;
    USE SIGNAL ;
    PORT
      LAYER M4 ;
        RECT  414.636 184.368 414.72 184.392 ;
    END
  END c_o[80]
  PIN c_o[81]
    DIRECTION OUTPUT ;
    USE SIGNAL ;
    PORT
      LAYER M4 ;
        RECT  414.636 184.512 414.72 184.536 ;
    END
  END c_o[81]
  PIN c_o[82]
    DIRECTION OUTPUT ;
    USE SIGNAL ;
    PORT
      LAYER M4 ;
        RECT  414.636 184.656 414.72 184.68 ;
    END
  END c_o[82]
  PIN c_o[83]
    DIRECTION OUTPUT ;
    USE SIGNAL ;
    PORT
      LAYER M4 ;
        RECT  414.636 184.8 414.72 184.824 ;
    END
  END c_o[83]
  PIN c_o[84]
    DIRECTION OUTPUT ;
    USE SIGNAL ;
    PORT
      LAYER M4 ;
        RECT  414.636 184.944 414.72 184.968 ;
    END
  END c_o[84]
  PIN c_o[85]
    DIRECTION OUTPUT ;
    USE SIGNAL ;
    PORT
      LAYER M4 ;
        RECT  414.636 185.088 414.72 185.112 ;
    END
  END c_o[85]
  PIN c_o[86]
    DIRECTION OUTPUT ;
    USE SIGNAL ;
    PORT
      LAYER M4 ;
        RECT  414.636 185.232 414.72 185.256 ;
    END
  END c_o[86]
  PIN c_o[87]
    DIRECTION OUTPUT ;
    USE SIGNAL ;
    PORT
      LAYER M4 ;
        RECT  414.636 185.376 414.72 185.4 ;
    END
  END c_o[87]
  PIN c_o[88]
    DIRECTION OUTPUT ;
    USE SIGNAL ;
    PORT
      LAYER M4 ;
        RECT  414.636 185.52 414.72 185.544 ;
    END
  END c_o[88]
  PIN c_o[89]
    DIRECTION OUTPUT ;
    USE SIGNAL ;
    PORT
      LAYER M4 ;
        RECT  414.636 185.664 414.72 185.688 ;
    END
  END c_o[89]
  PIN c_o[8]
    DIRECTION OUTPUT ;
    USE SIGNAL ;
    PORT
      LAYER M4 ;
        RECT  414.636 174 414.72 174.024 ;
    END
  END c_o[8]
  PIN c_o[90]
    DIRECTION OUTPUT ;
    USE SIGNAL ;
    PORT
      LAYER M4 ;
        RECT  414.636 185.808 414.72 185.832 ;
    END
  END c_o[90]
  PIN c_o[91]
    DIRECTION OUTPUT ;
    USE SIGNAL ;
    PORT
      LAYER M4 ;
        RECT  414.636 185.952 414.72 185.976 ;
    END
  END c_o[91]
  PIN c_o[92]
    DIRECTION OUTPUT ;
    USE SIGNAL ;
    PORT
      LAYER M4 ;
        RECT  414.636 186.096 414.72 186.12 ;
    END
  END c_o[92]
  PIN c_o[93]
    DIRECTION OUTPUT ;
    USE SIGNAL ;
    PORT
      LAYER M4 ;
        RECT  414.636 186.24 414.72 186.264 ;
    END
  END c_o[93]
  PIN c_o[94]
    DIRECTION OUTPUT ;
    USE SIGNAL ;
    PORT
      LAYER M4 ;
        RECT  414.636 186.384 414.72 186.408 ;
    END
  END c_o[94]
  PIN c_o[95]
    DIRECTION OUTPUT ;
    USE SIGNAL ;
    PORT
      LAYER M4 ;
        RECT  414.636 186.528 414.72 186.552 ;
    END
  END c_o[95]
  PIN c_o[96]
    DIRECTION OUTPUT ;
    USE SIGNAL ;
    PORT
      LAYER M4 ;
        RECT  414.636 186.672 414.72 186.696 ;
    END
  END c_o[96]
  PIN c_o[97]
    DIRECTION OUTPUT ;
    USE SIGNAL ;
    PORT
      LAYER M4 ;
        RECT  414.636 186.816 414.72 186.84 ;
    END
  END c_o[97]
  PIN c_o[98]
    DIRECTION OUTPUT ;
    USE SIGNAL ;
    PORT
      LAYER M4 ;
        RECT  414.636 186.96 414.72 186.984 ;
    END
  END c_o[98]
  PIN c_o[99]
    DIRECTION OUTPUT ;
    USE SIGNAL ;
    PORT
      LAYER M4 ;
        RECT  414.636 187.104 414.72 187.128 ;
    END
  END c_o[99]
  PIN c_o[9]
    DIRECTION OUTPUT ;
    USE SIGNAL ;
    PORT
      LAYER M4 ;
        RECT  414.636 174.144 414.72 174.168 ;
    END
  END c_o[9]
  PIN clk
    DIRECTION INPUT ;
    USE SIGNAL ;
    PORT
      LAYER M5 ;
        RECT  207.312 0 207.336 0.084 ;
    END
  END clk
  PIN rst_n
    DIRECTION INPUT ;
    USE SIGNAL ;
    PORT
      LAYER M5 ;
        RECT  207.168 0 207.192 0.084 ;
    END
  END rst_n
  PIN VSS
    DIRECTION INOUT ;
    USE GROUND ;
    PORT
      LAYER M5 ;
        RECT  408.084 4.297 408.204 263.543 ;
        RECT  403.764 4.297 403.884 263.543 ;
        RECT  399.444 4.297 399.564 263.543 ;
        RECT  395.124 4.297 395.244 263.543 ;
        RECT  390.804 4.297 390.924 263.543 ;
        RECT  386.484 4.297 386.604 263.543 ;
        RECT  382.164 4.297 382.284 263.543 ;
        RECT  377.844 4.297 377.964 263.543 ;
        RECT  373.524 4.297 373.644 263.543 ;
        RECT  369.204 4.297 369.324 263.543 ;
        RECT  364.884 4.297 365.004 263.543 ;
        RECT  360.564 4.297 360.684 263.543 ;
        RECT  356.244 4.297 356.364 263.543 ;
        RECT  351.924 4.297 352.044 263.543 ;
        RECT  347.604 4.297 347.724 263.543 ;
        RECT  343.284 4.297 343.404 263.543 ;
        RECT  338.964 4.297 339.084 263.543 ;
        RECT  334.644 4.297 334.764 263.543 ;
        RECT  330.324 4.297 330.444 263.543 ;
        RECT  326.004 4.297 326.124 263.543 ;
        RECT  321.684 4.297 321.804 263.543 ;
        RECT  317.364 4.297 317.484 263.543 ;
        RECT  313.044 4.297 313.164 263.543 ;
        RECT  308.724 4.297 308.844 263.543 ;
        RECT  304.404 4.297 304.524 263.543 ;
        RECT  300.084 4.297 300.204 263.543 ;
        RECT  295.764 4.297 295.884 263.543 ;
        RECT  291.444 4.297 291.564 263.543 ;
        RECT  287.124 4.297 287.244 263.543 ;
        RECT  282.804 4.297 282.924 263.543 ;
        RECT  278.484 4.297 278.604 263.543 ;
        RECT  274.164 4.297 274.284 263.543 ;
        RECT  269.844 4.297 269.964 263.543 ;
        RECT  265.524 4.297 265.644 263.543 ;
        RECT  261.204 4.297 261.324 263.543 ;
        RECT  256.884 4.297 257.004 263.543 ;
        RECT  252.564 4.297 252.684 263.543 ;
        RECT  248.244 4.297 248.364 263.543 ;
        RECT  243.924 4.297 244.044 263.543 ;
        RECT  239.604 4.297 239.724 263.543 ;
        RECT  235.284 4.297 235.404 263.543 ;
        RECT  230.964 4.297 231.084 263.543 ;
        RECT  226.644 4.297 226.764 263.543 ;
        RECT  222.324 4.297 222.444 263.543 ;
        RECT  218.004 4.297 218.124 263.543 ;
        RECT  213.684 4.297 213.804 263.543 ;
        RECT  209.364 4.297 209.484 263.543 ;
        RECT  205.044 4.297 205.164 263.543 ;
        RECT  200.724 4.297 200.844 263.543 ;
        RECT  196.404 4.297 196.524 263.543 ;
        RECT  192.084 4.297 192.204 263.543 ;
        RECT  187.764 4.297 187.884 263.543 ;
        RECT  183.444 4.297 183.564 263.543 ;
        RECT  179.124 4.297 179.244 263.543 ;
        RECT  174.804 4.297 174.924 263.543 ;
        RECT  170.484 4.297 170.604 263.543 ;
        RECT  166.164 4.297 166.284 263.543 ;
        RECT  161.844 4.297 161.964 263.543 ;
        RECT  157.524 4.297 157.644 263.543 ;
        RECT  153.204 4.297 153.324 263.543 ;
        RECT  148.884 4.297 149.004 263.543 ;
        RECT  144.564 4.297 144.684 263.543 ;
        RECT  140.244 4.297 140.364 263.543 ;
        RECT  135.924 4.297 136.044 263.543 ;
        RECT  131.604 4.297 131.724 263.543 ;
        RECT  127.284 4.297 127.404 263.543 ;
        RECT  122.964 4.297 123.084 263.543 ;
        RECT  118.644 4.297 118.764 263.543 ;
        RECT  114.324 4.297 114.444 263.543 ;
        RECT  110.004 4.297 110.124 263.543 ;
        RECT  105.684 4.297 105.804 263.543 ;
        RECT  101.364 4.297 101.484 263.543 ;
        RECT  97.044 4.297 97.164 263.543 ;
        RECT  92.724 4.297 92.844 263.543 ;
        RECT  88.404 4.297 88.524 263.543 ;
        RECT  84.084 4.297 84.204 263.543 ;
        RECT  79.764 4.297 79.884 263.543 ;
        RECT  75.444 4.297 75.564 263.543 ;
        RECT  71.124 4.297 71.244 263.543 ;
        RECT  66.804 4.297 66.924 263.543 ;
        RECT  62.484 4.297 62.604 263.543 ;
        RECT  58.164 4.297 58.284 263.543 ;
        RECT  53.844 4.297 53.964 263.543 ;
        RECT  49.524 4.297 49.644 263.543 ;
        RECT  45.204 4.297 45.324 263.543 ;
        RECT  40.884 4.297 41.004 263.543 ;
        RECT  36.564 4.297 36.684 263.543 ;
        RECT  32.244 4.297 32.364 263.543 ;
        RECT  27.924 4.297 28.044 263.543 ;
        RECT  23.604 4.297 23.724 263.543 ;
        RECT  19.284 4.297 19.404 263.543 ;
        RECT  14.964 4.297 15.084 263.543 ;
        RECT  10.644 4.297 10.764 263.543 ;
        RECT  6.324 4.297 6.444 263.543 ;
    END
  END VSS
  PIN VDD
    DIRECTION INOUT ;
    USE POWER ;
    PORT
      LAYER M5 ;
        RECT  408.276 4.311 408.396 263.529 ;
        RECT  403.956 4.311 404.076 263.529 ;
        RECT  399.636 4.311 399.756 263.529 ;
        RECT  395.316 4.311 395.436 263.529 ;
        RECT  390.996 4.311 391.116 263.529 ;
        RECT  386.676 4.311 386.796 263.529 ;
        RECT  382.356 4.311 382.476 263.529 ;
        RECT  378.036 4.311 378.156 263.529 ;
        RECT  373.716 4.311 373.836 263.529 ;
        RECT  369.396 4.311 369.516 263.529 ;
        RECT  365.076 4.311 365.196 263.529 ;
        RECT  360.756 4.311 360.876 263.529 ;
        RECT  356.436 4.311 356.556 263.529 ;
        RECT  352.116 4.311 352.236 263.529 ;
        RECT  347.796 4.311 347.916 263.529 ;
        RECT  343.476 4.311 343.596 263.529 ;
        RECT  339.156 4.311 339.276 263.529 ;
        RECT  334.836 4.311 334.956 263.529 ;
        RECT  330.516 4.311 330.636 263.529 ;
        RECT  326.196 4.311 326.316 263.529 ;
        RECT  321.876 4.311 321.996 263.529 ;
        RECT  317.556 4.311 317.676 263.529 ;
        RECT  313.236 4.311 313.356 263.529 ;
        RECT  308.916 4.311 309.036 263.529 ;
        RECT  304.596 4.311 304.716 263.529 ;
        RECT  300.276 4.311 300.396 263.529 ;
        RECT  295.956 4.311 296.076 263.529 ;
        RECT  291.636 4.311 291.756 263.529 ;
        RECT  287.316 4.311 287.436 263.529 ;
        RECT  282.996 4.311 283.116 263.529 ;
        RECT  278.676 4.311 278.796 263.529 ;
        RECT  274.356 4.311 274.476 263.529 ;
        RECT  270.036 4.311 270.156 263.529 ;
        RECT  265.716 4.311 265.836 263.529 ;
        RECT  261.396 4.311 261.516 263.529 ;
        RECT  257.076 4.311 257.196 263.529 ;
        RECT  252.756 4.311 252.876 263.529 ;
        RECT  248.436 4.311 248.556 263.529 ;
        RECT  244.116 4.311 244.236 263.529 ;
        RECT  239.796 4.311 239.916 263.529 ;
        RECT  235.476 4.311 235.596 263.529 ;
        RECT  231.156 4.311 231.276 263.529 ;
        RECT  226.836 4.311 226.956 263.529 ;
        RECT  222.516 4.311 222.636 263.529 ;
        RECT  218.196 4.311 218.316 263.529 ;
        RECT  213.876 4.311 213.996 263.529 ;
        RECT  209.556 4.311 209.676 263.529 ;
        RECT  205.236 4.311 205.356 263.529 ;
        RECT  200.916 4.311 201.036 263.529 ;
        RECT  196.596 4.311 196.716 263.529 ;
        RECT  192.276 4.311 192.396 263.529 ;
        RECT  187.956 4.311 188.076 263.529 ;
        RECT  183.636 4.311 183.756 263.529 ;
        RECT  179.316 4.311 179.436 263.529 ;
        RECT  174.996 4.311 175.116 263.529 ;
        RECT  170.676 4.311 170.796 263.529 ;
        RECT  166.356 4.311 166.476 263.529 ;
        RECT  162.036 4.311 162.156 263.529 ;
        RECT  157.716 4.311 157.836 263.529 ;
        RECT  153.396 4.311 153.516 263.529 ;
        RECT  149.076 4.311 149.196 263.529 ;
        RECT  144.756 4.311 144.876 263.529 ;
        RECT  140.436 4.311 140.556 263.529 ;
        RECT  136.116 4.311 136.236 263.529 ;
        RECT  131.796 4.311 131.916 263.529 ;
        RECT  127.476 4.311 127.596 263.529 ;
        RECT  123.156 4.311 123.276 263.529 ;
        RECT  118.836 4.311 118.956 263.529 ;
        RECT  114.516 4.311 114.636 263.529 ;
        RECT  110.196 4.311 110.316 263.529 ;
        RECT  105.876 4.311 105.996 263.529 ;
        RECT  101.556 4.311 101.676 263.529 ;
        RECT  97.236 4.311 97.356 263.529 ;
        RECT  92.916 4.311 93.036 263.529 ;
        RECT  88.596 4.311 88.716 263.529 ;
        RECT  84.276 4.311 84.396 263.529 ;
        RECT  79.956 4.311 80.076 263.529 ;
        RECT  75.636 4.311 75.756 263.529 ;
        RECT  71.316 4.311 71.436 263.529 ;
        RECT  66.996 4.311 67.116 263.529 ;
        RECT  62.676 4.311 62.796 263.529 ;
        RECT  58.356 4.311 58.476 263.529 ;
        RECT  54.036 4.311 54.156 263.529 ;
        RECT  49.716 4.311 49.836 263.529 ;
        RECT  45.396 4.311 45.516 263.529 ;
        RECT  41.076 4.311 41.196 263.529 ;
        RECT  36.756 4.311 36.876 263.529 ;
        RECT  32.436 4.311 32.556 263.529 ;
        RECT  28.116 4.311 28.236 263.529 ;
        RECT  23.796 4.311 23.916 263.529 ;
        RECT  19.476 4.311 19.596 263.529 ;
        RECT  15.156 4.311 15.276 263.529 ;
        RECT  10.836 4.311 10.956 263.529 ;
        RECT  6.516 4.311 6.636 263.529 ;
    END
  END VDD
  OBS
    LAYER RVTN ;
     RECT  4.32 0 414.72 267.84 ;
    LAYER RVTP ;
     RECT  4.32 0 414.72 267.84 ;
    LAYER M1 ;
     RECT  4.32 0 414.72 267.84 ;
    LAYER M2 ;
     RECT  4.32 0 414.72 267.84 ;
    LAYER M3 ;
     RECT  4.32 0 414.72 267.84 ;
    LAYER M4 ;
     RECT  4.32 0 414.72 267.84 ;
    LAYER M5 ;
     RECT  4.32 0 414.72 267.84 ;
  END
END qfd_qc_su_lane_w_l4
END LIBRARY
